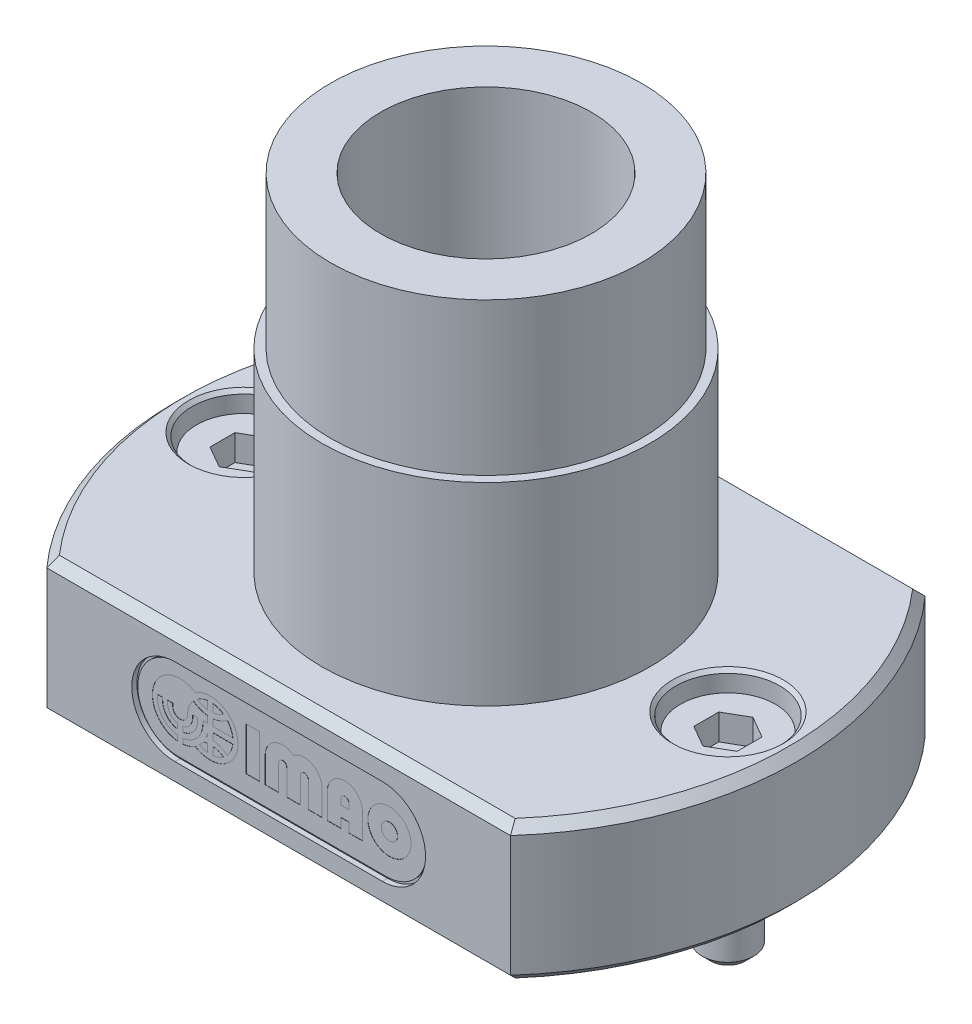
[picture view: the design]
ISO-10303-21;
HEADER;
FILE_DESCRIPTION(('STEP AP214'),'2;1');
FILE_NAME('part.step','',(''),(''),'','','');
FILE_SCHEMA(('AUTOMOTIVE_DESIGN { 1 0 10303 214 1 1 1 1 }'));
ENDSEC;
DATA;
#1=APPLICATION_CONTEXT('core data for automotive mechanical design processes');
#2=APPLICATION_PROTOCOL_DEFINITION('international standard','automotive_design',2000,#1);
#3=PRODUCT_CONTEXT('',#1,'mechanical');
#4=PRODUCT('Part','Part','',(#3));
#5=PRODUCT_RELATED_PRODUCT_CATEGORY('part','',(#4));
#6=PRODUCT_DEFINITION_FORMATION('','',#4);
#7=PRODUCT_DEFINITION_CONTEXT('part definition',#1,'design');
#8=PRODUCT_DEFINITION('design','',#6,#7);
#9=PRODUCT_DEFINITION_SHAPE('','',#8);
#10=(LENGTH_UNIT() NAMED_UNIT(*) SI_UNIT(.MILLI.,.METRE.));
#11=(NAMED_UNIT(*) PLANE_ANGLE_UNIT() SI_UNIT($,.RADIAN.));
#12=(NAMED_UNIT(*) SI_UNIT($,.STERADIAN.) SOLID_ANGLE_UNIT());
#13=UNCERTAINTY_MEASURE_WITH_UNIT(LENGTH_MEASURE(1.E-05),#10,'distance_accuracy_value','');
#14=(GEOMETRIC_REPRESENTATION_CONTEXT(3) GLOBAL_UNCERTAINTY_ASSIGNED_CONTEXT((#13)) GLOBAL_UNIT_ASSIGNED_CONTEXT((#10,
#11,#12)) REPRESENTATION_CONTEXT('',''));
#15=CARTESIAN_POINT('',(0.,0.,0.));
#16=DIRECTION('',(0.,0.,1.));
#17=DIRECTION('',(1.,0.,0.));
#18=AXIS2_PLACEMENT_3D('',#15,#16,#17);
#19=CARTESIAN_POINT('',(-6.,4.,11.8));
#20=DIRECTION('',(0.,0.,1.));
#21=DIRECTION('',(1.,0.,0.));
#22=AXIS2_PLACEMENT_3D('',#19,#20,#21);
#23=PLANE('',#22);
#24=CARTESIAN_POINT('',(6.20934262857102,4.,11.8));
#25=DIRECTION('',(0.,0.,1.));
#26=DIRECTION('',(1.,0.,0.));
#27=AXIS2_PLACEMENT_3D('',#24,#25,#26);
#28=CIRCLE('',#27,1.25038079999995);
#29=CARTESIAN_POINT('',(7.45972342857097,4.,11.8));
#30=VERTEX_POINT('',#29);
#31=EDGE_CURVE('E1095',#30,#30,#28,.T.);
#32=ORIENTED_EDGE('',*,*,#31,.F.);
#33=EDGE_LOOP('',(#32));
#34=FACE_BOUND('',#33,.T.);
#35=DIRECTION('',(0.,1.,0.));
#36=VECTOR('',#35,1.);
#37=CARTESIAN_POINT('',(4.64636662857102,4.,11.8));
#38=LINE('',#37,#36);
#39=CARTESIAN_POINT('',(4.64636662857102,2.74961920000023,11.8));
#40=VERTEX_POINT('',#39);
#41=CARTESIAN_POINT('',(4.64636662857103,4.23444661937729,11.8));
#42=VERTEX_POINT('',#41);
#43=EDGE_CURVE('E1154',#40,#42,#38,.T.);
#44=ORIENTED_EDGE('',*,*,#43,.F.);
#45=DIRECTION('',(1.,0.,0.));
#46=VECTOR('',#45,1.);
#47=CARTESIAN_POINT('',(-5.9,2.74961920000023,11.8));
#48=LINE('',#47,#46);
#49=CARTESIAN_POINT('',(3.86487862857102,2.74961920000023,11.8));
#50=VERTEX_POINT('',#49);
#51=EDGE_CURVE('E1132',#50,#40,#48,.T.);
#52=ORIENTED_EDGE('',*,*,#51,.F.);
#53=DIRECTION('',(0.,1.,0.));
#54=VECTOR('',#53,1.);
#55=CARTESIAN_POINT('',(3.86487862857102,4.,11.8));
#56=LINE('',#55,#54);
#57=CARTESIAN_POINT('',(3.86487862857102,3.29666080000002,11.8));
#58=VERTEX_POINT('',#57);
#59=EDGE_CURVE('E1135',#50,#58,#56,.T.);
#60=ORIENTED_EDGE('',*,*,#59,.T.);
#61=DIRECTION('',(1.,-2.21976981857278E-13,0.));
#62=VECTOR('',#61,1.);
#63=CARTESIAN_POINT('',(-5.90000000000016,3.29666080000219,11.8));
#64=LINE('',#63,#62);
#65=CARTESIAN_POINT('',(3.39598582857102,3.29666080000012,11.8));
#66=VERTEX_POINT('',#65);
#67=EDGE_CURVE('E1139',#66,#58,#64,.T.);
#68=ORIENTED_EDGE('',*,*,#67,.F.);
#69=DIRECTION('',(0.,1.,0.));
#70=VECTOR('',#69,1.);
#71=CARTESIAN_POINT('',(3.39598582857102,4.,11.8));
#72=LINE('',#71,#70);
#73=CARTESIAN_POINT('',(3.39598582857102,2.74961919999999,11.8));
#74=VERTEX_POINT('',#73);
#75=EDGE_CURVE('E1142',#74,#66,#72,.T.);
#76=ORIENTED_EDGE('',*,*,#75,.F.);
#77=DIRECTION('',(1.,0.,0.));
#78=VECTOR('',#77,1.);
#79=CARTESIAN_POINT('',(-5.9,2.7496192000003,11.8));
#80=LINE('',#79,#78);
#81=CARTESIAN_POINT('',(2.61449782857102,2.74961920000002,11.8));
#82=VERTEX_POINT('',#81);
#83=EDGE_CURVE('E1145',#82,#74,#80,.T.);
#84=ORIENTED_EDGE('',*,*,#83,.F.);
#85=DIRECTION('',(0.,-1.,0.));
#86=VECTOR('',#85,1.);
#87=CARTESIAN_POINT('',(2.61449782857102,4.,11.8));
#88=LINE('',#87,#86);
#89=CARTESIAN_POINT('',(2.61449782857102,4.23444661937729,11.8));
#90=VERTEX_POINT('',#89);
#91=EDGE_CURVE('E1148',#90,#82,#88,.T.);
#92=ORIENTED_EDGE('',*,*,#91,.F.);
#93=CARTESIAN_POINT('',(3.63043222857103,4.23444661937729,11.8));
#94=DIRECTION('',(0.,0.,1.));
#95=DIRECTION('',(1.,0.,0.));
#96=AXIS2_PLACEMENT_3D('',#93,#94,#95);
#97=CIRCLE('',#96,1.0159344);
#98=EDGE_CURVE('E1151',#42,#90,#97,.T.);
#99=ORIENTED_EDGE('',*,*,#98,.F.);
#100=EDGE_LOOP('',(#44,#52,#60,#68,#76,#84,#92,#99));
#101=FACE_BOUND('',#100,.T.);
#102=CARTESIAN_POINT('',(1.28596822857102,4.23444640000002,11.8));
#103=DIRECTION('',(0.,0.,1.));
#104=DIRECTION('',(1.,0.,0.));
#105=AXIS2_PLACEMENT_3D('',#102,#103,#104);
#106=CIRCLE('',#105,1.0159344);
#107=CARTESIAN_POINT('',(2.30190262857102,4.23444640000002,11.8));
#108=VERTEX_POINT('',#107);
#109=CARTESIAN_POINT('',(0.660777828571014,5.03523330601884,11.8));
#110=VERTEX_POINT('',#109);
#111=EDGE_CURVE('E1261',#108,#110,#106,.T.);
#112=ORIENTED_EDGE('',*,*,#111,.F.);
#113=DIRECTION('',(0.,1.,0.));
#114=VECTOR('',#113,1.);
#115=CARTESIAN_POINT('',(2.30190262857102,4.,11.8));
#116=LINE('',#115,#114);
#117=CARTESIAN_POINT('',(2.30190262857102,2.74961920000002,11.8));
#118=VERTEX_POINT('',#117);
#119=EDGE_CURVE('E1224',#118,#108,#116,.T.);
#120=ORIENTED_EDGE('',*,*,#119,.F.);
#121=DIRECTION('',(1.,0.,0.));
#122=VECTOR('',#121,1.);
#123=CARTESIAN_POINT('',(-5.9,2.74961920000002,11.8));
#124=LINE('',#123,#122);
#125=CARTESIAN_POINT('',(1.52041462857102,2.74961920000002,11.8));
#126=VERTEX_POINT('',#125);
#127=EDGE_CURVE('E1227',#126,#118,#124,.T.);
#128=ORIENTED_EDGE('',*,*,#127,.F.);
#129=DIRECTION('',(0.,-1.,0.));
#130=VECTOR('',#129,1.);
#131=CARTESIAN_POINT('',(1.52041462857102,4.,11.8));
#132=LINE('',#131,#130);
#133=CARTESIAN_POINT('',(1.52041462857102,4.23444640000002,11.8));
#134=VERTEX_POINT('',#133);
#135=EDGE_CURVE('E1231',#134,#126,#132,.T.);
#136=ORIENTED_EDGE('',*,*,#135,.F.);
#137=CARTESIAN_POINT('',(1.28596822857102,4.23444640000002,11.8));
#138=DIRECTION('',(0.,0.,1.));
#139=DIRECTION('',(1.,0.,0.));
#140=AXIS2_PLACEMENT_3D('',#137,#138,#139);
#141=CIRCLE('',#140,0.2344464);
#142=CARTESIAN_POINT('',(1.05152182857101,4.23444640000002,11.8));
#143=VERTEX_POINT('',#142);
#144=EDGE_CURVE('E1234',#134,#143,#141,.T.);
#145=ORIENTED_EDGE('',*,*,#144,.T.);
#146=DIRECTION('',(0.,1.,0.));
#147=VECTOR('',#146,1.);
#148=CARTESIAN_POINT('',(1.05152182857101,4.,11.8));
#149=LINE('',#148,#147);
#150=CARTESIAN_POINT('',(1.05152182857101,2.74961920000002,11.8));
#151=VERTEX_POINT('',#150);
#152=EDGE_CURVE('E1237',#151,#143,#149,.T.);
#153=ORIENTED_EDGE('',*,*,#152,.F.);
#154=DIRECTION('',(1.,0.,0.));
#155=VECTOR('',#154,1.);
#156=CARTESIAN_POINT('',(-5.9,2.74961920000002,11.8));
#157=LINE('',#156,#155);
#158=CARTESIAN_POINT('',(0.270033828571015,2.74961920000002,11.8));
#159=VERTEX_POINT('',#158);
#160=EDGE_CURVE('E1240',#159,#151,#157,.T.);
#161=ORIENTED_EDGE('',*,*,#160,.F.);
#162=DIRECTION('',(0.,-1.,0.));
#163=VECTOR('',#162,1.);
#164=CARTESIAN_POINT('',(0.270033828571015,4.,11.8));
#165=LINE('',#164,#163);
#166=CARTESIAN_POINT('',(0.270033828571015,4.23444640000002,11.8));
#167=VERTEX_POINT('',#166);
#168=EDGE_CURVE('E1243',#167,#159,#165,.T.);
#169=ORIENTED_EDGE('',*,*,#168,.F.);
#170=CARTESIAN_POINT('',(0.0355874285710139,4.23444640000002,11.8));
#171=DIRECTION('',(0.,0.,1.));
#172=DIRECTION('',(1.,0.,0.));
#173=AXIS2_PLACEMENT_3D('',#170,#171,#172);
#174=CIRCLE('',#173,0.2344464);
#175=CARTESIAN_POINT('',(-0.198858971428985,4.23444640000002,11.8));
#176=VERTEX_POINT('',#175);
#177=EDGE_CURVE('E1246',#167,#176,#174,.T.);
#178=ORIENTED_EDGE('',*,*,#177,.T.);
#179=DIRECTION('',(0.,1.,0.));
#180=VECTOR('',#179,1.);
#181=CARTESIAN_POINT('',(-0.198858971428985,4.,11.8));
#182=LINE('',#181,#180);
#183=CARTESIAN_POINT('',(-0.198858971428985,2.74961920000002,11.8));
#184=VERTEX_POINT('',#183);
#185=EDGE_CURVE('E1249',#184,#176,#182,.T.);
#186=ORIENTED_EDGE('',*,*,#185,.F.);
#187=DIRECTION('',(1.,0.,0.));
#188=VECTOR('',#187,1.);
#189=CARTESIAN_POINT('',(-5.9,2.74961920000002,11.8));
#190=LINE('',#189,#188);
#191=CARTESIAN_POINT('',(-0.980346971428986,2.74961920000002,11.8));
#192=VERTEX_POINT('',#191);
#193=EDGE_CURVE('E1252',#192,#184,#190,.T.);
#194=ORIENTED_EDGE('',*,*,#193,.F.);
#195=DIRECTION('',(0.,-1.,0.));
#196=VECTOR('',#195,1.);
#197=CARTESIAN_POINT('',(-0.980346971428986,4.,11.8));
#198=LINE('',#197,#196);
#199=CARTESIAN_POINT('',(-0.980346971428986,4.23444640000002,11.8));
#200=VERTEX_POINT('',#199);
#201=EDGE_CURVE('E1255',#200,#192,#198,.T.);
#202=ORIENTED_EDGE('',*,*,#201,.F.);
#203=CARTESIAN_POINT('',(0.0355874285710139,4.23444640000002,11.8));
#204=DIRECTION('',(0.,0.,1.));
#205=DIRECTION('',(1.,0.,0.));
#206=AXIS2_PLACEMENT_3D('',#203,#204,#205);
#207=CIRCLE('',#206,1.0159344);
#208=EDGE_CURVE('E1258',#110,#200,#207,.T.);
#209=ORIENTED_EDGE('',*,*,#208,.F.);
#210=EDGE_LOOP('',(#112,#120,#128,#136,#145,#153,#161,#169,#178,#186,#194,#202,#209));
#211=FACE_BOUND('',#210,.T.);
#212=DIRECTION('',(1.,0.,0.));
#213=VECTOR('',#212,1.);
#214=CARTESIAN_POINT('',(-5.9,2.74961920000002,11.8));
#215=LINE('',#214,#213);
#216=CARTESIAN_POINT('',(-2.07443017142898,2.74961920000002,11.8));
#217=VERTEX_POINT('',#216);
#218=CARTESIAN_POINT('',(-1.29294217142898,2.74961920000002,11.8));
#219=VERTEX_POINT('',#218);
#220=EDGE_CURVE('E1318',#217,#219,#215,.T.);
#221=ORIENTED_EDGE('',*,*,#220,.F.);
#222=DIRECTION('',(0.,-1.,0.));
#223=VECTOR('',#222,1.);
#224=CARTESIAN_POINT('',(-2.07443017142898,4.,11.8));
#225=LINE('',#224,#223);
#226=CARTESIAN_POINT('',(-2.07443017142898,5.25038080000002,11.8));
#227=VERTEX_POINT('',#226);
#228=EDGE_CURVE('E1308',#227,#217,#225,.T.);
#229=ORIENTED_EDGE('',*,*,#228,.F.);
#230=DIRECTION('',(-1.,0.,0.));
#231=VECTOR('',#230,1.);
#232=CARTESIAN_POINT('',(-5.9,5.25038080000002,11.8));
#233=LINE('',#232,#231);
#234=CARTESIAN_POINT('',(-1.29294217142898,5.25038080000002,11.8));
#235=VERTEX_POINT('',#234);
#236=EDGE_CURVE('E1311',#235,#227,#233,.T.);
#237=ORIENTED_EDGE('',*,*,#236,.F.);
#238=DIRECTION('',(0.,1.,0.));
#239=VECTOR('',#238,1.);
#240=CARTESIAN_POINT('',(-1.29294217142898,4.,11.8));
#241=LINE('',#240,#239);
#242=EDGE_CURVE('E1315',#219,#235,#241,.T.);
#243=ORIENTED_EDGE('',*,*,#242,.F.);
#244=EDGE_LOOP('',(#221,#229,#237,#243));
#245=FACE_BOUND('',#244,.T.);
#246=CARTESIAN_POINT('',(-6.,4.,11.8));
#247=DIRECTION('',(0.,0.,1.));
#248=DIRECTION('',(1.,0.,0.));
#249=AXIS2_PLACEMENT_3D('',#246,#247,#248);
#250=CIRCLE('',#249,2.35);
#251=CARTESIAN_POINT('',(-6.,6.35,11.8));
#252=VERTEX_POINT('',#251);
#253=CARTESIAN_POINT('',(-6.,1.65,11.8));
#254=VERTEX_POINT('',#253);
#255=EDGE_CURVE('E1591',#252,#254,#250,.T.);
#256=ORIENTED_EDGE('',*,*,#255,.T.);
#257=DIRECTION('',(1.,0.,0.));
#258=VECTOR('',#257,1.);
#259=CARTESIAN_POINT('',(-6.,1.65,11.8));
#260=LINE('',#259,#258);
#261=CARTESIAN_POINT('',(6.,1.65,11.8));
#262=VERTEX_POINT('',#261);
#263=EDGE_CURVE('E1709',#254,#262,#260,.T.);
#264=ORIENTED_EDGE('',*,*,#263,.T.);
#265=CARTESIAN_POINT('',(6.,4.,11.8));
#266=DIRECTION('',(0.,0.,1.));
#267=DIRECTION('',(1.,0.,0.));
#268=AXIS2_PLACEMENT_3D('',#265,#266,#267);
#269=CIRCLE('',#268,2.35);
#270=CARTESIAN_POINT('',(6.,6.35,11.8));
#271=VERTEX_POINT('',#270);
#272=EDGE_CURVE('E1712',#262,#271,#269,.T.);
#273=ORIENTED_EDGE('',*,*,#272,.T.);
#274=DIRECTION('',(-1.,0.,0.));
#275=VECTOR('',#274,1.);
#276=CARTESIAN_POINT('',(-6.,6.35,11.8));
#277=LINE('',#276,#275);
#278=EDGE_CURVE('E1698',#271,#252,#277,.T.);
#279=ORIENTED_EDGE('',*,*,#278,.T.);
#280=EDGE_LOOP('',(#256,#264,#273,#279));
#281=FACE_BOUND('',#280,.T.);
#282=CARTESIAN_POINT('',(-4.15839817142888,6.14350994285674,11.8));
#283=DIRECTION('',(0.,0.,1.));
#284=DIRECTION('',(1.,0.,0.));
#285=AXIS2_PLACEMENT_3D('',#282,#283,#284);
#286=CIRCLE('',#285,1.60763245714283);
#287=CARTESIAN_POINT('',(-5.14080342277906,4.8709683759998,11.8));
#288=VERTEX_POINT('',#287);
#289=CARTESIAN_POINT('',(-4.31916141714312,4.54393584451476,11.8));
#290=VERTEX_POINT('',#289);
#291=EDGE_CURVE('E1456',#288,#290,#286,.T.);
#292=ORIENTED_EDGE('',*,*,#291,.F.);
#293=CARTESIAN_POINT('',(-4.15839817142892,4.,11.8));
#294=DIRECTION('',(0.,0.,1.));
#295=DIRECTION('',(1.,0.,0.));
#296=AXIS2_PLACEMENT_3D('',#293,#294,#295);
#297=CIRCLE('',#296,1.31289983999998);
#298=CARTESIAN_POINT('',(-5.4712980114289,4.,11.8));
#299=VERTEX_POINT('',#298);
#300=EDGE_CURVE('E1320',#288,#299,#297,.T.);
#301=ORIENTED_EDGE('',*,*,#300,.T.);
#302=CARTESIAN_POINT('',(-5.9,4.,11.8));
#303=DIRECTION('',(0.,0.,1.));
#304=DIRECTION('',(1.,0.,0.));
#305=AXIS2_PLACEMENT_3D('',#302,#303,#304);
#306=CIRCLE('',#305,0.428701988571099);
#307=CARTESIAN_POINT('',(-6.3287019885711,4.,11.8));
#308=VERTEX_POINT('',#307);
#309=EDGE_CURVE('E1516',#308,#299,#306,.T.);
#310=ORIENTED_EDGE('',*,*,#309,.F.);
#311=DIRECTION('',(0.,-1.,0.));
#312=VECTOR('',#311,1.);
#313=CARTESIAN_POINT('',(-6.3287019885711,4.,11.8));
#314=LINE('',#313,#312);
#315=CARTESIAN_POINT('',(-6.3287019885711,4.16076324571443,11.8));
#316=VERTEX_POINT('',#315);
#317=EDGE_CURVE('E1513',#316,#308,#314,.T.);
#318=ORIENTED_EDGE('',*,*,#317,.F.);
#319=DIRECTION('',(1.,0.,0.));
#320=VECTOR('',#319,1.);
#321=CARTESIAN_POINT('',(-5.9,4.16076324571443,11.8));
#322=LINE('',#321,#320);
#323=CARTESIAN_POINT('',(-6.62343460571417,4.16076324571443,11.8));
#324=VERTEX_POINT('',#323);
#325=EDGE_CURVE('E1510',#324,#316,#322,.T.);
#326=ORIENTED_EDGE('',*,*,#325,.F.);
#327=DIRECTION('',(0.,1.,0.));
#328=VECTOR('',#327,1.);
#329=CARTESIAN_POINT('',(-6.62343460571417,4.,11.8));
#330=LINE('',#329,#328);
#331=CARTESIAN_POINT('',(-6.62343460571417,4.,11.8));
#332=VERTEX_POINT('',#331);
#333=EDGE_CURVE('E1507',#332,#324,#330,.T.);
#334=ORIENTED_EDGE('',*,*,#333,.F.);
#335=CARTESIAN_POINT('',(-5.9,4.,11.8));
#336=DIRECTION('',(0.,0.,1.));
#337=DIRECTION('',(1.,0.,0.));
#338=AXIS2_PLACEMENT_3D('',#335,#336,#337);
#339=CIRCLE('',#338,0.723434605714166);
#340=CARTESIAN_POINT('',(-6.06076324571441,3.29465412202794,11.8));
#341=VERTEX_POINT('',#340);
#342=EDGE_CURVE('E1504',#332,#341,#339,.T.);
#343=ORIENTED_EDGE('',*,*,#342,.T.);
#344=DIRECTION('',(0.,1.,0.));
#345=VECTOR('',#344,1.);
#346=CARTESIAN_POINT('',(-6.06076324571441,4.,11.8));
#347=LINE('',#346,#345);
#348=CARTESIAN_POINT('',(-6.06076324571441,2.99460471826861,11.8));
#349=VERTEX_POINT('',#348);
#350=EDGE_CURVE('E1501',#349,#341,#347,.T.);
#351=ORIENTED_EDGE('',*,*,#350,.F.);
#352=CARTESIAN_POINT('',(-5.9,4.,11.8));
#353=DIRECTION('',(0.,0.,1.));
#354=DIRECTION('',(1.,0.,0.));
#355=AXIS2_PLACEMENT_3D('',#352,#353,#354);
#356=CIRCLE('',#355,1.01816722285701);
#357=CARTESIAN_POINT('',(-6.91816722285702,4.,11.8));
#358=VERTEX_POINT('',#357);
#359=EDGE_CURVE('E1498',#358,#349,#356,.T.);
#360=ORIENTED_EDGE('',*,*,#359,.F.);
#361=DIRECTION('',(0.,-1.,0.));
#362=VECTOR('',#361,1.);
#363=CARTESIAN_POINT('',(-6.91816722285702,4.,11.8));
#364=LINE('',#363,#362);
#365=CARTESIAN_POINT('',(-6.91816722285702,4.16076324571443,11.8));
#366=VERTEX_POINT('',#365);
#367=EDGE_CURVE('E1495',#366,#358,#364,.T.);
#368=ORIENTED_EDGE('',*,*,#367,.F.);
#369=DIRECTION('',(1.,0.,0.));
#370=VECTOR('',#369,1.);
#371=CARTESIAN_POINT('',(-5.9,4.16076324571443,11.8));
#372=LINE('',#371,#370);
#373=CARTESIAN_POINT('',(-7.21289983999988,4.16076324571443,11.8));
#374=VERTEX_POINT('',#373);
#375=EDGE_CURVE('E1492',#374,#366,#372,.T.);
#376=ORIENTED_EDGE('',*,*,#375,.F.);
#377=DIRECTION('',(0.,1.,0.));
#378=VECTOR('',#377,1.);
#379=CARTESIAN_POINT('',(-7.21289983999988,4.,11.8));
#380=LINE('',#379,#378);
#381=CARTESIAN_POINT('',(-7.21289983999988,3.99999999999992,11.8));
#382=VERTEX_POINT('',#381);
#383=EDGE_CURVE('E1489',#382,#374,#380,.T.);
#384=ORIENTED_EDGE('',*,*,#383,.F.);
#385=CARTESIAN_POINT('',(-5.9,4.,11.8));
#386=DIRECTION('',(0.,0.,1.));
#387=DIRECTION('',(1.,0.,0.));
#388=AXIS2_PLACEMENT_3D('',#385,#386,#387);
#389=CIRCLE('',#388,1.31289983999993);
#390=CARTESIAN_POINT('',(-6.06076324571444,2.69697998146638,11.8));
#391=VERTEX_POINT('',#390);
#392=EDGE_CURVE('E1486',#382,#391,#389,.T.);
#393=ORIENTED_EDGE('',*,*,#392,.T.);
#394=DIRECTION('',(0.,1.,0.));
#395=VECTOR('',#394,1.);
#396=CARTESIAN_POINT('',(-6.06076324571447,4.,11.8));
#397=LINE('',#396,#395);
#398=CARTESIAN_POINT('',(-6.06076324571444,2.40042590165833,11.8));
#399=VERTEX_POINT('',#398);
#400=EDGE_CURVE('E1483',#399,#391,#397,.T.);
#401=ORIENTED_EDGE('',*,*,#400,.F.);
#402=CARTESIAN_POINT('',(-5.9,4.,11.8));
#403=DIRECTION('',(0.,0.,1.));
#404=DIRECTION('',(1.,0.,0.));
#405=AXIS2_PLACEMENT_3D('',#402,#403,#404);
#406=CIRCLE('',#405,1.60763245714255);
#407=CARTESIAN_POINT('',(-5.02919908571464,5.35136519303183,11.8));
#408=VERTEX_POINT('',#407);
#409=EDGE_CURVE('E1480',#408,#399,#406,.T.);
#410=ORIENTED_EDGE('',*,*,#409,.F.);
#411=CARTESIAN_POINT('',(-4.15839817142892,4.,11.8));
#412=DIRECTION('',(0.,0.,1.));
#413=DIRECTION('',(1.,0.,0.));
#414=AXIS2_PLACEMENT_3D('',#411,#412,#413);
#415=CIRCLE('',#414,1.60763245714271);
#416=CARTESIAN_POINT('',(-5.02919908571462,2.64863480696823,11.8));
#417=VERTEX_POINT('',#416);
#418=EDGE_CURVE('E1477',#417,#408,#415,.T.);
#419=ORIENTED_EDGE('',*,*,#418,.F.);
#420=CARTESIAN_POINT('',(-5.9,4.,11.8));
#421=DIRECTION('',(0.,0.,1.));
#422=DIRECTION('',(1.,0.,0.));
#423=AXIS2_PLACEMENT_3D('',#420,#421,#422);
#424=CIRCLE('',#423,1.60763245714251);
#425=CARTESIAN_POINT('',(-5.73923675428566,2.40042590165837,11.8));
#426=VERTEX_POINT('',#425);
#427=EDGE_CURVE('E1474',#426,#417,#424,.T.);
#428=ORIENTED_EDGE('',*,*,#427,.F.);
#429=DIRECTION('',(0.,1.,0.));
#430=VECTOR('',#429,1.);
#431=CARTESIAN_POINT('',(-5.73923675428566,4.,11.8));
#432=LINE('',#431,#430);
#433=CARTESIAN_POINT('',(-5.73923675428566,2.69697998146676,11.8));
#434=VERTEX_POINT('',#433);
#435=EDGE_CURVE('E1471',#426,#434,#432,.T.);
#436=ORIENTED_EDGE('',*,*,#435,.T.);
#437=CARTESIAN_POINT('',(-5.9,4.,11.8));
#438=DIRECTION('',(0.,0.,1.));
#439=DIRECTION('',(1.,0.,0.));
#440=AXIS2_PLACEMENT_3D('',#437,#438,#439);
#441=CIRCLE('',#440,1.3128998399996);
#442=CARTESIAN_POINT('',(-4.58710016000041,4.,11.8));
#443=VERTEX_POINT('',#442);
#444=EDGE_CURVE('E1468',#434,#443,#441,.T.);
#445=ORIENTED_EDGE('',*,*,#444,.T.);
#446=DIRECTION('',(0.,-1.,0.));
#447=VECTOR('',#446,1.);
#448=CARTESIAN_POINT('',(-4.58710016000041,4.,11.8));
#449=LINE('',#448,#447);
#450=CARTESIAN_POINT('',(-4.58710016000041,4.16076324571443,11.8));
#451=VERTEX_POINT('',#450);
#452=EDGE_CURVE('E1465',#451,#443,#449,.T.);
#453=ORIENTED_EDGE('',*,*,#452,.F.);
#454=DIRECTION('',(1.,0.,0.));
#455=VECTOR('',#454,1.);
#456=CARTESIAN_POINT('',(-5.9,4.16076324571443,11.8));
#457=LINE('',#456,#455);
#458=CARTESIAN_POINT('',(-4.31916141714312,4.16076324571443,11.8));
#459=VERTEX_POINT('',#458);
#460=EDGE_CURVE('E1462',#451,#459,#457,.T.);
#461=ORIENTED_EDGE('',*,*,#460,.T.);
#462=DIRECTION('',(0.,1.,0.));
#463=VECTOR('',#462,1.);
#464=CARTESIAN_POINT('',(-4.31916141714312,4.,11.8));
#465=LINE('',#464,#463);
#466=EDGE_CURVE('E1459',#459,#290,#465,.T.);
#467=ORIENTED_EDGE('',*,*,#466,.T.);
#468=EDGE_LOOP('',(#292,#301,#310,#318,#326,#334,#343,#351,#360,#368,#376,#384,#393,#401,#410,
#419,#428,#436,#445,#453,#461,#467));
#469=FACE_BOUND('',#468,.T.);
#470=CARTESIAN_POINT('',(-5.9,4.,11.8));
#471=DIRECTION('',(0.,0.,1.));
#472=DIRECTION('',(1.,0.,0.));
#473=AXIS2_PLACEMENT_3D('',#470,#471,#472);
#474=CIRCLE('',#473,1.01816722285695);
#475=CARTESIAN_POINT('',(-5.73923675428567,2.99460471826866,11.8));
#476=VERTEX_POINT('',#475);
#477=CARTESIAN_POINT('',(-4.88183277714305,4.,11.8));
#478=VERTEX_POINT('',#477);
#479=EDGE_CURVE('E1063',#476,#478,#474,.T.);
#480=ORIENTED_EDGE('',*,*,#479,.F.);
#481=DIRECTION('',(0.,1.,0.));
#482=VECTOR('',#481,1.);
#483=CARTESIAN_POINT('',(-5.73923675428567,2.99460471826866,11.8));
#484=LINE('',#483,#482);
#485=CARTESIAN_POINT('',(-5.73923675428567,3.29465412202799,11.8));
#486=VERTEX_POINT('',#485);
#487=EDGE_CURVE('E32',#476,#486,#484,.T.);
#488=ORIENTED_EDGE('',*,*,#487,.T.);
#489=CARTESIAN_POINT('',(-5.9,4.,11.8));
#490=DIRECTION('',(0.,0.,1.));
#491=DIRECTION('',(1.,0.,0.));
#492=AXIS2_PLACEMENT_3D('',#489,#490,#491);
#493=CIRCLE('',#492,0.723434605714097);
#494=CARTESIAN_POINT('',(-5.1765653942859,4.,11.8));
#495=VERTEX_POINT('',#494);
#496=EDGE_CURVE('E1076',#486,#495,#493,.T.);
#497=ORIENTED_EDGE('',*,*,#496,.T.);
#498=DIRECTION('',(0.,-1.,0.));
#499=VECTOR('',#498,1.);
#500=CARTESIAN_POINT('',(-5.1765653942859,4.16076324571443,11.8));
#501=LINE('',#500,#499);
#502=CARTESIAN_POINT('',(-5.1765653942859,4.16076324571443,11.8));
#503=VERTEX_POINT('',#502);
#504=EDGE_CURVE('E1073',#503,#495,#501,.T.);
#505=ORIENTED_EDGE('',*,*,#504,.F.);
#506=DIRECTION('',(1.,0.,0.));
#507=VECTOR('',#506,1.);
#508=CARTESIAN_POINT('',(-5.1765653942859,4.16076324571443,11.8));
#509=LINE('',#508,#507);
#510=CARTESIAN_POINT('',(-4.88183277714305,4.16076324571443,11.8));
#511=VERTEX_POINT('',#510);
#512=EDGE_CURVE('E1070',#503,#511,#509,.T.);
#513=ORIENTED_EDGE('',*,*,#512,.T.);
#514=DIRECTION('',(0.,1.,0.));
#515=VECTOR('',#514,1.);
#516=CARTESIAN_POINT('',(-4.88183277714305,4.,11.8));
#517=LINE('',#516,#515);
#518=EDGE_CURVE('E1066',#478,#511,#517,.T.);
#519=ORIENTED_EDGE('',*,*,#518,.F.);
#520=EDGE_LOOP('',(#480,#488,#497,#505,#513,#519));
#521=FACE_BOUND('',#520,.T.);
#522=ADVANCED_FACE('F15',(#34,#101,#211,#245,#281,#469,#521),#23,.T.);
#523=CARTESIAN_POINT('',(-6.,4.,11.7));
#524=DIRECTION('',(0.,0.,1.));
#525=DIRECTION('',(1.,0.,0.));
#526=AXIS2_PLACEMENT_3D('',#523,#524,#525);
#527=CYLINDRICAL_SURFACE('',#526,2.35);
#528=ORIENTED_EDGE('',*,*,#255,.F.);
#529=DIRECTION('',(0.,0.,1.));
#530=VECTOR('',#529,1.);
#531=CARTESIAN_POINT('',(-6.,6.35,11.7));
#532=LINE('',#531,#530);
#533=CARTESIAN_POINT('',(-6.,6.35,11.7));
#534=VERTEX_POINT('',#533);
#535=EDGE_CURVE('E10',#534,#252,#532,.T.);
#536=ORIENTED_EDGE('',*,*,#535,.F.);
#537=CARTESIAN_POINT('',(-6.,4.,11.7));
#538=DIRECTION('',(0.,0.,1.));
#539=DIRECTION('',(1.,0.,0.));
#540=AXIS2_PLACEMENT_3D('',#537,#538,#539);
#541=CIRCLE('',#540,2.35);
#542=CARTESIAN_POINT('',(-6.,1.65,11.7));
#543=VERTEX_POINT('',#542);
#544=EDGE_CURVE('E1694',#534,#543,#541,.T.);
#545=ORIENTED_EDGE('',*,*,#544,.T.);
#546=DIRECTION('',(0.,0.,1.));
#547=VECTOR('',#546,1.);
#548=CARTESIAN_POINT('',(-6.,1.65,11.7));
#549=LINE('',#548,#547);
#550=EDGE_CURVE('E19',#543,#254,#549,.T.);
#551=ORIENTED_EDGE('',*,*,#550,.T.);
#552=EDGE_LOOP('',(#528,#536,#545,#551));
#553=FACE_BOUND('',#552,.T.);
#554=ADVANCED_FACE('F17',(#553),#527,.T.);
#555=CARTESIAN_POINT('',(-6.,6.35,11.7));
#556=DIRECTION('',(0.,1.,0.));
#557=DIRECTION('',(-1.,0.,0.));
#558=AXIS2_PLACEMENT_3D('',#555,#556,#557);
#559=PLANE('',#558);
#560=ORIENTED_EDGE('',*,*,#278,.F.);
#561=DIRECTION('',(0.,0.,1.));
#562=VECTOR('',#561,1.);
#563=CARTESIAN_POINT('',(6.,6.35,11.7));
#564=LINE('',#563,#562);
#565=CARTESIAN_POINT('',(6.,6.35,11.7));
#566=VERTEX_POINT('',#565);
#567=EDGE_CURVE('E24',#566,#271,#564,.T.);
#568=ORIENTED_EDGE('',*,*,#567,.F.);
#569=DIRECTION('',(-1.,0.,0.));
#570=VECTOR('',#569,1.);
#571=CARTESIAN_POINT('',(-6.,6.35,11.7));
#572=LINE('',#571,#570);
#573=EDGE_CURVE('E1704',#566,#534,#572,.T.);
#574=ORIENTED_EDGE('',*,*,#573,.T.);
#575=ORIENTED_EDGE('',*,*,#535,.T.);
#576=EDGE_LOOP('',(#560,#568,#574,#575));
#577=FACE_BOUND('',#576,.T.);
#578=ADVANCED_FACE('F1732',(#577),#559,.T.);
#579=CARTESIAN_POINT('',(6.,4.,11.7));
#580=DIRECTION('',(0.,0.,1.));
#581=DIRECTION('',(1.,0.,0.));
#582=AXIS2_PLACEMENT_3D('',#579,#580,#581);
#583=CYLINDRICAL_SURFACE('',#582,2.35);
#584=ORIENTED_EDGE('',*,*,#272,.F.);
#585=DIRECTION('',(0.,0.,1.));
#586=VECTOR('',#585,1.);
#587=CARTESIAN_POINT('',(6.,1.65,11.7));
#588=LINE('',#587,#586);
#589=CARTESIAN_POINT('',(6.,1.65,11.7));
#590=VERTEX_POINT('',#589);
#591=EDGE_CURVE('E1717',#590,#262,#588,.T.);
#592=ORIENTED_EDGE('',*,*,#591,.F.);
#593=CARTESIAN_POINT('',(6.,4.,11.7));
#594=DIRECTION('',(0.,0.,1.));
#595=DIRECTION('',(1.,0.,0.));
#596=AXIS2_PLACEMENT_3D('',#593,#594,#595);
#597=CIRCLE('',#596,2.35);
#598=EDGE_CURVE('E1701',#590,#566,#597,.T.);
#599=ORIENTED_EDGE('',*,*,#598,.T.);
#600=ORIENTED_EDGE('',*,*,#567,.T.);
#601=EDGE_LOOP('',(#584,#592,#599,#600));
#602=FACE_BOUND('',#601,.T.);
#603=ADVANCED_FACE('F1735',(#602),#583,.T.);
#604=CARTESIAN_POINT('',(-6.,1.65,11.7));
#605=DIRECTION('',(0.,-1.,0.));
#606=DIRECTION('',(1.,0.,0.));
#607=AXIS2_PLACEMENT_3D('',#604,#605,#606);
#608=PLANE('',#607);
#609=ORIENTED_EDGE('',*,*,#263,.F.);
#610=ORIENTED_EDGE('',*,*,#550,.F.);
#611=DIRECTION('',(1.,0.,0.));
#612=VECTOR('',#611,1.);
#613=CARTESIAN_POINT('',(-6.,1.65,11.7));
#614=LINE('',#613,#612);
#615=EDGE_CURVE('E1697',#543,#590,#614,.T.);
#616=ORIENTED_EDGE('',*,*,#615,.T.);
#617=ORIENTED_EDGE('',*,*,#591,.T.);
#618=EDGE_LOOP('',(#609,#610,#616,#617));
#619=FACE_BOUND('',#618,.T.);
#620=ADVANCED_FACE('F1726',(#619),#608,.T.);
#621=CARTESIAN_POINT('',(-3.9976349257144,4.,11.79));
#622=DIRECTION('',(1.,0.,0.));
#623=DIRECTION('',(0.,0.,-1.));
#624=AXIS2_PLACEMENT_3D('',#621,#622,#623);
#625=PLANE('',#624);
#626=DIRECTION('',(0.,1.,0.));
#627=VECTOR('',#626,1.);
#628=CARTESIAN_POINT('',(-3.9976349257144,4.,11.8));
#629=LINE('',#628,#627);
#630=CARTESIAN_POINT('',(-3.9976349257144,4.16076324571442,11.8));
#631=VERTEX_POINT('',#630);
#632=CARTESIAN_POINT('',(-3.9976349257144,4.54393584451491,11.8));
#633=VERTEX_POINT('',#632);
#634=EDGE_CURVE('E1579',#631,#633,#629,.T.);
#635=ORIENTED_EDGE('',*,*,#634,.T.);
#636=DIRECTION('',(0.,0.,1.));
#637=VECTOR('',#636,1.);
#638=CARTESIAN_POINT('',(-3.9976349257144,4.54393584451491,11.79));
#639=LINE('',#638,#637);
#640=CARTESIAN_POINT('',(-3.9976349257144,4.54393584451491,11.79));
#641=VERTEX_POINT('',#640);
#642=EDGE_CURVE('E1597',#641,#633,#639,.T.);
#643=ORIENTED_EDGE('',*,*,#642,.F.);
#644=DIRECTION('',(0.,1.,0.));
#645=VECTOR('',#644,1.);
#646=CARTESIAN_POINT('',(-3.9976349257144,4.,11.79));
#647=LINE('',#646,#645);
#648=CARTESIAN_POINT('',(-3.9976349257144,4.16076324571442,11.79));
#649=VERTEX_POINT('',#648);
#650=EDGE_CURVE('E1442',#649,#641,#647,.T.);
#651=ORIENTED_EDGE('',*,*,#650,.F.);
#652=DIRECTION('',(0.,0.,1.));
#653=VECTOR('',#652,1.);
#654=CARTESIAN_POINT('',(-3.9976349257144,4.16076324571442,11.79));
#655=LINE('',#654,#653);
#656=EDGE_CURVE('E1589',#649,#631,#655,.T.);
#657=ORIENTED_EDGE('',*,*,#656,.T.);
#658=EDGE_LOOP('',(#635,#643,#651,#657));
#659=FACE_BOUND('',#658,.T.);
#660=ADVANCED_FACE('F1744',(#659),#625,.F.);
#661=CARTESIAN_POINT('',(-5.9,4.16076324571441,11.79));
#662=DIRECTION('',(0.,-1.,0.));
#663=DIRECTION('',(1.,0.,0.));
#664=AXIS2_PLACEMENT_3D('',#661,#662,#663);
#665=PLANE('',#664);
#666=DIRECTION('',(1.,0.,0.));
#667=VECTOR('',#666,1.);
#668=CARTESIAN_POINT('',(-5.9,4.16076324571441,11.8));
#669=LINE('',#668,#667);
#670=CARTESIAN_POINT('',(-2.8553781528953,4.16076324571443,11.8));
#671=VERTEX_POINT('',#670);
#672=EDGE_CURVE('E1334',#631,#671,#669,.T.);
#673=ORIENTED_EDGE('',*,*,#672,.F.);
#674=ORIENTED_EDGE('',*,*,#656,.F.);
#675=DIRECTION('',(1.,0.,0.));
#676=VECTOR('',#675,1.);
#677=CARTESIAN_POINT('',(-5.9,4.16076324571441,11.79));
#678=LINE('',#677,#676);
#679=CARTESIAN_POINT('',(-2.8553781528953,4.16076324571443,11.79));
#680=VERTEX_POINT('',#679);
#681=EDGE_CURVE('E1450',#649,#680,#678,.T.);
#682=ORIENTED_EDGE('',*,*,#681,.T.);
#683=DIRECTION('',(0.,0.,1.));
#684=VECTOR('',#683,1.);
#685=CARTESIAN_POINT('',(-2.8553781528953,4.16076324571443,11.79));
#686=LINE('',#685,#684);
#687=EDGE_CURVE('E1592',#680,#671,#686,.T.);
#688=ORIENTED_EDGE('',*,*,#687,.T.);
#689=EDGE_LOOP('',(#673,#674,#682,#688));
#690=FACE_BOUND('',#689,.T.);
#691=ADVANCED_FACE('F2138',(#690),#665,.T.);
#692=CARTESIAN_POINT('',(-4.15839817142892,4.,11.79));
#693=DIRECTION('',(0.,0.,1.));
#694=DIRECTION('',(1.,0.,0.));
#695=AXIS2_PLACEMENT_3D('',#692,#693,#694);
#696=CYLINDRICAL_SURFACE('',#695,1.31289983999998);
#697=CARTESIAN_POINT('',(-4.15839817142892,4.,11.8));
#698=DIRECTION('',(0.,0.,1.));
#699=DIRECTION('',(1.,0.,0.));
#700=AXIS2_PLACEMENT_3D('',#697,#698,#699);
#701=CIRCLE('',#700,1.31289983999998);
#702=CARTESIAN_POINT('',(-3.17599292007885,4.87096837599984,11.8));
#703=VERTEX_POINT('',#702);
#704=EDGE_CURVE('E1584',#671,#703,#701,.T.);
#705=ORIENTED_EDGE('',*,*,#704,.F.);
#706=ORIENTED_EDGE('',*,*,#687,.F.);
#707=CARTESIAN_POINT('',(-4.15839817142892,4.,11.79));
#708=DIRECTION('',(0.,0.,1.));
#709=DIRECTION('',(1.,0.,0.));
#710=AXIS2_PLACEMENT_3D('',#707,#708,#709);
#711=CIRCLE('',#710,1.31289983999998);
#712=CARTESIAN_POINT('',(-3.17599292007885,4.87096837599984,11.79));
#713=VERTEX_POINT('',#712);
#714=EDGE_CURVE('E1448',#680,#713,#711,.T.);
#715=ORIENTED_EDGE('',*,*,#714,.T.);
#716=DIRECTION('',(0.,0.,1.));
#717=VECTOR('',#716,1.);
#718=CARTESIAN_POINT('',(-3.17599292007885,4.87096837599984,11.79));
#719=LINE('',#718,#717);
#720=EDGE_CURVE('E1595',#713,#703,#719,.T.);
#721=ORIENTED_EDGE('',*,*,#720,.T.);
#722=EDGE_LOOP('',(#705,#706,#715,#721));
#723=FACE_BOUND('',#722,.T.);
#724=ADVANCED_FACE('F2141',(#723),#696,.T.);
#725=CARTESIAN_POINT('',(-4.15839817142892,4.,11.79));
#726=DIRECTION('',(0.,0.,1.));
#727=DIRECTION('',(1.,0.,0.));
#728=AXIS2_PLACEMENT_3D('',#725,#726,#727);
#729=CYLINDRICAL_SURFACE('',#728,1.31289983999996);
#730=CARTESIAN_POINT('',(-4.15839817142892,4.,11.8));
#731=DIRECTION('',(0.,0.,1.));
#732=DIRECTION('',(1.,0.,0.));
#733=AXIS2_PLACEMENT_3D('',#730,#731,#732);
#734=CIRCLE('',#733,1.31289983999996);
#735=CARTESIAN_POINT('',(-3.17599292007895,3.12903162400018,11.8));
#736=VERTEX_POINT('',#735);
#737=CARTESIAN_POINT('',(-2.8553781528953,3.8392367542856,11.8));
#738=VERTEX_POINT('',#737);
#739=EDGE_CURVE('E1567',#736,#738,#734,.T.);
#740=ORIENTED_EDGE('',*,*,#739,.F.);
#741=DIRECTION('',(0.,0.,1.));
#742=VECTOR('',#741,1.);
#743=CARTESIAN_POINT('',(-3.17599292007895,3.12903162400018,11.79));
#744=LINE('',#743,#742);
#745=CARTESIAN_POINT('',(-3.17599292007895,3.12903162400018,11.79));
#746=VERTEX_POINT('',#745);
#747=EDGE_CURVE('E1606',#746,#736,#744,.T.);
#748=ORIENTED_EDGE('',*,*,#747,.F.);
#749=CARTESIAN_POINT('',(-4.15839817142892,4.,11.79));
#750=DIRECTION('',(0.,0.,1.));
#751=DIRECTION('',(1.,0.,0.));
#752=AXIS2_PLACEMENT_3D('',#749,#750,#751);
#753=CIRCLE('',#752,1.31289983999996);
#754=CARTESIAN_POINT('',(-2.8553781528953,3.8392367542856,11.79));
#755=VERTEX_POINT('',#754);
#756=EDGE_CURVE('E1431',#746,#755,#753,.T.);
#757=ORIENTED_EDGE('',*,*,#756,.T.);
#758=DIRECTION('',(0.,0.,1.));
#759=VECTOR('',#758,1.);
#760=CARTESIAN_POINT('',(-2.8553781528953,3.8392367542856,11.79));
#761=LINE('',#760,#759);
#762=EDGE_CURVE('E1600',#755,#738,#761,.T.);
#763=ORIENTED_EDGE('',*,*,#762,.T.);
#764=EDGE_LOOP('',(#740,#748,#757,#763));
#765=FACE_BOUND('',#764,.T.);
#766=ADVANCED_FACE('F2144',(#765),#729,.T.);
#767=CARTESIAN_POINT('',(-5.9,3.83923675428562,11.79));
#768=DIRECTION('',(0.,-1.,0.));
#769=DIRECTION('',(1.,0.,0.));
#770=AXIS2_PLACEMENT_3D('',#767,#768,#769);
#771=PLANE('',#770);
#772=DIRECTION('',(1.,0.,0.));
#773=VECTOR('',#772,1.);
#774=CARTESIAN_POINT('',(-5.9,3.83923675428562,11.8));
#775=LINE('',#774,#773);
#776=CARTESIAN_POINT('',(-3.99763492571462,3.83923675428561,11.8));
#777=VERTEX_POINT('',#776);
#778=EDGE_CURVE('E1576',#777,#738,#775,.T.);
#779=ORIENTED_EDGE('',*,*,#778,.T.);
#780=ORIENTED_EDGE('',*,*,#762,.F.);
#781=DIRECTION('',(1.,0.,0.));
#782=VECTOR('',#781,1.);
#783=CARTESIAN_POINT('',(-5.9,3.83923675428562,11.79));
#784=LINE('',#783,#782);
#785=CARTESIAN_POINT('',(-3.99763492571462,3.83923675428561,11.79));
#786=VERTEX_POINT('',#785);
#787=EDGE_CURVE('E1439',#786,#755,#784,.T.);
#788=ORIENTED_EDGE('',*,*,#787,.F.);
#789=DIRECTION('',(0.,0.,1.));
#790=VECTOR('',#789,1.);
#791=CARTESIAN_POINT('',(-3.99763492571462,3.83923675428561,11.79));
#792=LINE('',#791,#790);
#793=EDGE_CURVE('E1602',#786,#777,#792,.T.);
#794=ORIENTED_EDGE('',*,*,#793,.T.);
#795=EDGE_LOOP('',(#779,#780,#788,#794));
#796=FACE_BOUND('',#795,.T.);
#797=ADVANCED_FACE('F2150',(#796),#771,.F.);
#798=CARTESIAN_POINT('',(-3.99763492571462,4.,11.79));
#799=DIRECTION('',(1.,0.,0.));
#800=DIRECTION('',(0.,0.,-1.));
#801=AXIS2_PLACEMENT_3D('',#798,#799,#800);
#802=PLANE('',#801);
#803=DIRECTION('',(0.,1.,0.));
#804=VECTOR('',#803,1.);
#805=CARTESIAN_POINT('',(-3.99763492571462,4.,11.8));
#806=LINE('',#805,#804);
#807=CARTESIAN_POINT('',(-3.99763492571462,3.45606415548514,11.8));
#808=VERTEX_POINT('',#807);
#809=EDGE_CURVE('E1573',#808,#777,#806,.T.);
#810=ORIENTED_EDGE('',*,*,#809,.T.);
#811=ORIENTED_EDGE('',*,*,#793,.F.);
#812=DIRECTION('',(0.,1.,0.));
#813=VECTOR('',#812,1.);
#814=CARTESIAN_POINT('',(-3.99763492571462,4.,11.79));
#815=LINE('',#814,#813);
#816=CARTESIAN_POINT('',(-3.99763492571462,3.45606415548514,11.79));
#817=VERTEX_POINT('',#816);
#818=EDGE_CURVE('E1436',#817,#786,#815,.T.);
#819=ORIENTED_EDGE('',*,*,#818,.F.);
#820=DIRECTION('',(0.,0.,1.));
#821=VECTOR('',#820,1.);
#822=CARTESIAN_POINT('',(-3.99763492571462,3.45606415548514,11.79));
#823=LINE('',#822,#821);
#824=EDGE_CURVE('E1604',#817,#808,#823,.T.);
#825=ORIENTED_EDGE('',*,*,#824,.T.);
#826=EDGE_LOOP('',(#810,#811,#819,#825));
#827=FACE_BOUND('',#826,.T.);
#828=ADVANCED_FACE('F2153',(#827),#802,.F.);
#829=CARTESIAN_POINT('',(-4.15839817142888,6.14350994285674,11.79));
#830=DIRECTION('',(0.,0.,1.));
#831=DIRECTION('',(1.,0.,0.));
#832=AXIS2_PLACEMENT_3D('',#829,#830,#831);
#833=CYLINDRICAL_SURFACE('',#832,1.31289983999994);
#834=CARTESIAN_POINT('',(-4.15839817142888,6.14350994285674,11.8));
#835=DIRECTION('',(0.,0.,1.));
#836=DIRECTION('',(1.,0.,0.));
#837=AXIS2_PLACEMENT_3D('',#834,#835,#836);
#838=CIRCLE('',#837,1.31289983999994);
#839=CARTESIAN_POINT('',(-4.91671688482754,5.07175497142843,11.8));
#840=VERTEX_POINT('',#839);
#841=CARTESIAN_POINT('',(-4.3191614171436,4.84048992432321,11.8));
#842=VERTEX_POINT('',#841);
#843=EDGE_CURVE('E1558',#840,#842,#838,.T.);
#844=ORIENTED_EDGE('',*,*,#843,.F.);
#845=DIRECTION('',(0.,0.,1.));
#846=VECTOR('',#845,1.);
#847=CARTESIAN_POINT('',(-4.91671688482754,5.07175497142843,11.79));
#848=LINE('',#847,#846);
#849=CARTESIAN_POINT('',(-4.91671688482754,5.07175497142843,11.79));
#850=VERTEX_POINT('',#849);
#851=EDGE_CURVE('E1614',#850,#840,#848,.T.);
#852=ORIENTED_EDGE('',*,*,#851,.F.);
#853=CARTESIAN_POINT('',(-4.15839817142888,6.14350994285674,11.79));
#854=DIRECTION('',(0.,0.,1.));
#855=DIRECTION('',(1.,0.,0.));
#856=AXIS2_PLACEMENT_3D('',#853,#854,#855);
#857=CIRCLE('',#856,1.31289983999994);
#858=CARTESIAN_POINT('',(-4.3191614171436,4.84048992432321,11.79));
#859=VERTEX_POINT('',#858);
#860=EDGE_CURVE('E1424',#850,#859,#857,.T.);
#861=ORIENTED_EDGE('',*,*,#860,.T.);
#862=DIRECTION('',(0.,0.,1.));
#863=VECTOR('',#862,1.);
#864=CARTESIAN_POINT('',(-4.3191614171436,4.84048992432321,11.79));
#865=LINE('',#864,#863);
#866=EDGE_CURVE('E1609',#859,#842,#865,.T.);
#867=ORIENTED_EDGE('',*,*,#866,.T.);
#868=EDGE_LOOP('',(#844,#852,#861,#867));
#869=FACE_BOUND('',#868,.T.);
#870=ADVANCED_FACE('F2157',(#869),#833,.T.);
#871=CARTESIAN_POINT('',(-4.3191614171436,4.,11.79));
#872=DIRECTION('',(1.,0.,0.));
#873=DIRECTION('',(0.,0.,-1.));
#874=AXIS2_PLACEMENT_3D('',#871,#872,#873);
#875=PLANE('',#874);
#876=DIRECTION('',(0.,1.,0.));
#877=VECTOR('',#876,1.);
#878=CARTESIAN_POINT('',(-4.3191614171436,4.,11.8));
#879=LINE('',#878,#877);
#880=CARTESIAN_POINT('',(-4.3191614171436,5.30302001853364,11.8));
#881=VERTEX_POINT('',#880);
#882=EDGE_CURVE('E1564',#842,#881,#879,.T.);
#883=ORIENTED_EDGE('',*,*,#882,.F.);
#884=ORIENTED_EDGE('',*,*,#866,.F.);
#885=DIRECTION('',(0.,1.,0.));
#886=VECTOR('',#885,1.);
#887=CARTESIAN_POINT('',(-4.3191614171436,4.,11.79));
#888=LINE('',#887,#886);
#889=CARTESIAN_POINT('',(-4.3191614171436,5.30302001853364,11.79));
#890=VERTEX_POINT('',#889);
#891=EDGE_CURVE('E1429',#859,#890,#888,.T.);
#892=ORIENTED_EDGE('',*,*,#891,.T.);
#893=DIRECTION('',(0.,0.,1.));
#894=VECTOR('',#893,1.);
#895=CARTESIAN_POINT('',(-4.3191614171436,5.30302001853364,11.79));
#896=LINE('',#895,#894);
#897=EDGE_CURVE('E1612',#890,#881,#896,.T.);
#898=ORIENTED_EDGE('',*,*,#897,.T.);
#899=EDGE_LOOP('',(#883,#884,#892,#898));
#900=FACE_BOUND('',#899,.T.);
#901=ADVANCED_FACE('F2166',(#900),#875,.T.);
#902=CARTESIAN_POINT('',(-4.15839817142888,6.14350994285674,11.79));
#903=DIRECTION('',(0.,0.,1.));
#904=DIRECTION('',(1.,0.,0.));
#905=AXIS2_PLACEMENT_3D('',#902,#903,#904);
#906=CYLINDRICAL_SURFACE('',#905,1.31289983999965);
#907=CARTESIAN_POINT('',(-4.15839817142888,6.14350994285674,11.8));
#908=DIRECTION('',(0.,0.,1.));
#909=DIRECTION('',(1.,0.,0.));
#910=AXIS2_PLACEMENT_3D('',#907,#908,#909);
#911=CIRCLE('',#910,1.31289983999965);
#912=CARTESIAN_POINT('',(-3.99763492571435,4.84048992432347,11.8));
#913=VERTEX_POINT('',#912);
#914=CARTESIAN_POINT('',(-3.40007945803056,5.07175497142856,11.8));
#915=VERTEX_POINT('',#914);
#916=EDGE_CURVE('E1549',#913,#915,#911,.T.);
#917=ORIENTED_EDGE('',*,*,#916,.F.);
#918=DIRECTION('',(0.,0.,1.));
#919=VECTOR('',#918,1.);
#920=CARTESIAN_POINT('',(-3.99763492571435,4.84048992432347,11.79));
#921=LINE('',#920,#919);
#922=CARTESIAN_POINT('',(-3.99763492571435,4.84048992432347,11.79));
#923=VERTEX_POINT('',#922);
#924=EDGE_CURVE('E1622',#923,#913,#921,.T.);
#925=ORIENTED_EDGE('',*,*,#924,.F.);
#926=CARTESIAN_POINT('',(-4.15839817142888,6.14350994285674,11.79));
#927=DIRECTION('',(0.,0.,1.));
#928=DIRECTION('',(1.,0.,0.));
#929=AXIS2_PLACEMENT_3D('',#926,#927,#928);
#930=CIRCLE('',#929,1.31289983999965);
#931=CARTESIAN_POINT('',(-3.40007945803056,5.07175497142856,11.79));
#932=VERTEX_POINT('',#931);
#933=EDGE_CURVE('E1416',#923,#932,#930,.T.);
#934=ORIENTED_EDGE('',*,*,#933,.T.);
#935=DIRECTION('',(0.,0.,1.));
#936=VECTOR('',#935,1.);
#937=CARTESIAN_POINT('',(-3.40007945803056,5.07175497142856,11.79));
#938=LINE('',#937,#936);
#939=EDGE_CURVE('E1617',#932,#915,#938,.T.);
#940=ORIENTED_EDGE('',*,*,#939,.T.);
#941=EDGE_LOOP('',(#917,#925,#934,#940));
#942=FACE_BOUND('',#941,.T.);
#943=ADVANCED_FACE('F2169',(#942),#906,.T.);
#944=CARTESIAN_POINT('',(-4.15839817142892,4.,11.79));
#945=DIRECTION('',(0.,0.,1.));
#946=DIRECTION('',(1.,0.,0.));
#947=AXIS2_PLACEMENT_3D('',#944,#945,#946);
#948=CYLINDRICAL_SURFACE('',#947,1.31289983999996);
#949=CARTESIAN_POINT('',(-4.15839817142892,4.,11.8));
#950=DIRECTION('',(0.,0.,1.));
#951=DIRECTION('',(1.,0.,0.));
#952=AXIS2_PLACEMENT_3D('',#949,#950,#951);
#953=CIRCLE('',#952,1.31289983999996);
#954=CARTESIAN_POINT('',(-3.99763492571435,5.30302001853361,11.8));
#955=VERTEX_POINT('',#954);
#956=EDGE_CURVE('E1555',#915,#955,#953,.T.);
#957=ORIENTED_EDGE('',*,*,#956,.F.);
#958=ORIENTED_EDGE('',*,*,#939,.F.);
#959=CARTESIAN_POINT('',(-4.15839817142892,4.,11.79));
#960=DIRECTION('',(0.,0.,1.));
#961=DIRECTION('',(1.,0.,0.));
#962=AXIS2_PLACEMENT_3D('',#959,#960,#961);
#963=CIRCLE('',#962,1.31289983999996);
#964=CARTESIAN_POINT('',(-3.99763492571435,5.30302001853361,11.79));
#965=VERTEX_POINT('',#964);
#966=EDGE_CURVE('E1422',#932,#965,#963,.T.);
#967=ORIENTED_EDGE('',*,*,#966,.T.);
#968=DIRECTION('',(0.,0.,1.));
#969=VECTOR('',#968,1.);
#970=CARTESIAN_POINT('',(-3.99763492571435,5.30302001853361,11.79));
#971=LINE('',#970,#969);
#972=EDGE_CURVE('E1620',#965,#955,#971,.T.);
#973=ORIENTED_EDGE('',*,*,#972,.T.);
#974=EDGE_LOOP('',(#957,#958,#967,#973));
#975=FACE_BOUND('',#974,.T.);
#976=ADVANCED_FACE('F2178',(#975),#948,.T.);
#977=CARTESIAN_POINT('',(-5.81044551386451,3.27249093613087,11.79));
#978=DIRECTION('',(0.122175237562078,-0.99250854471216,0.));
#979=DIRECTION('',(0.99250854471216,0.122175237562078,0.));
#980=AXIS2_PLACEMENT_3D('',#977,#978,#979);
#981=PLANE('',#980);
#982=DIRECTION('',(0.99250854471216,0.122175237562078,0.));
#983=VECTOR('',#982,1.);
#984=CARTESIAN_POINT('',(-5.81044551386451,3.27249093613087,11.8));
#985=LINE('',#984,#983);
#986=CARTESIAN_POINT('',(-4.39036288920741,3.44729943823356,11.8));
#987=VERTEX_POINT('',#986);
#988=CARTESIAN_POINT('',(-4.31916141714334,3.45606415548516,11.8));
#989=VERTEX_POINT('',#988);
#990=EDGE_CURVE('E1540',#987,#989,#985,.T.);
#991=ORIENTED_EDGE('',*,*,#990,.F.);
#992=DIRECTION('',(0.,0.,1.));
#993=VECTOR('',#992,1.);
#994=CARTESIAN_POINT('',(-4.39036288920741,3.44729943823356,11.79));
#995=LINE('',#994,#993);
#996=CARTESIAN_POINT('',(-4.39036288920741,3.44729943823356,11.79));
#997=VERTEX_POINT('',#996);
#998=EDGE_CURVE('E1630',#997,#987,#995,.T.);
#999=ORIENTED_EDGE('',*,*,#998,.F.);
#1000=DIRECTION('',(0.99250854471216,0.122175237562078,0.));
#1001=VECTOR('',#1000,1.);
#1002=CARTESIAN_POINT('',(-5.81044551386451,3.27249093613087,11.79));
#1003=LINE('',#1002,#1001);
#1004=CARTESIAN_POINT('',(-4.31916141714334,3.45606415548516,11.79));
#1005=VERTEX_POINT('',#1004);
#1006=EDGE_CURVE('E1408',#997,#1005,#1003,.T.);
#1007=ORIENTED_EDGE('',*,*,#1006,.T.);
#1008=DIRECTION('',(0.,0.,1.));
#1009=VECTOR('',#1008,1.);
#1010=CARTESIAN_POINT('',(-4.31916141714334,3.45606415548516,11.79));
#1011=LINE('',#1010,#1009);
#1012=EDGE_CURVE('E1625',#1005,#989,#1011,.T.);
#1013=ORIENTED_EDGE('',*,*,#1012,.T.);
#1014=EDGE_LOOP('',(#991,#999,#1007,#1013));
#1015=FACE_BOUND('',#1014,.T.);
#1016=ADVANCED_FACE('F2181',(#1015),#981,.T.);
#1017=CARTESIAN_POINT('',(-4.31916141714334,4.,11.79));
#1018=DIRECTION('',(1.,0.,0.));
#1019=DIRECTION('',(0.,0.,-1.));
#1020=AXIS2_PLACEMENT_3D('',#1017,#1018,#1019);
#1021=PLANE('',#1020);
#1022=DIRECTION('',(0.,1.,0.));
#1023=VECTOR('',#1022,1.);
#1024=CARTESIAN_POINT('',(-4.31916141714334,4.,11.8));
#1025=LINE('',#1024,#1023);
#1026=CARTESIAN_POINT('',(-4.31916141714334,3.7077133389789,11.8));
#1027=VERTEX_POINT('',#1026);
#1028=EDGE_CURVE('E1546',#989,#1027,#1025,.T.);
#1029=ORIENTED_EDGE('',*,*,#1028,.F.);
#1030=ORIENTED_EDGE('',*,*,#1012,.F.);
#1031=DIRECTION('',(0.,1.,0.));
#1032=VECTOR('',#1031,1.);
#1033=CARTESIAN_POINT('',(-4.31916141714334,4.,11.79));
#1034=LINE('',#1033,#1032);
#1035=CARTESIAN_POINT('',(-4.31916141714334,3.7077133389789,11.79));
#1036=VERTEX_POINT('',#1035);
#1037=EDGE_CURVE('E1414',#1005,#1036,#1034,.T.);
#1038=ORIENTED_EDGE('',*,*,#1037,.T.);
#1039=DIRECTION('',(0.,0.,1.));
#1040=VECTOR('',#1039,1.);
#1041=CARTESIAN_POINT('',(-4.31916141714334,3.7077133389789,11.79));
#1042=LINE('',#1041,#1040);
#1043=EDGE_CURVE('E1628',#1036,#1027,#1042,.T.);
#1044=ORIENTED_EDGE('',*,*,#1043,.T.);
#1045=EDGE_LOOP('',(#1029,#1030,#1038,#1044));
#1046=FACE_BOUND('',#1045,.T.);
#1047=ADVANCED_FACE('F2190',(#1046),#1021,.T.);
#1048=CARTESIAN_POINT('',(-4.15839817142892,4.,11.79));
#1049=DIRECTION('',(0.,0.,1.));
#1050=DIRECTION('',(1.,0.,0.));
#1051=AXIS2_PLACEMENT_3D('',#1048,#1049,#1050);
#1052=CYLINDRICAL_SURFACE('',#1051,1.31289984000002);
#1053=CARTESIAN_POINT('',(-4.15839817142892,4.,11.8));
#1054=DIRECTION('',(0.,0.,1.));
#1055=DIRECTION('',(1.,0.,0.));
#1056=AXIS2_PLACEMENT_3D('',#1053,#1054,#1055);
#1057=CIRCLE('',#1056,1.31289984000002);
#1058=CARTESIAN_POINT('',(-4.78207712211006,2.84469460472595,11.8));
#1059=VERTEX_POINT('',#1058);
#1060=CARTESIAN_POINT('',(-4.31916141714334,2.69697998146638,11.8));
#1061=VERTEX_POINT('',#1060);
#1062=EDGE_CURVE('E1528',#1059,#1061,#1057,.T.);
#1063=ORIENTED_EDGE('',*,*,#1062,.F.);
#1064=DIRECTION('',(0.,0.,1.));
#1065=VECTOR('',#1064,1.);
#1066=CARTESIAN_POINT('',(-4.78207712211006,2.84469460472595,11.79));
#1067=LINE('',#1066,#1065);
#1068=CARTESIAN_POINT('',(-4.78207712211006,2.84469460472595,11.79));
#1069=VERTEX_POINT('',#1068);
#1070=EDGE_CURVE('E1640',#1069,#1059,#1067,.T.);
#1071=ORIENTED_EDGE('',*,*,#1070,.F.);
#1072=CARTESIAN_POINT('',(-4.15839817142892,4.,11.79));
#1073=DIRECTION('',(0.,0.,1.));
#1074=DIRECTION('',(1.,0.,0.));
#1075=AXIS2_PLACEMENT_3D('',#1072,#1073,#1074);
#1076=CIRCLE('',#1075,1.31289984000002);
#1077=CARTESIAN_POINT('',(-4.31916141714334,2.69697998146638,11.79));
#1078=VERTEX_POINT('',#1077);
#1079=EDGE_CURVE('E1398',#1069,#1078,#1076,.T.);
#1080=ORIENTED_EDGE('',*,*,#1079,.T.);
#1081=DIRECTION('',(0.,0.,1.));
#1082=VECTOR('',#1081,1.);
#1083=CARTESIAN_POINT('',(-4.31916141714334,2.69697998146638,11.79));
#1084=LINE('',#1083,#1082);
#1085=EDGE_CURVE('E1633',#1078,#1061,#1084,.T.);
#1086=ORIENTED_EDGE('',*,*,#1085,.T.);
#1087=EDGE_LOOP('',(#1063,#1071,#1080,#1086));
#1088=FACE_BOUND('',#1087,.T.);
#1089=ADVANCED_FACE('F1822',(#1088),#1052,.T.);
#1090=CARTESIAN_POINT('',(-4.31916141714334,4.,11.79));
#1091=DIRECTION('',(1.,0.,0.));
#1092=DIRECTION('',(0.,0.,-1.));
#1093=AXIS2_PLACEMENT_3D('',#1090,#1091,#1092);
#1094=PLANE('',#1093);
#1095=DIRECTION('',(0.,1.,0.));
#1096=VECTOR('',#1095,1.);
#1097=CARTESIAN_POINT('',(-4.31916141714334,4.,11.8));
#1098=LINE('',#1097,#1096);
#1099=CARTESIAN_POINT('',(-4.31916141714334,3.15951007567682,11.8));
#1100=VERTEX_POINT('',#1099);
#1101=EDGE_CURVE('E1537',#1061,#1100,#1098,.T.);
#1102=ORIENTED_EDGE('',*,*,#1101,.F.);
#1103=ORIENTED_EDGE('',*,*,#1085,.F.);
#1104=DIRECTION('',(0.,1.,0.));
#1105=VECTOR('',#1104,1.);
#1106=CARTESIAN_POINT('',(-4.31916141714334,4.,11.79));
#1107=LINE('',#1106,#1105);
#1108=CARTESIAN_POINT('',(-4.31916141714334,3.15951007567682,11.79));
#1109=VERTEX_POINT('',#1108);
#1110=EDGE_CURVE('E1406',#1078,#1109,#1107,.T.);
#1111=ORIENTED_EDGE('',*,*,#1110,.T.);
#1112=DIRECTION('',(0.,0.,1.));
#1113=VECTOR('',#1112,1.);
#1114=CARTESIAN_POINT('',(-4.31916141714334,3.15951007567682,11.79));
#1115=LINE('',#1114,#1113);
#1116=EDGE_CURVE('E1636',#1109,#1100,#1115,.T.);
#1117=ORIENTED_EDGE('',*,*,#1116,.T.);
#1118=EDGE_LOOP('',(#1102,#1103,#1111,#1117));
#1119=FACE_BOUND('',#1118,.T.);
#1120=ADVANCED_FACE('F2200',(#1119),#1094,.T.);
#1121=CARTESIAN_POINT('',(-4.15839817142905,1.85649005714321,11.79));
#1122=DIRECTION('',(0.,0.,1.));
#1123=DIRECTION('',(1.,0.,0.));
#1124=AXIS2_PLACEMENT_3D('',#1121,#1122,#1123);
#1125=CYLINDRICAL_SURFACE('',#1124,1.31289983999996);
#1126=CARTESIAN_POINT('',(-4.15839817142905,1.85649005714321,11.8));
#1127=DIRECTION('',(0.,0.,1.));
#1128=DIRECTION('',(1.,0.,0.));
#1129=AXIS2_PLACEMENT_3D('',#1126,#1127,#1128);
#1130=CIRCLE('',#1129,1.31289983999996);
#1131=CARTESIAN_POINT('',(-4.564545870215,3.10498917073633,11.8));
#1132=VERTEX_POINT('',#1131);
#1133=EDGE_CURVE('E1534',#1100,#1132,#1130,.T.);
#1134=ORIENTED_EDGE('',*,*,#1133,.F.);
#1135=ORIENTED_EDGE('',*,*,#1116,.F.);
#1136=CARTESIAN_POINT('',(-4.15839817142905,1.85649005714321,11.79));
#1137=DIRECTION('',(0.,0.,1.));
#1138=DIRECTION('',(1.,0.,0.));
#1139=AXIS2_PLACEMENT_3D('',#1136,#1137,#1138);
#1140=CIRCLE('',#1139,1.31289983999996);
#1141=CARTESIAN_POINT('',(-4.564545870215,3.10498917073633,11.79));
#1142=VERTEX_POINT('',#1141);
#1143=EDGE_CURVE('E1404',#1109,#1142,#1140,.T.);
#1144=ORIENTED_EDGE('',*,*,#1143,.T.);
#1145=DIRECTION('',(0.,0.,1.));
#1146=VECTOR('',#1145,1.);
#1147=CARTESIAN_POINT('',(-4.564545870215,3.10498917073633,11.79));
#1148=LINE('',#1147,#1146);
#1149=EDGE_CURVE('E1638',#1142,#1132,#1148,.T.);
#1150=ORIENTED_EDGE('',*,*,#1149,.T.);
#1151=EDGE_LOOP('',(#1134,#1135,#1144,#1150));
#1152=FACE_BOUND('',#1151,.T.);
#1153=ADVANCED_FACE('F1818',(#1152),#1125,.T.);
#1154=CARTESIAN_POINT('',(-4.15839817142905,1.85649005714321,11.79));
#1155=DIRECTION('',(0.,0.,1.));
#1156=DIRECTION('',(1.,0.,0.));
#1157=AXIS2_PLACEMENT_3D('',#1154,#1155,#1156);
#1158=CYLINDRICAL_SURFACE('',#1157,1.31289983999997);
#1159=CARTESIAN_POINT('',(-4.15839817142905,1.85649005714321,11.8));
#1160=DIRECTION('',(0.,0.,1.));
#1161=DIRECTION('',(1.,0.,0.));
#1162=AXIS2_PLACEMENT_3D('',#1159,#1160,#1161);
#1163=CIRCLE('',#1162,1.31289983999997);
#1164=CARTESIAN_POINT('',(-3.40007945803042,2.92824502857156,11.8));
#1165=VERTEX_POINT('',#1164);
#1166=CARTESIAN_POINT('',(-3.99763492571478,3.15951007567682,11.8));
#1167=VERTEX_POINT('',#1166);
#1168=EDGE_CURVE('E1519',#1165,#1167,#1163,.T.);
#1169=ORIENTED_EDGE('',*,*,#1168,.F.);
#1170=DIRECTION('',(0.,0.,1.));
#1171=VECTOR('',#1170,1.);
#1172=CARTESIAN_POINT('',(-3.40007945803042,2.92824502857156,11.79));
#1173=LINE('',#1172,#1171);
#1174=CARTESIAN_POINT('',(-3.40007945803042,2.92824502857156,11.79));
#1175=VERTEX_POINT('',#1174);
#1176=EDGE_CURVE('E1647',#1175,#1165,#1173,.T.);
#1177=ORIENTED_EDGE('',*,*,#1176,.F.);
#1178=CARTESIAN_POINT('',(-4.15839817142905,1.85649005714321,11.79));
#1179=DIRECTION('',(0.,0.,1.));
#1180=DIRECTION('',(1.,0.,0.));
#1181=AXIS2_PLACEMENT_3D('',#1178,#1179,#1180);
#1182=CIRCLE('',#1181,1.31289983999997);
#1183=CARTESIAN_POINT('',(-3.99763492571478,3.15951007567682,11.79));
#1184=VERTEX_POINT('',#1183);
#1185=EDGE_CURVE('E1391',#1175,#1184,#1182,.T.);
#1186=ORIENTED_EDGE('',*,*,#1185,.T.);
#1187=DIRECTION('',(0.,0.,1.));
#1188=VECTOR('',#1187,1.);
#1189=CARTESIAN_POINT('',(-3.99763492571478,3.15951007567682,11.79));
#1190=LINE('',#1189,#1188);
#1191=EDGE_CURVE('E1643',#1184,#1167,#1190,.T.);
#1192=ORIENTED_EDGE('',*,*,#1191,.T.);
#1193=EDGE_LOOP('',(#1169,#1177,#1186,#1192));
#1194=FACE_BOUND('',#1193,.T.);
#1195=ADVANCED_FACE('F1801',(#1194),#1158,.T.);
#1196=CARTESIAN_POINT('',(-3.99763492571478,4.,11.79));
#1197=DIRECTION('',(1.,0.,0.));
#1198=DIRECTION('',(0.,0.,-1.));
#1199=AXIS2_PLACEMENT_3D('',#1196,#1197,#1198);
#1200=PLANE('',#1199);
#1201=DIRECTION('',(0.,1.,0.));
#1202=VECTOR('',#1201,1.);
#1203=CARTESIAN_POINT('',(-3.99763492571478,4.,11.8));
#1204=LINE('',#1203,#1202);
#1205=CARTESIAN_POINT('',(-3.99763492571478,2.69697998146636,11.8));
#1206=VERTEX_POINT('',#1205);
#1207=EDGE_CURVE('E1525',#1206,#1167,#1204,.T.);
#1208=ORIENTED_EDGE('',*,*,#1207,.T.);
#1209=ORIENTED_EDGE('',*,*,#1191,.F.);
#1210=DIRECTION('',(0.,1.,0.));
#1211=VECTOR('',#1210,1.);
#1212=CARTESIAN_POINT('',(-3.99763492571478,4.,11.79));
#1213=LINE('',#1212,#1211);
#1214=CARTESIAN_POINT('',(-3.99763492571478,2.69697998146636,11.79));
#1215=VERTEX_POINT('',#1214);
#1216=EDGE_CURVE('E1395',#1215,#1184,#1213,.T.);
#1217=ORIENTED_EDGE('',*,*,#1216,.F.);
#1218=DIRECTION('',(0.,0.,1.));
#1219=VECTOR('',#1218,1.);
#1220=CARTESIAN_POINT('',(-3.99763492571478,2.69697998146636,11.79));
#1221=LINE('',#1220,#1219);
#1222=EDGE_CURVE('E1645',#1215,#1206,#1221,.T.);
#1223=ORIENTED_EDGE('',*,*,#1222,.T.);
#1224=EDGE_LOOP('',(#1208,#1209,#1217,#1223));
#1225=FACE_BOUND('',#1224,.T.);
#1226=ADVANCED_FACE('F1807',(#1225),#1200,.F.);
#1227=CARTESIAN_POINT('',(-4.15839817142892,4.,11.79));
#1228=DIRECTION('',(0.,0.,1.));
#1229=DIRECTION('',(1.,0.,0.));
#1230=AXIS2_PLACEMENT_3D('',#1227,#1228,#1229);
#1231=CYLINDRICAL_SURFACE('',#1230,1.31289983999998);
#1232=ORIENTED_EDGE('',*,*,#300,.F.);
#1233=DIRECTION('',(0.,0.,1.));
#1234=VECTOR('',#1233,1.);
#1235=CARTESIAN_POINT('',(-5.14080342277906,4.8709683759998,11.79));
#1236=LINE('',#1235,#1234);
#1237=CARTESIAN_POINT('',(-5.14080342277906,4.8709683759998,11.79));
#1238=VERTEX_POINT('',#1237);
#1239=EDGE_CURVE('E1453',#1238,#288,#1236,.T.);
#1240=ORIENTED_EDGE('',*,*,#1239,.F.);
#1241=CARTESIAN_POINT('',(-4.15839817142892,4.,11.79));
#1242=DIRECTION('',(0.,0.,1.));
#1243=DIRECTION('',(1.,0.,0.));
#1244=AXIS2_PLACEMENT_3D('',#1241,#1242,#1243);
#1245=CIRCLE('',#1244,1.31289983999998);
#1246=CARTESIAN_POINT('',(-5.4712980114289,4.,11.79));
#1247=VERTEX_POINT('',#1246);
#1248=EDGE_CURVE('E1331',#1238,#1247,#1245,.T.);
#1249=ORIENTED_EDGE('',*,*,#1248,.T.);
#1250=DIRECTION('',(0.,0.,1.));
#1251=VECTOR('',#1250,1.);
#1252=CARTESIAN_POINT('',(-5.4712980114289,4.,11.79));
#1253=LINE('',#1252,#1251);
#1254=EDGE_CURVE('E1650',#1247,#299,#1253,.T.);
#1255=ORIENTED_EDGE('',*,*,#1254,.T.);
#1256=EDGE_LOOP('',(#1232,#1240,#1249,#1255));
#1257=FACE_BOUND('',#1256,.T.);
#1258=ADVANCED_FACE('F1809',(#1257),#1231,.T.);
#1259=CARTESIAN_POINT('',(-5.9,4.,11.79));
#1260=DIRECTION('',(0.,0.,1.));
#1261=DIRECTION('',(1.,0.,0.));
#1262=AXIS2_PLACEMENT_3D('',#1259,#1260,#1261);
#1263=CYLINDRICAL_SURFACE('',#1262,0.428701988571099);
#1264=ORIENTED_EDGE('',*,*,#309,.T.);
#1265=ORIENTED_EDGE('',*,*,#1254,.F.);
#1266=CARTESIAN_POINT('',(-5.9,4.,11.79));
#1267=DIRECTION('',(0.,0.,1.));
#1268=DIRECTION('',(1.,0.,0.));
#1269=AXIS2_PLACEMENT_3D('',#1266,#1267,#1268);
#1270=CIRCLE('',#1269,0.428701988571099);
#1271=CARTESIAN_POINT('',(-6.3287019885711,4.,11.79));
#1272=VERTEX_POINT('',#1271);
#1273=EDGE_CURVE('E1388',#1272,#1247,#1270,.T.);
#1274=ORIENTED_EDGE('',*,*,#1273,.F.);
#1275=DIRECTION('',(0.,0.,1.));
#1276=VECTOR('',#1275,1.);
#1277=CARTESIAN_POINT('',(-6.3287019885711,4.,11.79));
#1278=LINE('',#1277,#1276);
#1279=EDGE_CURVE('E1652',#1272,#308,#1278,.T.);
#1280=ORIENTED_EDGE('',*,*,#1279,.T.);
#1281=EDGE_LOOP('',(#1264,#1265,#1274,#1280));
#1282=FACE_BOUND('',#1281,.T.);
#1283=ADVANCED_FACE('F1816',(#1282),#1263,.F.);
#1284=CARTESIAN_POINT('',(-6.3287019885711,4.,11.79));
#1285=DIRECTION('',(-1.,0.,0.));
#1286=DIRECTION('',(0.,0.,1.));
#1287=AXIS2_PLACEMENT_3D('',#1284,#1285,#1286);
#1288=PLANE('',#1287);
#1289=ORIENTED_EDGE('',*,*,#317,.T.);
#1290=ORIENTED_EDGE('',*,*,#1279,.F.);
#1291=DIRECTION('',(0.,-1.,0.));
#1292=VECTOR('',#1291,1.);
#1293=CARTESIAN_POINT('',(-6.3287019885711,4.,11.79));
#1294=LINE('',#1293,#1292);
#1295=CARTESIAN_POINT('',(-6.3287019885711,4.16076324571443,11.79));
#1296=VERTEX_POINT('',#1295);
#1297=EDGE_CURVE('E1385',#1296,#1272,#1294,.T.);
#1298=ORIENTED_EDGE('',*,*,#1297,.F.);
#1299=DIRECTION('',(0.,0.,1.));
#1300=VECTOR('',#1299,1.);
#1301=CARTESIAN_POINT('',(-6.3287019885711,4.16076324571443,11.79));
#1302=LINE('',#1301,#1300);
#1303=EDGE_CURVE('E1654',#1296,#316,#1302,.T.);
#1304=ORIENTED_EDGE('',*,*,#1303,.T.);
#1305=EDGE_LOOP('',(#1289,#1290,#1298,#1304));
#1306=FACE_BOUND('',#1305,.T.);
#1307=ADVANCED_FACE('F1830',(#1306),#1288,.F.);
#1308=CARTESIAN_POINT('',(-5.9,4.16076324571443,11.79));
#1309=DIRECTION('',(0.,-1.,0.));
#1310=DIRECTION('',(0.,0.,-1.));
#1311=AXIS2_PLACEMENT_3D('',#1308,#1309,#1310);
#1312=PLANE('',#1311);
#1313=ORIENTED_EDGE('',*,*,#325,.T.);
#1314=ORIENTED_EDGE('',*,*,#1303,.F.);
#1315=DIRECTION('',(1.,0.,0.));
#1316=VECTOR('',#1315,1.);
#1317=CARTESIAN_POINT('',(-5.9,4.16076324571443,11.79));
#1318=LINE('',#1317,#1316);
#1319=CARTESIAN_POINT('',(-6.62343460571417,4.16076324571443,11.79));
#1320=VERTEX_POINT('',#1319);
#1321=EDGE_CURVE('E1382',#1320,#1296,#1318,.T.);
#1322=ORIENTED_EDGE('',*,*,#1321,.F.);
#1323=DIRECTION('',(0.,0.,1.));
#1324=VECTOR('',#1323,1.);
#1325=CARTESIAN_POINT('',(-6.62343460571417,4.16076324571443,11.79));
#1326=LINE('',#1325,#1324);
#1327=EDGE_CURVE('E1656',#1320,#324,#1326,.T.);
#1328=ORIENTED_EDGE('',*,*,#1327,.T.);
#1329=EDGE_LOOP('',(#1313,#1314,#1322,#1328));
#1330=FACE_BOUND('',#1329,.T.);
#1331=ADVANCED_FACE('F1834',(#1330),#1312,.F.);
#1332=CARTESIAN_POINT('',(-6.62343460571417,4.,11.79));
#1333=DIRECTION('',(1.,0.,0.));
#1334=DIRECTION('',(0.,0.,-1.));
#1335=AXIS2_PLACEMENT_3D('',#1332,#1333,#1334);
#1336=PLANE('',#1335);
#1337=ORIENTED_EDGE('',*,*,#333,.T.);
#1338=ORIENTED_EDGE('',*,*,#1327,.F.);
#1339=DIRECTION('',(0.,1.,0.));
#1340=VECTOR('',#1339,1.);
#1341=CARTESIAN_POINT('',(-6.62343460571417,4.,11.79));
#1342=LINE('',#1341,#1340);
#1343=CARTESIAN_POINT('',(-6.62343460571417,4.,11.79));
#1344=VERTEX_POINT('',#1343);
#1345=EDGE_CURVE('E1379',#1344,#1320,#1342,.T.);
#1346=ORIENTED_EDGE('',*,*,#1345,.F.);
#1347=DIRECTION('',(0.,0.,1.));
#1348=VECTOR('',#1347,1.);
#1349=CARTESIAN_POINT('',(-6.62343460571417,4.,11.79));
#1350=LINE('',#1349,#1348);
#1351=EDGE_CURVE('E1658',#1344,#332,#1350,.T.);
#1352=ORIENTED_EDGE('',*,*,#1351,.T.);
#1353=EDGE_LOOP('',(#1337,#1338,#1346,#1352));
#1354=FACE_BOUND('',#1353,.T.);
#1355=ADVANCED_FACE('F1838',(#1354),#1336,.F.);
#1356=CARTESIAN_POINT('',(-5.9,4.,11.79));
#1357=DIRECTION('',(0.,0.,1.));
#1358=DIRECTION('',(1.,0.,0.));
#1359=AXIS2_PLACEMENT_3D('',#1356,#1357,#1358);
#1360=CYLINDRICAL_SURFACE('',#1359,0.723434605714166);
#1361=ORIENTED_EDGE('',*,*,#342,.F.);
#1362=ORIENTED_EDGE('',*,*,#1351,.F.);
#1363=CARTESIAN_POINT('',(-5.9,4.,11.79));
#1364=DIRECTION('',(0.,0.,1.));
#1365=DIRECTION('',(1.,0.,0.));
#1366=AXIS2_PLACEMENT_3D('',#1363,#1364,#1365);
#1367=CIRCLE('',#1366,0.723434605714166);
#1368=CARTESIAN_POINT('',(-6.06076324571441,3.29465412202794,11.79));
#1369=VERTEX_POINT('',#1368);
#1370=EDGE_CURVE('E1377',#1344,#1369,#1367,.T.);
#1371=ORIENTED_EDGE('',*,*,#1370,.T.);
#1372=DIRECTION('',(0.,0.,1.));
#1373=VECTOR('',#1372,1.);
#1374=CARTESIAN_POINT('',(-6.06076324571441,3.29465412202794,11.79));
#1375=LINE('',#1374,#1373);
#1376=EDGE_CURVE('E1660',#1369,#341,#1375,.T.);
#1377=ORIENTED_EDGE('',*,*,#1376,.T.);
#1378=EDGE_LOOP('',(#1361,#1362,#1371,#1377));
#1379=FACE_BOUND('',#1378,.T.);
#1380=ADVANCED_FACE('F1842',(#1379),#1360,.T.);
#1381=CARTESIAN_POINT('',(-6.06076324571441,4.,11.79));
#1382=DIRECTION('',(1.,0.,0.));
#1383=DIRECTION('',(0.,0.,-1.));
#1384=AXIS2_PLACEMENT_3D('',#1381,#1382,#1383);
#1385=PLANE('',#1384);
#1386=ORIENTED_EDGE('',*,*,#350,.T.);
#1387=ORIENTED_EDGE('',*,*,#1376,.F.);
#1388=DIRECTION('',(0.,1.,0.));
#1389=VECTOR('',#1388,1.);
#1390=CARTESIAN_POINT('',(-6.06076324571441,4.,11.79));
#1391=LINE('',#1390,#1389);
#1392=CARTESIAN_POINT('',(-6.06076324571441,2.99460471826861,11.79));
#1393=VERTEX_POINT('',#1392);
#1394=EDGE_CURVE('E1374',#1393,#1369,#1391,.T.);
#1395=ORIENTED_EDGE('',*,*,#1394,.F.);
#1396=DIRECTION('',(0.,0.,1.));
#1397=VECTOR('',#1396,1.);
#1398=CARTESIAN_POINT('',(-6.06076324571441,2.99460471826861,11.79));
#1399=LINE('',#1398,#1397);
#1400=EDGE_CURVE('E1662',#1393,#349,#1399,.T.);
#1401=ORIENTED_EDGE('',*,*,#1400,.T.);
#1402=EDGE_LOOP('',(#1386,#1387,#1395,#1401));
#1403=FACE_BOUND('',#1402,.T.);
#1404=ADVANCED_FACE('F1846',(#1403),#1385,.F.);
#1405=CARTESIAN_POINT('',(-5.9,4.,11.79));
#1406=DIRECTION('',(0.,0.,1.));
#1407=DIRECTION('',(1.,0.,0.));
#1408=AXIS2_PLACEMENT_3D('',#1405,#1406,#1407);
#1409=CYLINDRICAL_SURFACE('',#1408,1.01816722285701);
#1410=ORIENTED_EDGE('',*,*,#359,.T.);
#1411=ORIENTED_EDGE('',*,*,#1400,.F.);
#1412=CARTESIAN_POINT('',(-5.9,4.,11.79));
#1413=DIRECTION('',(0.,0.,1.));
#1414=DIRECTION('',(1.,0.,0.));
#1415=AXIS2_PLACEMENT_3D('',#1412,#1413,#1414);
#1416=CIRCLE('',#1415,1.01816722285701);
#1417=CARTESIAN_POINT('',(-6.91816722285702,4.,11.79));
#1418=VERTEX_POINT('',#1417);
#1419=EDGE_CURVE('E1371',#1418,#1393,#1416,.T.);
#1420=ORIENTED_EDGE('',*,*,#1419,.F.);
#1421=DIRECTION('',(0.,0.,1.));
#1422=VECTOR('',#1421,1.);
#1423=CARTESIAN_POINT('',(-6.91816722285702,4.,11.79));
#1424=LINE('',#1423,#1422);
#1425=EDGE_CURVE('E1664',#1418,#358,#1424,.T.);
#1426=ORIENTED_EDGE('',*,*,#1425,.T.);
#1427=EDGE_LOOP('',(#1410,#1411,#1420,#1426));
#1428=FACE_BOUND('',#1427,.T.);
#1429=ADVANCED_FACE('F1850',(#1428),#1409,.F.);
#1430=CARTESIAN_POINT('',(-6.91816722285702,4.,11.79));
#1431=DIRECTION('',(-1.,0.,0.));
#1432=DIRECTION('',(0.,0.,1.));
#1433=AXIS2_PLACEMENT_3D('',#1430,#1431,#1432);
#1434=PLANE('',#1433);
#1435=ORIENTED_EDGE('',*,*,#367,.T.);
#1436=ORIENTED_EDGE('',*,*,#1425,.F.);
#1437=DIRECTION('',(0.,-1.,0.));
#1438=VECTOR('',#1437,1.);
#1439=CARTESIAN_POINT('',(-6.91816722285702,4.,11.79));
#1440=LINE('',#1439,#1438);
#1441=CARTESIAN_POINT('',(-6.91816722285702,4.16076324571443,11.79));
#1442=VERTEX_POINT('',#1441);
#1443=EDGE_CURVE('E1368',#1442,#1418,#1440,.T.);
#1444=ORIENTED_EDGE('',*,*,#1443,.F.);
#1445=DIRECTION('',(0.,0.,1.));
#1446=VECTOR('',#1445,1.);
#1447=CARTESIAN_POINT('',(-6.91816722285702,4.16076324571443,11.79));
#1448=LINE('',#1447,#1446);
#1449=EDGE_CURVE('E1666',#1442,#366,#1448,.T.);
#1450=ORIENTED_EDGE('',*,*,#1449,.T.);
#1451=EDGE_LOOP('',(#1435,#1436,#1444,#1450));
#1452=FACE_BOUND('',#1451,.T.);
#1453=ADVANCED_FACE('F1854',(#1452),#1434,.F.);
#1454=CARTESIAN_POINT('',(-5.9,4.16076324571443,11.79));
#1455=DIRECTION('',(0.,-1.,0.));
#1456=DIRECTION('',(0.,0.,-1.));
#1457=AXIS2_PLACEMENT_3D('',#1454,#1455,#1456);
#1458=PLANE('',#1457);
#1459=ORIENTED_EDGE('',*,*,#375,.T.);
#1460=ORIENTED_EDGE('',*,*,#1449,.F.);
#1461=DIRECTION('',(1.,0.,0.));
#1462=VECTOR('',#1461,1.);
#1463=CARTESIAN_POINT('',(-5.9,4.16076324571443,11.79));
#1464=LINE('',#1463,#1462);
#1465=CARTESIAN_POINT('',(-7.21289983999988,4.16076324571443,11.79));
#1466=VERTEX_POINT('',#1465);
#1467=EDGE_CURVE('E1365',#1466,#1442,#1464,.T.);
#1468=ORIENTED_EDGE('',*,*,#1467,.F.);
#1469=DIRECTION('',(0.,0.,1.));
#1470=VECTOR('',#1469,1.);
#1471=CARTESIAN_POINT('',(-7.21289983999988,4.16076324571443,11.79));
#1472=LINE('',#1471,#1470);
#1473=EDGE_CURVE('E1668',#1466,#374,#1472,.T.);
#1474=ORIENTED_EDGE('',*,*,#1473,.T.);
#1475=EDGE_LOOP('',(#1459,#1460,#1468,#1474));
#1476=FACE_BOUND('',#1475,.T.);
#1477=ADVANCED_FACE('F1858',(#1476),#1458,.F.);
#1478=CARTESIAN_POINT('',(-7.21289983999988,4.,11.79));
#1479=DIRECTION('',(1.,0.,0.));
#1480=DIRECTION('',(0.,0.,-1.));
#1481=AXIS2_PLACEMENT_3D('',#1478,#1479,#1480);
#1482=PLANE('',#1481);
#1483=ORIENTED_EDGE('',*,*,#383,.T.);
#1484=ORIENTED_EDGE('',*,*,#1473,.F.);
#1485=DIRECTION('',(0.,1.,0.));
#1486=VECTOR('',#1485,1.);
#1487=CARTESIAN_POINT('',(-7.21289983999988,4.,11.79));
#1488=LINE('',#1487,#1486);
#1489=CARTESIAN_POINT('',(-7.21289983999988,3.99999999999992,11.79));
#1490=VERTEX_POINT('',#1489);
#1491=EDGE_CURVE('E1362',#1490,#1466,#1488,.T.);
#1492=ORIENTED_EDGE('',*,*,#1491,.F.);
#1493=DIRECTION('',(0.,0.,1.));
#1494=VECTOR('',#1493,1.);
#1495=CARTESIAN_POINT('',(-7.21289983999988,3.99999999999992,11.79));
#1496=LINE('',#1495,#1494);
#1497=EDGE_CURVE('E1670',#1490,#382,#1496,.T.);
#1498=ORIENTED_EDGE('',*,*,#1497,.T.);
#1499=EDGE_LOOP('',(#1483,#1484,#1492,#1498));
#1500=FACE_BOUND('',#1499,.T.);
#1501=ADVANCED_FACE('F1862',(#1500),#1482,.F.);
#1502=CARTESIAN_POINT('',(-5.9,4.,11.79));
#1503=DIRECTION('',(0.,0.,1.));
#1504=DIRECTION('',(1.,0.,0.));
#1505=AXIS2_PLACEMENT_3D('',#1502,#1503,#1504);
#1506=CYLINDRICAL_SURFACE('',#1505,1.31289983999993);
#1507=ORIENTED_EDGE('',*,*,#392,.F.);
#1508=ORIENTED_EDGE('',*,*,#1497,.F.);
#1509=CARTESIAN_POINT('',(-5.9,4.,11.79));
#1510=DIRECTION('',(0.,0.,1.));
#1511=DIRECTION('',(1.,0.,0.));
#1512=AXIS2_PLACEMENT_3D('',#1509,#1510,#1511);
#1513=CIRCLE('',#1512,1.31289983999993);
#1514=CARTESIAN_POINT('',(-6.06076324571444,2.69697998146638,11.79));
#1515=VERTEX_POINT('',#1514);
#1516=EDGE_CURVE('E1360',#1490,#1515,#1513,.T.);
#1517=ORIENTED_EDGE('',*,*,#1516,.T.);
#1518=DIRECTION('',(0.,0.,1.));
#1519=VECTOR('',#1518,1.);
#1520=CARTESIAN_POINT('',(-6.06076324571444,2.69697998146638,11.79));
#1521=LINE('',#1520,#1519);
#1522=EDGE_CURVE('E1672',#1515,#391,#1521,.T.);
#1523=ORIENTED_EDGE('',*,*,#1522,.T.);
#1524=EDGE_LOOP('',(#1507,#1508,#1517,#1523));
#1525=FACE_BOUND('',#1524,.T.);
#1526=ADVANCED_FACE('F1866',(#1525),#1506,.T.);
#1527=CARTESIAN_POINT('',(-6.06076324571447,4.,11.79));
#1528=DIRECTION('',(1.,0.,0.));
#1529=DIRECTION('',(0.,1.,0.));
#1530=AXIS2_PLACEMENT_3D('',#1527,#1528,#1529);
#1531=PLANE('',#1530);
#1532=ORIENTED_EDGE('',*,*,#400,.T.);
#1533=ORIENTED_EDGE('',*,*,#1522,.F.);
#1534=DIRECTION('',(0.,1.,0.));
#1535=VECTOR('',#1534,1.);
#1536=CARTESIAN_POINT('',(-6.06076324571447,4.,11.79));
#1537=LINE('',#1536,#1535);
#1538=CARTESIAN_POINT('',(-6.06076324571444,2.40042590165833,11.79));
#1539=VERTEX_POINT('',#1538);
#1540=EDGE_CURVE('E1357',#1539,#1515,#1537,.T.);
#1541=ORIENTED_EDGE('',*,*,#1540,.F.);
#1542=DIRECTION('',(0.,0.,1.));
#1543=VECTOR('',#1542,1.);
#1544=CARTESIAN_POINT('',(-6.06076324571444,2.40042590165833,11.79));
#1545=LINE('',#1544,#1543);
#1546=EDGE_CURVE('E1674',#1539,#399,#1545,.T.);
#1547=ORIENTED_EDGE('',*,*,#1546,.T.);
#1548=EDGE_LOOP('',(#1532,#1533,#1541,#1547));
#1549=FACE_BOUND('',#1548,.T.);
#1550=ADVANCED_FACE('F1870',(#1549),#1531,.F.);
#1551=CARTESIAN_POINT('',(-5.9,4.,11.79));
#1552=DIRECTION('',(0.,0.,1.));
#1553=DIRECTION('',(1.,0.,0.));
#1554=AXIS2_PLACEMENT_3D('',#1551,#1552,#1553);
#1555=CYLINDRICAL_SURFACE('',#1554,1.60763245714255);
#1556=ORIENTED_EDGE('',*,*,#409,.T.);
#1557=ORIENTED_EDGE('',*,*,#1546,.F.);
#1558=CARTESIAN_POINT('',(-5.9,4.,11.79));
#1559=DIRECTION('',(0.,0.,1.));
#1560=DIRECTION('',(1.,0.,0.));
#1561=AXIS2_PLACEMENT_3D('',#1558,#1559,#1560);
#1562=CIRCLE('',#1561,1.60763245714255);
#1563=CARTESIAN_POINT('',(-5.02919908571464,5.35136519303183,11.79));
#1564=VERTEX_POINT('',#1563);
#1565=EDGE_CURVE('E1354',#1564,#1539,#1562,.T.);
#1566=ORIENTED_EDGE('',*,*,#1565,.F.);
#1567=DIRECTION('',(0.,0.,1.));
#1568=VECTOR('',#1567,1.);
#1569=CARTESIAN_POINT('',(-5.02919908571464,5.35136519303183,11.79));
#1570=LINE('',#1569,#1568);
#1571=EDGE_CURVE('E1676',#1564,#408,#1570,.T.);
#1572=ORIENTED_EDGE('',*,*,#1571,.T.);
#1573=EDGE_LOOP('',(#1556,#1557,#1566,#1572));
#1574=FACE_BOUND('',#1573,.T.);
#1575=ADVANCED_FACE('F1874',(#1574),#1555,.F.);
#1576=CARTESIAN_POINT('',(-4.15839817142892,4.,11.79));
#1577=DIRECTION('',(0.,0.,1.));
#1578=DIRECTION('',(1.,0.,0.));
#1579=AXIS2_PLACEMENT_3D('',#1576,#1577,#1578);
#1580=CYLINDRICAL_SURFACE('',#1579,1.60763245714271);
#1581=ORIENTED_EDGE('',*,*,#418,.T.);
#1582=ORIENTED_EDGE('',*,*,#1571,.F.);
#1583=CARTESIAN_POINT('',(-4.15839817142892,4.,11.79));
#1584=DIRECTION('',(0.,0.,1.));
#1585=DIRECTION('',(1.,0.,0.));
#1586=AXIS2_PLACEMENT_3D('',#1583,#1584,#1585);
#1587=CIRCLE('',#1586,1.60763245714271);
#1588=CARTESIAN_POINT('',(-5.02919908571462,2.64863480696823,11.79));
#1589=VERTEX_POINT('',#1588);
#1590=EDGE_CURVE('E1351',#1589,#1564,#1587,.T.);
#1591=ORIENTED_EDGE('',*,*,#1590,.F.);
#1592=DIRECTION('',(0.,0.,1.));
#1593=VECTOR('',#1592,1.);
#1594=CARTESIAN_POINT('',(-5.02919908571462,2.64863480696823,11.79));
#1595=LINE('',#1594,#1593);
#1596=EDGE_CURVE('E1678',#1589,#417,#1595,.T.);
#1597=ORIENTED_EDGE('',*,*,#1596,.T.);
#1598=EDGE_LOOP('',(#1581,#1582,#1591,#1597));
#1599=FACE_BOUND('',#1598,.T.);
#1600=ADVANCED_FACE('F1878',(#1599),#1580,.F.);
#1601=CARTESIAN_POINT('',(-5.9,4.,11.79));
#1602=DIRECTION('',(0.,0.,1.));
#1603=DIRECTION('',(1.,0.,0.));
#1604=AXIS2_PLACEMENT_3D('',#1601,#1602,#1603);
#1605=CYLINDRICAL_SURFACE('',#1604,1.60763245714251);
#1606=ORIENTED_EDGE('',*,*,#427,.T.);
#1607=ORIENTED_EDGE('',*,*,#1596,.F.);
#1608=CARTESIAN_POINT('',(-5.9,4.,11.79));
#1609=DIRECTION('',(0.,0.,1.));
#1610=DIRECTION('',(1.,0.,0.));
#1611=AXIS2_PLACEMENT_3D('',#1608,#1609,#1610);
#1612=CIRCLE('',#1611,1.60763245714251);
#1613=CARTESIAN_POINT('',(-5.73923675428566,2.40042590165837,11.79));
#1614=VERTEX_POINT('',#1613);
#1615=EDGE_CURVE('E1348',#1614,#1589,#1612,.T.);
#1616=ORIENTED_EDGE('',*,*,#1615,.F.);
#1617=DIRECTION('',(0.,0.,1.));
#1618=VECTOR('',#1617,1.);
#1619=CARTESIAN_POINT('',(-5.73923675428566,2.40042590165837,11.79));
#1620=LINE('',#1619,#1618);
#1621=EDGE_CURVE('E1680',#1614,#426,#1620,.T.);
#1622=ORIENTED_EDGE('',*,*,#1621,.T.);
#1623=EDGE_LOOP('',(#1606,#1607,#1616,#1622));
#1624=FACE_BOUND('',#1623,.T.);
#1625=ADVANCED_FACE('F1882',(#1624),#1605,.F.);
#1626=CARTESIAN_POINT('',(-5.73923675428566,4.,11.79));
#1627=DIRECTION('',(1.,0.,0.));
#1628=DIRECTION('',(0.,0.,-1.));
#1629=AXIS2_PLACEMENT_3D('',#1626,#1627,#1628);
#1630=PLANE('',#1629);
#1631=ORIENTED_EDGE('',*,*,#435,.F.);
#1632=ORIENTED_EDGE('',*,*,#1621,.F.);
#1633=DIRECTION('',(0.,1.,0.));
#1634=VECTOR('',#1633,1.);
#1635=CARTESIAN_POINT('',(-5.73923675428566,4.,11.79));
#1636=LINE('',#1635,#1634);
#1637=CARTESIAN_POINT('',(-5.73923675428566,2.69697998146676,11.79));
#1638=VERTEX_POINT('',#1637);
#1639=EDGE_CURVE('E1346',#1614,#1638,#1636,.T.);
#1640=ORIENTED_EDGE('',*,*,#1639,.T.);
#1641=DIRECTION('',(0.,0.,1.));
#1642=VECTOR('',#1641,1.);
#1643=CARTESIAN_POINT('',(-5.73923675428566,2.69697998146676,11.79));
#1644=LINE('',#1643,#1642);
#1645=EDGE_CURVE('E1682',#1638,#434,#1644,.T.);
#1646=ORIENTED_EDGE('',*,*,#1645,.T.);
#1647=EDGE_LOOP('',(#1631,#1632,#1640,#1646));
#1648=FACE_BOUND('',#1647,.T.);
#1649=ADVANCED_FACE('F1886',(#1648),#1630,.T.);
#1650=CARTESIAN_POINT('',(-5.9,4.,11.79));
#1651=DIRECTION('',(0.,0.,1.));
#1652=DIRECTION('',(1.,0.,0.));
#1653=AXIS2_PLACEMENT_3D('',#1650,#1651,#1652);
#1654=CYLINDRICAL_SURFACE('',#1653,1.3128998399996);
#1655=ORIENTED_EDGE('',*,*,#444,.F.);
#1656=ORIENTED_EDGE('',*,*,#1645,.F.);
#1657=CARTESIAN_POINT('',(-5.9,4.,11.79));
#1658=DIRECTION('',(0.,0.,1.));
#1659=DIRECTION('',(1.,0.,0.));
#1660=AXIS2_PLACEMENT_3D('',#1657,#1658,#1659);
#1661=CIRCLE('',#1660,1.3128998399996);
#1662=CARTESIAN_POINT('',(-4.58710016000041,4.,11.79));
#1663=VERTEX_POINT('',#1662);
#1664=EDGE_CURVE('E1344',#1638,#1663,#1661,.T.);
#1665=ORIENTED_EDGE('',*,*,#1664,.T.);
#1666=DIRECTION('',(0.,0.,1.));
#1667=VECTOR('',#1666,1.);
#1668=CARTESIAN_POINT('',(-4.58710016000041,4.,11.79));
#1669=LINE('',#1668,#1667);
#1670=EDGE_CURVE('E1684',#1663,#443,#1669,.T.);
#1671=ORIENTED_EDGE('',*,*,#1670,.T.);
#1672=EDGE_LOOP('',(#1655,#1656,#1665,#1671));
#1673=FACE_BOUND('',#1672,.T.);
#1674=ADVANCED_FACE('F1890',(#1673),#1654,.T.);
#1675=CARTESIAN_POINT('',(-4.58710016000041,4.,11.79));
#1676=DIRECTION('',(-1.,0.,0.));
#1677=DIRECTION('',(0.,0.,1.));
#1678=AXIS2_PLACEMENT_3D('',#1675,#1676,#1677);
#1679=PLANE('',#1678);
#1680=ORIENTED_EDGE('',*,*,#452,.T.);
#1681=ORIENTED_EDGE('',*,*,#1670,.F.);
#1682=DIRECTION('',(0.,-1.,0.));
#1683=VECTOR('',#1682,1.);
#1684=CARTESIAN_POINT('',(-4.58710016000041,4.,11.79));
#1685=LINE('',#1684,#1683);
#1686=CARTESIAN_POINT('',(-4.58710016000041,4.16076324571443,11.79));
#1687=VERTEX_POINT('',#1686);
#1688=EDGE_CURVE('E1341',#1687,#1663,#1685,.T.);
#1689=ORIENTED_EDGE('',*,*,#1688,.F.);
#1690=DIRECTION('',(0.,0.,1.));
#1691=VECTOR('',#1690,1.);
#1692=CARTESIAN_POINT('',(-4.58710016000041,4.16076324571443,11.79));
#1693=LINE('',#1692,#1691);
#1694=EDGE_CURVE('E1686',#1687,#451,#1693,.T.);
#1695=ORIENTED_EDGE('',*,*,#1694,.T.);
#1696=EDGE_LOOP('',(#1680,#1681,#1689,#1695));
#1697=FACE_BOUND('',#1696,.T.);
#1698=ADVANCED_FACE('F1894',(#1697),#1679,.F.);
#1699=CARTESIAN_POINT('',(-5.9,4.16076324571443,11.79));
#1700=DIRECTION('',(0.,-1.,0.));
#1701=DIRECTION('',(0.,0.,-1.));
#1702=AXIS2_PLACEMENT_3D('',#1699,#1700,#1701);
#1703=PLANE('',#1702);
#1704=ORIENTED_EDGE('',*,*,#460,.F.);
#1705=ORIENTED_EDGE('',*,*,#1694,.F.);
#1706=DIRECTION('',(1.,0.,0.));
#1707=VECTOR('',#1706,1.);
#1708=CARTESIAN_POINT('',(-5.9,4.16076324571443,11.79));
#1709=LINE('',#1708,#1707);
#1710=CARTESIAN_POINT('',(-4.31916141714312,4.16076324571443,11.79));
#1711=VERTEX_POINT('',#1710);
#1712=EDGE_CURVE('E1339',#1687,#1711,#1709,.T.);
#1713=ORIENTED_EDGE('',*,*,#1712,.T.);
#1714=DIRECTION('',(0.,0.,1.));
#1715=VECTOR('',#1714,1.);
#1716=CARTESIAN_POINT('',(-4.31916141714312,4.16076324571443,11.79));
#1717=LINE('',#1716,#1715);
#1718=EDGE_CURVE('E1688',#1711,#459,#1717,.T.);
#1719=ORIENTED_EDGE('',*,*,#1718,.T.);
#1720=EDGE_LOOP('',(#1704,#1705,#1713,#1719));
#1721=FACE_BOUND('',#1720,.T.);
#1722=ADVANCED_FACE('F1898',(#1721),#1703,.T.);
#1723=CARTESIAN_POINT('',(-4.31916141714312,4.,11.79));
#1724=DIRECTION('',(1.,0.,0.));
#1725=DIRECTION('',(0.,0.,-1.));
#1726=AXIS2_PLACEMENT_3D('',#1723,#1724,#1725);
#1727=PLANE('',#1726);
#1728=ORIENTED_EDGE('',*,*,#466,.F.);
#1729=ORIENTED_EDGE('',*,*,#1718,.F.);
#1730=DIRECTION('',(0.,1.,0.));
#1731=VECTOR('',#1730,1.);
#1732=CARTESIAN_POINT('',(-4.31916141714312,4.,11.79));
#1733=LINE('',#1732,#1731);
#1734=CARTESIAN_POINT('',(-4.31916141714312,4.54393584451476,11.79));
#1735=VERTEX_POINT('',#1734);
#1736=EDGE_CURVE('E1337',#1711,#1735,#1733,.T.);
#1737=ORIENTED_EDGE('',*,*,#1736,.T.);
#1738=DIRECTION('',(0.,0.,1.));
#1739=VECTOR('',#1738,1.);
#1740=CARTESIAN_POINT('',(-4.31916141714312,4.54393584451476,11.79));
#1741=LINE('',#1740,#1739);
#1742=EDGE_CURVE('E1690',#1735,#290,#1741,.T.);
#1743=ORIENTED_EDGE('',*,*,#1742,.T.);
#1744=EDGE_LOOP('',(#1728,#1729,#1737,#1743));
#1745=FACE_BOUND('',#1744,.T.);
#1746=ADVANCED_FACE('F1902',(#1745),#1727,.T.);
#1747=CARTESIAN_POINT('',(-4.15839817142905,1.85649005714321,11.79));
#1748=DIRECTION('',(0.,0.,1.));
#1749=DIRECTION('',(1.,0.,0.));
#1750=AXIS2_PLACEMENT_3D('',#1747,#1748,#1749);
#1751=CYLINDRICAL_SURFACE('',#1750,1.60763245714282);
#1752=CARTESIAN_POINT('',(-4.15839817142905,1.85649005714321,11.8));
#1753=DIRECTION('',(0.,0.,1.));
#1754=DIRECTION('',(1.,0.,0.));
#1755=AXIS2_PLACEMENT_3D('',#1752,#1753,#1754);
#1756=CIRCLE('',#1755,1.60763245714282);
#1757=EDGE_CURVE('E1570',#736,#808,#1756,.T.);
#1758=ORIENTED_EDGE('',*,*,#1757,.T.);
#1759=ORIENTED_EDGE('',*,*,#824,.F.);
#1760=CARTESIAN_POINT('',(-4.15839817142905,1.85649005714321,11.79));
#1761=DIRECTION('',(0.,0.,1.));
#1762=DIRECTION('',(1.,0.,0.));
#1763=AXIS2_PLACEMENT_3D('',#1760,#1761,#1762);
#1764=CIRCLE('',#1763,1.60763245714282);
#1765=EDGE_CURVE('E1433',#746,#817,#1764,.T.);
#1766=ORIENTED_EDGE('',*,*,#1765,.F.);
#1767=ORIENTED_EDGE('',*,*,#747,.T.);
#1768=EDGE_LOOP('',(#1758,#1759,#1766,#1767));
#1769=FACE_BOUND('',#1768,.T.);
#1770=ADVANCED_FACE('F1906',(#1769),#1751,.F.);
#1771=CARTESIAN_POINT('',(-4.15839817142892,4.,11.79));
#1772=DIRECTION('',(0.,0.,1.));
#1773=DIRECTION('',(1.,0.,0.));
#1774=AXIS2_PLACEMENT_3D('',#1771,#1772,#1773);
#1775=CYLINDRICAL_SURFACE('',#1774,1.31289984);
#1776=CARTESIAN_POINT('',(-4.15839817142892,4.,11.8));
#1777=DIRECTION('',(0.,0.,1.));
#1778=DIRECTION('',(1.,0.,0.));
#1779=AXIS2_PLACEMENT_3D('',#1776,#1777,#1778);
#1780=CIRCLE('',#1779,1.31289984);
#1781=EDGE_CURVE('E1561',#881,#840,#1780,.T.);
#1782=ORIENTED_EDGE('',*,*,#1781,.F.);
#1783=ORIENTED_EDGE('',*,*,#897,.F.);
#1784=CARTESIAN_POINT('',(-4.15839817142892,4.,11.79));
#1785=DIRECTION('',(0.,0.,1.));
#1786=DIRECTION('',(1.,0.,0.));
#1787=AXIS2_PLACEMENT_3D('',#1784,#1785,#1786);
#1788=CIRCLE('',#1787,1.31289984);
#1789=EDGE_CURVE('E1427',#890,#850,#1788,.T.);
#1790=ORIENTED_EDGE('',*,*,#1789,.T.);
#1791=ORIENTED_EDGE('',*,*,#851,.T.);
#1792=EDGE_LOOP('',(#1782,#1783,#1790,#1791));
#1793=FACE_BOUND('',#1792,.T.);
#1794=ADVANCED_FACE('F2161',(#1793),#1775,.T.);
#1795=CARTESIAN_POINT('',(-3.99763492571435,4.,11.79));
#1796=DIRECTION('',(1.,0.,0.));
#1797=DIRECTION('',(0.,0.,-1.));
#1798=AXIS2_PLACEMENT_3D('',#1795,#1796,#1797);
#1799=PLANE('',#1798);
#1800=DIRECTION('',(0.,1.,0.));
#1801=VECTOR('',#1800,1.);
#1802=CARTESIAN_POINT('',(-3.99763492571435,4.,11.8));
#1803=LINE('',#1802,#1801);
#1804=EDGE_CURVE('E1552',#913,#955,#1803,.T.);
#1805=ORIENTED_EDGE('',*,*,#1804,.T.);
#1806=ORIENTED_EDGE('',*,*,#972,.F.);
#1807=DIRECTION('',(0.,1.,0.));
#1808=VECTOR('',#1807,1.);
#1809=CARTESIAN_POINT('',(-3.99763492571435,4.,11.79));
#1810=LINE('',#1809,#1808);
#1811=EDGE_CURVE('E1419',#923,#965,#1810,.T.);
#1812=ORIENTED_EDGE('',*,*,#1811,.F.);
#1813=ORIENTED_EDGE('',*,*,#924,.T.);
#1814=EDGE_LOOP('',(#1805,#1806,#1812,#1813));
#1815=FACE_BOUND('',#1814,.T.);
#1816=ADVANCED_FACE('F2173',(#1815),#1799,.F.);
#1817=CARTESIAN_POINT('',(-5.9,4.,11.79));
#1818=DIRECTION('',(0.,0.,1.));
#1819=DIRECTION('',(1.,0.,0.));
#1820=AXIS2_PLACEMENT_3D('',#1817,#1818,#1819);
#1821=CYLINDRICAL_SURFACE('',#1820,1.60763245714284);
#1822=CARTESIAN_POINT('',(-5.9,4.,11.8));
#1823=DIRECTION('',(0.,0.,1.));
#1824=DIRECTION('',(1.,0.,0.));
#1825=AXIS2_PLACEMENT_3D('',#1822,#1823,#1824);
#1826=CIRCLE('',#1825,1.60763245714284);
#1827=EDGE_CURVE('E1543',#987,#1027,#1826,.T.);
#1828=ORIENTED_EDGE('',*,*,#1827,.T.);
#1829=ORIENTED_EDGE('',*,*,#1043,.F.);
#1830=CARTESIAN_POINT('',(-5.9,4.,11.79));
#1831=DIRECTION('',(0.,0.,1.));
#1832=DIRECTION('',(1.,0.,0.));
#1833=AXIS2_PLACEMENT_3D('',#1830,#1831,#1832);
#1834=CIRCLE('',#1833,1.60763245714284);
#1835=EDGE_CURVE('E1411',#997,#1036,#1834,.T.);
#1836=ORIENTED_EDGE('',*,*,#1835,.F.);
#1837=ORIENTED_EDGE('',*,*,#998,.T.);
#1838=EDGE_LOOP('',(#1828,#1829,#1836,#1837));
#1839=FACE_BOUND('',#1838,.T.);
#1840=ADVANCED_FACE('F2185',(#1839),#1821,.F.);
#1841=CARTESIAN_POINT('',(-5.9,4.,11.79));
#1842=DIRECTION('',(0.,0.,1.));
#1843=DIRECTION('',(1.,0.,0.));
#1844=AXIS2_PLACEMENT_3D('',#1841,#1842,#1843);
#1845=CYLINDRICAL_SURFACE('',#1844,1.60763245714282);
#1846=CARTESIAN_POINT('',(-5.9,4.,11.8));
#1847=DIRECTION('',(0.,0.,1.));
#1848=DIRECTION('',(1.,0.,0.));
#1849=AXIS2_PLACEMENT_3D('',#1846,#1847,#1848);
#1850=CIRCLE('',#1849,1.60763245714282);
#1851=EDGE_CURVE('E1531',#1059,#1132,#1850,.T.);
#1852=ORIENTED_EDGE('',*,*,#1851,.T.);
#1853=ORIENTED_EDGE('',*,*,#1149,.F.);
#1854=CARTESIAN_POINT('',(-5.9,4.,11.79));
#1855=DIRECTION('',(0.,0.,1.));
#1856=DIRECTION('',(1.,0.,0.));
#1857=AXIS2_PLACEMENT_3D('',#1854,#1855,#1856);
#1858=CIRCLE('',#1857,1.60763245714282);
#1859=EDGE_CURVE('E1401',#1069,#1142,#1858,.T.);
#1860=ORIENTED_EDGE('',*,*,#1859,.F.);
#1861=ORIENTED_EDGE('',*,*,#1070,.T.);
#1862=EDGE_LOOP('',(#1852,#1853,#1860,#1861));
#1863=FACE_BOUND('',#1862,.T.);
#1864=ADVANCED_FACE('F1826',(#1863),#1845,.F.);
#1865=CARTESIAN_POINT('',(-4.15839817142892,4.,11.79));
#1866=DIRECTION('',(0.,0.,1.));
#1867=DIRECTION('',(1.,0.,0.));
#1868=AXIS2_PLACEMENT_3D('',#1865,#1866,#1867);
#1869=CYLINDRICAL_SURFACE('',#1868,1.31289983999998);
#1870=CARTESIAN_POINT('',(-4.15839817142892,4.,11.8));
#1871=DIRECTION('',(0.,0.,1.));
#1872=DIRECTION('',(1.,0.,0.));
#1873=AXIS2_PLACEMENT_3D('',#1870,#1871,#1872);
#1874=CIRCLE('',#1873,1.31289983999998);
#1875=EDGE_CURVE('E1522',#1206,#1165,#1874,.T.);
#1876=ORIENTED_EDGE('',*,*,#1875,.F.);
#1877=ORIENTED_EDGE('',*,*,#1222,.F.);
#1878=CARTESIAN_POINT('',(-4.15839817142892,4.,11.79));
#1879=DIRECTION('',(0.,0.,1.));
#1880=DIRECTION('',(1.,0.,0.));
#1881=AXIS2_PLACEMENT_3D('',#1878,#1879,#1880);
#1882=CIRCLE('',#1881,1.31289983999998);
#1883=EDGE_CURVE('E1393',#1215,#1175,#1882,.T.);
#1884=ORIENTED_EDGE('',*,*,#1883,.T.);
#1885=ORIENTED_EDGE('',*,*,#1176,.T.);
#1886=EDGE_LOOP('',(#1876,#1877,#1884,#1885));
#1887=FACE_BOUND('',#1886,.T.);
#1888=ADVANCED_FACE('F1796',(#1887),#1869,.T.);
#1889=CARTESIAN_POINT('',(-4.15839817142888,6.14350994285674,11.79));
#1890=DIRECTION('',(0.,0.,1.));
#1891=DIRECTION('',(1.,0.,0.));
#1892=AXIS2_PLACEMENT_3D('',#1889,#1890,#1891);
#1893=CYLINDRICAL_SURFACE('',#1892,1.60763245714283);
#1894=ORIENTED_EDGE('',*,*,#291,.T.);
#1895=ORIENTED_EDGE('',*,*,#1742,.F.);
#1896=CARTESIAN_POINT('',(-4.15839817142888,6.14350994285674,11.79));
#1897=DIRECTION('',(0.,0.,1.));
#1898=DIRECTION('',(1.,0.,0.));
#1899=AXIS2_PLACEMENT_3D('',#1896,#1897,#1898);
#1900=CIRCLE('',#1899,1.60763245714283);
#1901=EDGE_CURVE('E1333',#1238,#1735,#1900,.T.);
#1902=ORIENTED_EDGE('',*,*,#1901,.F.);
#1903=ORIENTED_EDGE('',*,*,#1239,.T.);
#1904=EDGE_LOOP('',(#1894,#1895,#1902,#1903));
#1905=FACE_BOUND('',#1904,.T.);
#1906=ADVANCED_FACE('F1825',(#1905),#1893,.F.);
#1907=CARTESIAN_POINT('',(-4.15839817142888,6.14350994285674,11.79));
#1908=DIRECTION('',(0.,0.,1.));
#1909=DIRECTION('',(1.,0.,0.));
#1910=AXIS2_PLACEMENT_3D('',#1907,#1908,#1909);
#1911=CYLINDRICAL_SURFACE('',#1910,1.60763245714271);
#1912=CARTESIAN_POINT('',(-4.15839817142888,6.14350994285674,11.8));
#1913=DIRECTION('',(0.,0.,1.));
#1914=DIRECTION('',(1.,0.,0.));
#1915=AXIS2_PLACEMENT_3D('',#1912,#1913,#1914);
#1916=CIRCLE('',#1915,1.60763245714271);
#1917=EDGE_CURVE('E1581',#633,#703,#1916,.T.);
#1918=ORIENTED_EDGE('',*,*,#1917,.T.);
#1919=ORIENTED_EDGE('',*,*,#720,.F.);
#1920=CARTESIAN_POINT('',(-4.15839817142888,6.14350994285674,11.79));
#1921=DIRECTION('',(0.,0.,1.));
#1922=DIRECTION('',(1.,0.,0.));
#1923=AXIS2_PLACEMENT_3D('',#1920,#1921,#1922);
#1924=CIRCLE('',#1923,1.60763245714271);
#1925=EDGE_CURVE('E1445',#641,#713,#1924,.T.);
#1926=ORIENTED_EDGE('',*,*,#1925,.F.);
#1927=ORIENTED_EDGE('',*,*,#642,.T.);
#1928=EDGE_LOOP('',(#1918,#1919,#1926,#1927));
#1929=FACE_BOUND('',#1928,.T.);
#1930=ADVANCED_FACE('F1790',(#1929),#1911,.F.);
#1931=CARTESIAN_POINT('',(-5.9,4.,11.79));
#1932=DIRECTION('',(0.,0.,1.));
#1933=DIRECTION('',(1.,0.,0.));
#1934=AXIS2_PLACEMENT_3D('',#1931,#1932,#1933);
#1935=PLANE('',#1934);
#1936=ORIENTED_EDGE('',*,*,#1248,.F.);
#1937=ORIENTED_EDGE('',*,*,#1901,.T.);
#1938=ORIENTED_EDGE('',*,*,#1736,.F.);
#1939=ORIENTED_EDGE('',*,*,#1712,.F.);
#1940=ORIENTED_EDGE('',*,*,#1688,.T.);
#1941=ORIENTED_EDGE('',*,*,#1664,.F.);
#1942=ORIENTED_EDGE('',*,*,#1639,.F.);
#1943=ORIENTED_EDGE('',*,*,#1615,.T.);
#1944=ORIENTED_EDGE('',*,*,#1590,.T.);
#1945=ORIENTED_EDGE('',*,*,#1565,.T.);
#1946=ORIENTED_EDGE('',*,*,#1540,.T.);
#1947=ORIENTED_EDGE('',*,*,#1516,.F.);
#1948=ORIENTED_EDGE('',*,*,#1491,.T.);
#1949=ORIENTED_EDGE('',*,*,#1467,.T.);
#1950=ORIENTED_EDGE('',*,*,#1443,.T.);
#1951=ORIENTED_EDGE('',*,*,#1419,.T.);
#1952=ORIENTED_EDGE('',*,*,#1394,.T.);
#1953=ORIENTED_EDGE('',*,*,#1370,.F.);
#1954=ORIENTED_EDGE('',*,*,#1345,.T.);
#1955=ORIENTED_EDGE('',*,*,#1321,.T.);
#1956=ORIENTED_EDGE('',*,*,#1297,.T.);
#1957=ORIENTED_EDGE('',*,*,#1273,.T.);
#1958=EDGE_LOOP('',(#1936,#1937,#1938,#1939,#1940,#1941,#1942,#1943,#1944,#1945,#1946,#1947,
#1948,#1949,#1950,#1951,#1952,#1953,#1954,#1955,#1956,#1957));
#1959=FACE_BOUND('',#1958,.T.);
#1960=ORIENTED_EDGE('',*,*,#1185,.F.);
#1961=ORIENTED_EDGE('',*,*,#1883,.F.);
#1962=ORIENTED_EDGE('',*,*,#1216,.T.);
#1963=EDGE_LOOP('',(#1960,#1961,#1962));
#1964=FACE_BOUND('',#1963,.T.);
#1965=ORIENTED_EDGE('',*,*,#1079,.F.);
#1966=ORIENTED_EDGE('',*,*,#1859,.T.);
#1967=ORIENTED_EDGE('',*,*,#1143,.F.);
#1968=ORIENTED_EDGE('',*,*,#1110,.F.);
#1969=EDGE_LOOP('',(#1965,#1966,#1967,#1968));
#1970=FACE_BOUND('',#1969,.T.);
#1971=ORIENTED_EDGE('',*,*,#1006,.F.);
#1972=ORIENTED_EDGE('',*,*,#1835,.T.);
#1973=ORIENTED_EDGE('',*,*,#1037,.F.);
#1974=EDGE_LOOP('',(#1971,#1972,#1973));
#1975=FACE_BOUND('',#1974,.T.);
#1976=ORIENTED_EDGE('',*,*,#933,.F.);
#1977=ORIENTED_EDGE('',*,*,#1811,.T.);
#1978=ORIENTED_EDGE('',*,*,#966,.F.);
#1979=EDGE_LOOP('',(#1976,#1977,#1978));
#1980=FACE_BOUND('',#1979,.T.);
#1981=ORIENTED_EDGE('',*,*,#860,.F.);
#1982=ORIENTED_EDGE('',*,*,#1789,.F.);
#1983=ORIENTED_EDGE('',*,*,#891,.F.);
#1984=EDGE_LOOP('',(#1981,#1982,#1983));
#1985=FACE_BOUND('',#1984,.T.);
#1986=ORIENTED_EDGE('',*,*,#756,.F.);
#1987=ORIENTED_EDGE('',*,*,#1765,.T.);
#1988=ORIENTED_EDGE('',*,*,#818,.T.);
#1989=ORIENTED_EDGE('',*,*,#787,.T.);
#1990=EDGE_LOOP('',(#1986,#1987,#1988,#1989));
#1991=FACE_BOUND('',#1990,.T.);
#1992=ORIENTED_EDGE('',*,*,#650,.T.);
#1993=ORIENTED_EDGE('',*,*,#1925,.T.);
#1994=ORIENTED_EDGE('',*,*,#714,.F.);
#1995=ORIENTED_EDGE('',*,*,#681,.F.);
#1996=EDGE_LOOP('',(#1992,#1993,#1994,#1995));
#1997=FACE_BOUND('',#1996,.T.);
#1998=ADVANCED_FACE('F1781',(#1959,#1964,#1970,#1975,#1980,#1985,#1991,#1997),#1935,.T.);
#1999=ORIENTED_EDGE('',*,*,#1875,.T.);
#2000=ORIENTED_EDGE('',*,*,#1168,.T.);
#2001=ORIENTED_EDGE('',*,*,#1207,.F.);
#2002=EDGE_LOOP('',(#1999,#2000,#2001));
#2003=FACE_BOUND('',#2002,.T.);
#2004=ADVANCED_FACE('F1767',(#2003),#23,.T.);
#2005=ORIENTED_EDGE('',*,*,#1851,.F.);
#2006=ORIENTED_EDGE('',*,*,#1062,.T.);
#2007=ORIENTED_EDGE('',*,*,#1101,.T.);
#2008=ORIENTED_EDGE('',*,*,#1133,.T.);
#2009=EDGE_LOOP('',(#2005,#2006,#2007,#2008));
#2010=FACE_BOUND('',#2009,.T.);
#2011=ADVANCED_FACE('F1780',(#2010),#23,.T.);
#2012=ORIENTED_EDGE('',*,*,#1827,.F.);
#2013=ORIENTED_EDGE('',*,*,#990,.T.);
#2014=ORIENTED_EDGE('',*,*,#1028,.T.);
#2015=EDGE_LOOP('',(#2012,#2013,#2014));
#2016=FACE_BOUND('',#2015,.T.);
#2017=ADVANCED_FACE('F1788',(#2016),#23,.T.);
#2018=ORIENTED_EDGE('',*,*,#1804,.F.);
#2019=ORIENTED_EDGE('',*,*,#916,.T.);
#2020=ORIENTED_EDGE('',*,*,#956,.T.);
#2021=EDGE_LOOP('',(#2018,#2019,#2020));
#2022=FACE_BOUND('',#2021,.T.);
#2023=ADVANCED_FACE('F2811',(#2022),#23,.T.);
#2024=ORIENTED_EDGE('',*,*,#1781,.T.);
#2025=ORIENTED_EDGE('',*,*,#843,.T.);
#2026=ORIENTED_EDGE('',*,*,#882,.T.);
#2027=EDGE_LOOP('',(#2024,#2025,#2026));
#2028=FACE_BOUND('',#2027,.T.);
#2029=ADVANCED_FACE('F1776',(#2028),#23,.T.);
#2030=ORIENTED_EDGE('',*,*,#1757,.F.);
#2031=ORIENTED_EDGE('',*,*,#739,.T.);
#2032=ORIENTED_EDGE('',*,*,#778,.F.);
#2033=ORIENTED_EDGE('',*,*,#809,.F.);
#2034=EDGE_LOOP('',(#2030,#2031,#2032,#2033));
#2035=FACE_BOUND('',#2034,.T.);
#2036=ADVANCED_FACE('F1765',(#2035),#23,.T.);
#2037=ORIENTED_EDGE('',*,*,#634,.F.);
#2038=ORIENTED_EDGE('',*,*,#672,.T.);
#2039=ORIENTED_EDGE('',*,*,#704,.T.);
#2040=ORIENTED_EDGE('',*,*,#1917,.F.);
#2041=EDGE_LOOP('',(#2037,#2038,#2039,#2040));
#2042=FACE_BOUND('',#2041,.T.);
#2043=ADVANCED_FACE('F1750',(#2042),#23,.T.);
#2044=CARTESIAN_POINT('',(-5.9,2.74961920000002,11.79));
#2045=DIRECTION('',(0.,-1.,0.));
#2046=DIRECTION('',(0.,0.,-1.));
#2047=AXIS2_PLACEMENT_3D('',#2044,#2045,#2046);
#2048=PLANE('',#2047);
#2049=ORIENTED_EDGE('',*,*,#220,.T.);
#2050=DIRECTION('',(0.,0.,1.));
#2051=VECTOR('',#2050,1.);
#2052=CARTESIAN_POINT('',(-1.29294217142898,2.74961920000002,11.79));
#2053=LINE('',#2052,#2051);
#2054=CARTESIAN_POINT('',(-1.29294217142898,2.74961920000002,11.79));
#2055=VERTEX_POINT('',#2054);
#2056=EDGE_CURVE('E1299',#2055,#219,#2053,.T.);
#2057=ORIENTED_EDGE('',*,*,#2056,.F.);
#2058=DIRECTION('',(1.,0.,0.));
#2059=VECTOR('',#2058,1.);
#2060=CARTESIAN_POINT('',(-5.9,2.74961920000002,11.79));
#2061=LINE('',#2060,#2059);
#2062=CARTESIAN_POINT('',(-2.07443017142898,2.74961920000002,11.79));
#2063=VERTEX_POINT('',#2062);
#2064=EDGE_CURVE('E1312',#2063,#2055,#2061,.T.);
#2065=ORIENTED_EDGE('',*,*,#2064,.F.);
#2066=DIRECTION('',(0.,0.,1.));
#2067=VECTOR('',#2066,1.);
#2068=CARTESIAN_POINT('',(-2.07443017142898,2.74961920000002,11.79));
#2069=LINE('',#2068,#2067);
#2070=EDGE_CURVE('E1263',#2063,#217,#2069,.T.);
#2071=ORIENTED_EDGE('',*,*,#2070,.T.);
#2072=EDGE_LOOP('',(#2049,#2057,#2065,#2071));
#2073=FACE_BOUND('',#2072,.T.);
#2074=ADVANCED_FACE('F1764',(#2073),#2048,.F.);
#2075=CARTESIAN_POINT('',(-2.07443017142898,4.,11.79));
#2076=DIRECTION('',(-1.,0.,0.));
#2077=DIRECTION('',(0.,0.,1.));
#2078=AXIS2_PLACEMENT_3D('',#2075,#2076,#2077);
#2079=PLANE('',#2078);
#2080=ORIENTED_EDGE('',*,*,#228,.T.);
#2081=ORIENTED_EDGE('',*,*,#2070,.F.);
#2082=DIRECTION('',(0.,-1.,0.));
#2083=VECTOR('',#2082,1.);
#2084=CARTESIAN_POINT('',(-2.07443017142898,4.,11.79));
#2085=LINE('',#2084,#2083);
#2086=CARTESIAN_POINT('',(-2.07443017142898,5.25038080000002,11.79));
#2087=VERTEX_POINT('',#2086);
#2088=EDGE_CURVE('E1302',#2087,#2063,#2085,.T.);
#2089=ORIENTED_EDGE('',*,*,#2088,.F.);
#2090=DIRECTION('',(0.,0.,1.));
#2091=VECTOR('',#2090,1.);
#2092=CARTESIAN_POINT('',(-2.07443017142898,5.25038080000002,11.79));
#2093=LINE('',#2092,#2091);
#2094=EDGE_CURVE('E1305',#2087,#227,#2093,.T.);
#2095=ORIENTED_EDGE('',*,*,#2094,.T.);
#2096=EDGE_LOOP('',(#2080,#2081,#2089,#2095));
#2097=FACE_BOUND('',#2096,.T.);
#2098=ADVANCED_FACE('F1773',(#2097),#2079,.F.);
#2099=CARTESIAN_POINT('',(-5.9,5.25038080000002,11.79));
#2100=DIRECTION('',(0.,1.,0.));
#2101=DIRECTION('',(0.,0.,1.));
#2102=AXIS2_PLACEMENT_3D('',#2099,#2100,#2101);
#2103=PLANE('',#2102);
#2104=ORIENTED_EDGE('',*,*,#236,.T.);
#2105=ORIENTED_EDGE('',*,*,#2094,.F.);
#2106=DIRECTION('',(-1.,0.,0.));
#2107=VECTOR('',#2106,1.);
#2108=CARTESIAN_POINT('',(-5.9,5.25038080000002,11.79));
#2109=LINE('',#2108,#2107);
#2110=CARTESIAN_POINT('',(-1.29294217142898,5.25038080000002,11.79));
#2111=VERTEX_POINT('',#2110);
#2112=EDGE_CURVE('E1323',#2111,#2087,#2109,.T.);
#2113=ORIENTED_EDGE('',*,*,#2112,.F.);
#2114=DIRECTION('',(0.,0.,1.));
#2115=VECTOR('',#2114,1.);
#2116=CARTESIAN_POINT('',(-1.29294217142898,5.25038080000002,11.79));
#2117=LINE('',#2116,#2115);
#2118=EDGE_CURVE('E1303',#2111,#235,#2117,.T.);
#2119=ORIENTED_EDGE('',*,*,#2118,.T.);
#2120=EDGE_LOOP('',(#2104,#2105,#2113,#2119));
#2121=FACE_BOUND('',#2120,.T.);
#2122=ADVANCED_FACE('F2127',(#2121),#2103,.F.);
#2123=CARTESIAN_POINT('',(-1.29294217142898,4.,11.79));
#2124=DIRECTION('',(1.,0.,0.));
#2125=DIRECTION('',(0.,0.,-1.));
#2126=AXIS2_PLACEMENT_3D('',#2123,#2124,#2125);
#2127=PLANE('',#2126);
#2128=ORIENTED_EDGE('',*,*,#242,.T.);
#2129=ORIENTED_EDGE('',*,*,#2118,.F.);
#2130=DIRECTION('',(0.,1.,0.));
#2131=VECTOR('',#2130,1.);
#2132=CARTESIAN_POINT('',(-1.29294217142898,4.,11.79));
#2133=LINE('',#2132,#2131);
#2134=EDGE_CURVE('E1326',#2055,#2111,#2133,.T.);
#2135=ORIENTED_EDGE('',*,*,#2134,.F.);
#2136=ORIENTED_EDGE('',*,*,#2056,.T.);
#2137=EDGE_LOOP('',(#2128,#2129,#2135,#2136));
#2138=FACE_BOUND('',#2137,.T.);
#2139=ADVANCED_FACE('F2124',(#2138),#2127,.F.);
#2140=CARTESIAN_POINT('',(-5.9,4.,11.79));
#2141=DIRECTION('',(0.,0.,1.));
#2142=DIRECTION('',(1.,0.,0.));
#2143=AXIS2_PLACEMENT_3D('',#2140,#2141,#2142);
#2144=PLANE('',#2143);
#2145=ORIENTED_EDGE('',*,*,#2064,.T.);
#2146=ORIENTED_EDGE('',*,*,#2134,.T.);
#2147=ORIENTED_EDGE('',*,*,#2112,.T.);
#2148=ORIENTED_EDGE('',*,*,#2088,.T.);
#2149=EDGE_LOOP('',(#2145,#2146,#2147,#2148));
#2150=FACE_BOUND('',#2149,.T.);
#2151=ADVANCED_FACE('F2072',(#2150),#2144,.T.);
#2152=CARTESIAN_POINT('',(1.28596822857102,4.23444640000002,11.79));
#2153=DIRECTION('',(0.,0.,1.));
#2154=DIRECTION('',(1.,0.,0.));
#2155=AXIS2_PLACEMENT_3D('',#2152,#2153,#2154);
#2156=CYLINDRICAL_SURFACE('',#2155,1.0159344);
#2157=ORIENTED_EDGE('',*,*,#111,.T.);
#2158=DIRECTION('',(0.,0.,1.));
#2159=VECTOR('',#2158,1.);
#2160=CARTESIAN_POINT('',(0.660777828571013,5.03523330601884,11.79));
#2161=LINE('',#2160,#2159);
#2162=CARTESIAN_POINT('',(0.660777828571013,5.03523330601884,11.79));
#2163=VERTEX_POINT('',#2162);
#2164=EDGE_CURVE('E1197',#2163,#110,#2161,.T.);
#2165=ORIENTED_EDGE('',*,*,#2164,.F.);
#2166=CARTESIAN_POINT('',(1.28596822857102,4.23444640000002,11.79));
#2167=DIRECTION('',(0.,0.,1.));
#2168=DIRECTION('',(1.,0.,0.));
#2169=AXIS2_PLACEMENT_3D('',#2166,#2167,#2168);
#2170=CIRCLE('',#2169,1.0159344);
#2171=CARTESIAN_POINT('',(2.30190262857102,4.23444640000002,11.79));
#2172=VERTEX_POINT('',#2171);
#2173=EDGE_CURVE('E1228',#2172,#2163,#2170,.T.);
#2174=ORIENTED_EDGE('',*,*,#2173,.F.);
#2175=DIRECTION('',(0.,0.,1.));
#2176=VECTOR('',#2175,1.);
#2177=CARTESIAN_POINT('',(2.30190262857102,4.23444640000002,11.79));
#2178=LINE('',#2177,#2176);
#2179=EDGE_CURVE('E1166',#2172,#108,#2178,.T.);
#2180=ORIENTED_EDGE('',*,*,#2179,.T.);
#2181=EDGE_LOOP('',(#2157,#2165,#2174,#2180));
#2182=FACE_BOUND('',#2181,.T.);
#2183=ADVANCED_FACE('F2068',(#2182),#2156,.F.);
#2184=CARTESIAN_POINT('',(2.30190262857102,4.,11.79));
#2185=DIRECTION('',(1.,0.,0.));
#2186=DIRECTION('',(0.,0.,-1.));
#2187=AXIS2_PLACEMENT_3D('',#2184,#2185,#2186);
#2188=PLANE('',#2187);
#2189=ORIENTED_EDGE('',*,*,#119,.T.);
#2190=ORIENTED_EDGE('',*,*,#2179,.F.);
#2191=DIRECTION('',(0.,1.,0.));
#2192=VECTOR('',#2191,1.);
#2193=CARTESIAN_POINT('',(2.30190262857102,4.,11.79));
#2194=LINE('',#2193,#2192);
#2195=CARTESIAN_POINT('',(2.30190262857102,2.74961920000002,11.79));
#2196=VERTEX_POINT('',#2195);
#2197=EDGE_CURVE('E1200',#2196,#2172,#2194,.T.);
#2198=ORIENTED_EDGE('',*,*,#2197,.F.);
#2199=DIRECTION('',(0.,0.,1.));
#2200=VECTOR('',#2199,1.);
#2201=CARTESIAN_POINT('',(2.30190262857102,2.74961920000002,11.79));
#2202=LINE('',#2201,#2200);
#2203=EDGE_CURVE('E1221',#2196,#118,#2202,.T.);
#2204=ORIENTED_EDGE('',*,*,#2203,.T.);
#2205=EDGE_LOOP('',(#2189,#2190,#2198,#2204));
#2206=FACE_BOUND('',#2205,.T.);
#2207=ADVANCED_FACE('F2071',(#2206),#2188,.F.);
#2208=CARTESIAN_POINT('',(-5.9,2.74961920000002,11.79));
#2209=DIRECTION('',(0.,-1.,0.));
#2210=DIRECTION('',(0.,0.,-1.));
#2211=AXIS2_PLACEMENT_3D('',#2208,#2209,#2210);
#2212=PLANE('',#2211);
#2213=ORIENTED_EDGE('',*,*,#127,.T.);
#2214=ORIENTED_EDGE('',*,*,#2203,.F.);
#2215=DIRECTION('',(1.,0.,0.));
#2216=VECTOR('',#2215,1.);
#2217=CARTESIAN_POINT('',(-5.9,2.74961920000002,11.79));
#2218=LINE('',#2217,#2216);
#2219=CARTESIAN_POINT('',(1.52041462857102,2.74961920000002,11.79));
#2220=VERTEX_POINT('',#2219);
#2221=EDGE_CURVE('E1266',#2220,#2196,#2218,.T.);
#2222=ORIENTED_EDGE('',*,*,#2221,.F.);
#2223=DIRECTION('',(0.,0.,1.));
#2224=VECTOR('',#2223,1.);
#2225=CARTESIAN_POINT('',(1.52041462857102,2.74961920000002,11.79));
#2226=LINE('',#2225,#2224);
#2227=EDGE_CURVE('E1219',#2220,#126,#2226,.T.);
#2228=ORIENTED_EDGE('',*,*,#2227,.T.);
#2229=EDGE_LOOP('',(#2213,#2214,#2222,#2228));
#2230=FACE_BOUND('',#2229,.T.);
#2231=ADVANCED_FACE('F2113',(#2230),#2212,.F.);
#2232=CARTESIAN_POINT('',(1.52041462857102,4.,11.79));
#2233=DIRECTION('',(-1.,0.,0.));
#2234=DIRECTION('',(0.,0.,1.));
#2235=AXIS2_PLACEMENT_3D('',#2232,#2233,#2234);
#2236=PLANE('',#2235);
#2237=ORIENTED_EDGE('',*,*,#135,.T.);
#2238=ORIENTED_EDGE('',*,*,#2227,.F.);
#2239=DIRECTION('',(0.,-1.,0.));
#2240=VECTOR('',#2239,1.);
#2241=CARTESIAN_POINT('',(1.52041462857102,4.,11.79));
#2242=LINE('',#2241,#2240);
#2243=CARTESIAN_POINT('',(1.52041462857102,4.23444640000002,11.79));
#2244=VERTEX_POINT('',#2243);
#2245=EDGE_CURVE('E1269',#2244,#2220,#2242,.T.);
#2246=ORIENTED_EDGE('',*,*,#2245,.F.);
#2247=DIRECTION('',(0.,0.,1.));
#2248=VECTOR('',#2247,1.);
#2249=CARTESIAN_POINT('',(1.52041462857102,4.23444640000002,11.79));
#2250=LINE('',#2249,#2248);
#2251=EDGE_CURVE('E1217',#2244,#134,#2250,.T.);
#2252=ORIENTED_EDGE('',*,*,#2251,.T.);
#2253=EDGE_LOOP('',(#2237,#2238,#2246,#2252));
#2254=FACE_BOUND('',#2253,.T.);
#2255=ADVANCED_FACE('F2109',(#2254),#2236,.F.);
#2256=CARTESIAN_POINT('',(1.28596822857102,4.23444640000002,11.79));
#2257=DIRECTION('',(0.,0.,1.));
#2258=DIRECTION('',(1.,0.,0.));
#2259=AXIS2_PLACEMENT_3D('',#2256,#2257,#2258);
#2260=CYLINDRICAL_SURFACE('',#2259,0.2344464);
#2261=ORIENTED_EDGE('',*,*,#144,.F.);
#2262=ORIENTED_EDGE('',*,*,#2251,.F.);
#2263=CARTESIAN_POINT('',(1.28596822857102,4.23444640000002,11.79));
#2264=DIRECTION('',(0.,0.,1.));
#2265=DIRECTION('',(1.,0.,0.));
#2266=AXIS2_PLACEMENT_3D('',#2263,#2264,#2265);
#2267=CIRCLE('',#2266,0.2344464);
#2268=CARTESIAN_POINT('',(1.05152182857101,4.23444640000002,11.79));
#2269=VERTEX_POINT('',#2268);
#2270=EDGE_CURVE('E1272',#2244,#2269,#2267,.T.);
#2271=ORIENTED_EDGE('',*,*,#2270,.T.);
#2272=DIRECTION('',(0.,0.,1.));
#2273=VECTOR('',#2272,1.);
#2274=CARTESIAN_POINT('',(1.05152182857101,4.23444640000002,11.79));
#2275=LINE('',#2274,#2273);
#2276=EDGE_CURVE('E1215',#2269,#143,#2275,.T.);
#2277=ORIENTED_EDGE('',*,*,#2276,.T.);
#2278=EDGE_LOOP('',(#2261,#2262,#2271,#2277));
#2279=FACE_BOUND('',#2278,.T.);
#2280=ADVANCED_FACE('F2105',(#2279),#2260,.T.);
#2281=CARTESIAN_POINT('',(1.05152182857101,4.,11.79));
#2282=DIRECTION('',(1.,0.,0.));
#2283=DIRECTION('',(0.,0.,-1.));
#2284=AXIS2_PLACEMENT_3D('',#2281,#2282,#2283);
#2285=PLANE('',#2284);
#2286=ORIENTED_EDGE('',*,*,#152,.T.);
#2287=ORIENTED_EDGE('',*,*,#2276,.F.);
#2288=DIRECTION('',(0.,1.,0.));
#2289=VECTOR('',#2288,1.);
#2290=CARTESIAN_POINT('',(1.05152182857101,4.,11.79));
#2291=LINE('',#2290,#2289);
#2292=CARTESIAN_POINT('',(1.05152182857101,2.74961920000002,11.79));
#2293=VERTEX_POINT('',#2292);
#2294=EDGE_CURVE('E1274',#2293,#2269,#2291,.T.);
#2295=ORIENTED_EDGE('',*,*,#2294,.F.);
#2296=DIRECTION('',(0.,0.,1.));
#2297=VECTOR('',#2296,1.);
#2298=CARTESIAN_POINT('',(1.05152182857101,2.74961920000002,11.79));
#2299=LINE('',#2298,#2297);
#2300=EDGE_CURVE('E1213',#2293,#151,#2299,.T.);
#2301=ORIENTED_EDGE('',*,*,#2300,.T.);
#2302=EDGE_LOOP('',(#2286,#2287,#2295,#2301));
#2303=FACE_BOUND('',#2302,.T.);
#2304=ADVANCED_FACE('F2101',(#2303),#2285,.F.);
#2305=CARTESIAN_POINT('',(-5.9,2.74961920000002,11.79));
#2306=DIRECTION('',(0.,-1.,0.));
#2307=DIRECTION('',(0.,0.,-1.));
#2308=AXIS2_PLACEMENT_3D('',#2305,#2306,#2307);
#2309=PLANE('',#2308);
#2310=ORIENTED_EDGE('',*,*,#160,.T.);
#2311=ORIENTED_EDGE('',*,*,#2300,.F.);
#2312=DIRECTION('',(1.,0.,0.));
#2313=VECTOR('',#2312,1.);
#2314=CARTESIAN_POINT('',(-5.9,2.74961920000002,11.79));
#2315=LINE('',#2314,#2313);
#2316=CARTESIAN_POINT('',(0.270033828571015,2.74961920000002,11.79));
#2317=VERTEX_POINT('',#2316);
#2318=EDGE_CURVE('E1277',#2317,#2293,#2315,.T.);
#2319=ORIENTED_EDGE('',*,*,#2318,.F.);
#2320=DIRECTION('',(0.,0.,1.));
#2321=VECTOR('',#2320,1.);
#2322=CARTESIAN_POINT('',(0.270033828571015,2.74961920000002,11.79));
#2323=LINE('',#2322,#2321);
#2324=EDGE_CURVE('E1211',#2317,#159,#2323,.T.);
#2325=ORIENTED_EDGE('',*,*,#2324,.T.);
#2326=EDGE_LOOP('',(#2310,#2311,#2319,#2325));
#2327=FACE_BOUND('',#2326,.T.);
#2328=ADVANCED_FACE('F2097',(#2327),#2309,.F.);
#2329=CARTESIAN_POINT('',(0.270033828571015,4.,11.79));
#2330=DIRECTION('',(-1.,0.,0.));
#2331=DIRECTION('',(0.,0.,1.));
#2332=AXIS2_PLACEMENT_3D('',#2329,#2330,#2331);
#2333=PLANE('',#2332);
#2334=ORIENTED_EDGE('',*,*,#168,.T.);
#2335=ORIENTED_EDGE('',*,*,#2324,.F.);
#2336=DIRECTION('',(0.,-1.,0.));
#2337=VECTOR('',#2336,1.);
#2338=CARTESIAN_POINT('',(0.270033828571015,4.,11.79));
#2339=LINE('',#2338,#2337);
#2340=CARTESIAN_POINT('',(0.270033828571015,4.23444640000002,11.79));
#2341=VERTEX_POINT('',#2340);
#2342=EDGE_CURVE('E1280',#2341,#2317,#2339,.T.);
#2343=ORIENTED_EDGE('',*,*,#2342,.F.);
#2344=DIRECTION('',(0.,0.,1.));
#2345=VECTOR('',#2344,1.);
#2346=CARTESIAN_POINT('',(0.270033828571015,4.23444640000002,11.79));
#2347=LINE('',#2346,#2345);
#2348=EDGE_CURVE('E1209',#2341,#167,#2347,.T.);
#2349=ORIENTED_EDGE('',*,*,#2348,.T.);
#2350=EDGE_LOOP('',(#2334,#2335,#2343,#2349));
#2351=FACE_BOUND('',#2350,.T.);
#2352=ADVANCED_FACE('F2093',(#2351),#2333,.F.);
#2353=CARTESIAN_POINT('',(0.0355874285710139,4.23444640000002,11.79));
#2354=DIRECTION('',(0.,0.,1.));
#2355=DIRECTION('',(1.,0.,0.));
#2356=AXIS2_PLACEMENT_3D('',#2353,#2354,#2355);
#2357=CYLINDRICAL_SURFACE('',#2356,0.2344464);
#2358=ORIENTED_EDGE('',*,*,#177,.F.);
#2359=ORIENTED_EDGE('',*,*,#2348,.F.);
#2360=CARTESIAN_POINT('',(0.0355874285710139,4.23444640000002,11.79));
#2361=DIRECTION('',(0.,0.,1.));
#2362=DIRECTION('',(1.,0.,0.));
#2363=AXIS2_PLACEMENT_3D('',#2360,#2361,#2362);
#2364=CIRCLE('',#2363,0.2344464);
#2365=CARTESIAN_POINT('',(-0.198858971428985,4.23444640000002,11.79));
#2366=VERTEX_POINT('',#2365);
#2367=EDGE_CURVE('E1283',#2341,#2366,#2364,.T.);
#2368=ORIENTED_EDGE('',*,*,#2367,.T.);
#2369=DIRECTION('',(0.,0.,1.));
#2370=VECTOR('',#2369,1.);
#2371=CARTESIAN_POINT('',(-0.198858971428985,4.23444640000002,11.79));
#2372=LINE('',#2371,#2370);
#2373=EDGE_CURVE('E1207',#2366,#176,#2372,.T.);
#2374=ORIENTED_EDGE('',*,*,#2373,.T.);
#2375=EDGE_LOOP('',(#2358,#2359,#2368,#2374));
#2376=FACE_BOUND('',#2375,.T.);
#2377=ADVANCED_FACE('F2089',(#2376),#2357,.T.);
#2378=CARTESIAN_POINT('',(-0.198858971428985,4.,11.79));
#2379=DIRECTION('',(1.,0.,0.));
#2380=DIRECTION('',(0.,0.,-1.));
#2381=AXIS2_PLACEMENT_3D('',#2378,#2379,#2380);
#2382=PLANE('',#2381);
#2383=ORIENTED_EDGE('',*,*,#185,.T.);
#2384=ORIENTED_EDGE('',*,*,#2373,.F.);
#2385=DIRECTION('',(0.,1.,0.));
#2386=VECTOR('',#2385,1.);
#2387=CARTESIAN_POINT('',(-0.198858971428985,4.,11.79));
#2388=LINE('',#2387,#2386);
#2389=CARTESIAN_POINT('',(-0.198858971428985,2.74961920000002,11.79));
#2390=VERTEX_POINT('',#2389);
#2391=EDGE_CURVE('E1285',#2390,#2366,#2388,.T.);
#2392=ORIENTED_EDGE('',*,*,#2391,.F.);
#2393=DIRECTION('',(0.,0.,1.));
#2394=VECTOR('',#2393,1.);
#2395=CARTESIAN_POINT('',(-0.198858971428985,2.74961920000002,11.79));
#2396=LINE('',#2395,#2394);
#2397=EDGE_CURVE('E1205',#2390,#184,#2396,.T.);
#2398=ORIENTED_EDGE('',*,*,#2397,.T.);
#2399=EDGE_LOOP('',(#2383,#2384,#2392,#2398));
#2400=FACE_BOUND('',#2399,.T.);
#2401=ADVANCED_FACE('F2085',(#2400),#2382,.F.);
#2402=CARTESIAN_POINT('',(-5.9,2.74961920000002,11.79));
#2403=DIRECTION('',(0.,-1.,0.));
#2404=DIRECTION('',(0.,0.,-1.));
#2405=AXIS2_PLACEMENT_3D('',#2402,#2403,#2404);
#2406=PLANE('',#2405);
#2407=ORIENTED_EDGE('',*,*,#193,.T.);
#2408=ORIENTED_EDGE('',*,*,#2397,.F.);
#2409=DIRECTION('',(1.,0.,0.));
#2410=VECTOR('',#2409,1.);
#2411=CARTESIAN_POINT('',(-5.9,2.74961920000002,11.79));
#2412=LINE('',#2411,#2410);
#2413=CARTESIAN_POINT('',(-0.980346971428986,2.74961920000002,11.79));
#2414=VERTEX_POINT('',#2413);
#2415=EDGE_CURVE('E1288',#2414,#2390,#2412,.T.);
#2416=ORIENTED_EDGE('',*,*,#2415,.F.);
#2417=DIRECTION('',(0.,0.,1.));
#2418=VECTOR('',#2417,1.);
#2419=CARTESIAN_POINT('',(-0.980346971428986,2.74961920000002,11.79));
#2420=LINE('',#2419,#2418);
#2421=EDGE_CURVE('E1203',#2414,#192,#2420,.T.);
#2422=ORIENTED_EDGE('',*,*,#2421,.T.);
#2423=EDGE_LOOP('',(#2407,#2408,#2416,#2422));
#2424=FACE_BOUND('',#2423,.T.);
#2425=ADVANCED_FACE('F2081',(#2424),#2406,.F.);
#2426=CARTESIAN_POINT('',(-0.980346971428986,4.,11.79));
#2427=DIRECTION('',(-1.,0.,0.));
#2428=DIRECTION('',(0.,0.,1.));
#2429=AXIS2_PLACEMENT_3D('',#2426,#2427,#2428);
#2430=PLANE('',#2429);
#2431=ORIENTED_EDGE('',*,*,#201,.T.);
#2432=ORIENTED_EDGE('',*,*,#2421,.F.);
#2433=DIRECTION('',(0.,-1.,0.));
#2434=VECTOR('',#2433,1.);
#2435=CARTESIAN_POINT('',(-0.980346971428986,4.,11.79));
#2436=LINE('',#2435,#2434);
#2437=CARTESIAN_POINT('',(-0.980346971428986,4.23444640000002,11.79));
#2438=VERTEX_POINT('',#2437);
#2439=EDGE_CURVE('E1291',#2438,#2414,#2436,.T.);
#2440=ORIENTED_EDGE('',*,*,#2439,.F.);
#2441=DIRECTION('',(0.,0.,1.));
#2442=VECTOR('',#2441,1.);
#2443=CARTESIAN_POINT('',(-0.980346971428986,4.23444640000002,11.79));
#2444=LINE('',#2443,#2442);
#2445=EDGE_CURVE('E1201',#2438,#200,#2444,.T.);
#2446=ORIENTED_EDGE('',*,*,#2445,.T.);
#2447=EDGE_LOOP('',(#2431,#2432,#2440,#2446));
#2448=FACE_BOUND('',#2447,.T.);
#2449=ADVANCED_FACE('F2077',(#2448),#2430,.F.);
#2450=CARTESIAN_POINT('',(0.0355874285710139,4.23444640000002,11.79));
#2451=DIRECTION('',(0.,0.,1.));
#2452=DIRECTION('',(1.,0.,0.));
#2453=AXIS2_PLACEMENT_3D('',#2450,#2451,#2452);
#2454=CYLINDRICAL_SURFACE('',#2453,1.0159344);
#2455=ORIENTED_EDGE('',*,*,#208,.T.);
#2456=ORIENTED_EDGE('',*,*,#2445,.F.);
#2457=CARTESIAN_POINT('',(0.0355874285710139,4.23444640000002,11.79));
#2458=DIRECTION('',(0.,0.,1.));
#2459=DIRECTION('',(1.,0.,0.));
#2460=AXIS2_PLACEMENT_3D('',#2457,#2458,#2459);
#2461=CIRCLE('',#2460,1.0159344);
#2462=EDGE_CURVE('E1294',#2163,#2438,#2461,.T.);
#2463=ORIENTED_EDGE('',*,*,#2462,.F.);
#2464=ORIENTED_EDGE('',*,*,#2164,.T.);
#2465=EDGE_LOOP('',(#2455,#2456,#2463,#2464));
#2466=FACE_BOUND('',#2465,.T.);
#2467=ADVANCED_FACE('F2074',(#2466),#2454,.F.);
#2468=CARTESIAN_POINT('',(-5.9,4.,11.79));
#2469=DIRECTION('',(0.,0.,1.));
#2470=DIRECTION('',(1.,0.,0.));
#2471=AXIS2_PLACEMENT_3D('',#2468,#2469,#2470);
#2472=PLANE('',#2471);
#2473=ORIENTED_EDGE('',*,*,#2173,.T.);
#2474=ORIENTED_EDGE('',*,*,#2462,.T.);
#2475=ORIENTED_EDGE('',*,*,#2439,.T.);
#2476=ORIENTED_EDGE('',*,*,#2415,.T.);
#2477=ORIENTED_EDGE('',*,*,#2391,.T.);
#2478=ORIENTED_EDGE('',*,*,#2367,.F.);
#2479=ORIENTED_EDGE('',*,*,#2342,.T.);
#2480=ORIENTED_EDGE('',*,*,#2318,.T.);
#2481=ORIENTED_EDGE('',*,*,#2294,.T.);
#2482=ORIENTED_EDGE('',*,*,#2270,.F.);
#2483=ORIENTED_EDGE('',*,*,#2245,.T.);
#2484=ORIENTED_EDGE('',*,*,#2221,.T.);
#2485=ORIENTED_EDGE('',*,*,#2197,.T.);
#2486=EDGE_LOOP('',(#2473,#2474,#2475,#2476,#2477,#2478,#2479,#2480,#2481,#2482,#2483,#2484,#2485));
#2487=FACE_BOUND('',#2486,.T.);
#2488=ADVANCED_FACE('F2037',(#2487),#2472,.T.);
#2489=CARTESIAN_POINT('',(4.64636662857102,4.,11.79));
#2490=DIRECTION('',(1.,0.,0.));
#2491=DIRECTION('',(0.,0.,-1.));
#2492=AXIS2_PLACEMENT_3D('',#2489,#2490,#2491);
#2493=PLANE('',#2492);
#2494=ORIENTED_EDGE('',*,*,#43,.T.);
#2495=DIRECTION('',(0.,0.,1.));
#2496=VECTOR('',#2495,1.);
#2497=CARTESIAN_POINT('',(4.64636662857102,4.23444661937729,11.79));
#2498=LINE('',#2497,#2496);
#2499=CARTESIAN_POINT('',(4.64636662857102,4.23444661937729,11.79));
#2500=VERTEX_POINT('',#2499);
#2501=EDGE_CURVE('E1116',#2500,#42,#2498,.T.);
#2502=ORIENTED_EDGE('',*,*,#2501,.F.);
#2503=DIRECTION('',(0.,1.,0.));
#2504=VECTOR('',#2503,1.);
#2505=CARTESIAN_POINT('',(4.64636662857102,4.,11.79));
#2506=LINE('',#2505,#2504);
#2507=CARTESIAN_POINT('',(4.64636662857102,2.74961920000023,11.79));
#2508=VERTEX_POINT('',#2507);
#2509=EDGE_CURVE('E1186',#2508,#2500,#2506,.T.);
#2510=ORIENTED_EDGE('',*,*,#2509,.F.);
#2511=DIRECTION('',(0.,0.,1.));
#2512=VECTOR('',#2511,1.);
#2513=CARTESIAN_POINT('',(4.64636662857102,2.74961920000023,11.79));
#2514=LINE('',#2513,#2512);
#2515=EDGE_CURVE('E1102',#2508,#40,#2514,.T.);
#2516=ORIENTED_EDGE('',*,*,#2515,.T.);
#2517=EDGE_LOOP('',(#2494,#2502,#2510,#2516));
#2518=FACE_BOUND('',#2517,.T.);
#2519=ADVANCED_FACE('F2033',(#2518),#2493,.F.);
#2520=CARTESIAN_POINT('',(-5.9,2.74961920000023,11.79));
#2521=DIRECTION('',(0.,-1.,0.));
#2522=DIRECTION('',(0.,0.,-1.));
#2523=AXIS2_PLACEMENT_3D('',#2520,#2521,#2522);
#2524=PLANE('',#2523);
#2525=ORIENTED_EDGE('',*,*,#51,.T.);
#2526=ORIENTED_EDGE('',*,*,#2515,.F.);
#2527=DIRECTION('',(1.,0.,0.));
#2528=VECTOR('',#2527,1.);
#2529=CARTESIAN_POINT('',(-5.9,2.74961920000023,11.79));
#2530=LINE('',#2529,#2528);
#2531=CARTESIAN_POINT('',(3.86487862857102,2.74961920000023,11.79));
#2532=VERTEX_POINT('',#2531);
#2533=EDGE_CURVE('E1109',#2532,#2508,#2530,.T.);
#2534=ORIENTED_EDGE('',*,*,#2533,.F.);
#2535=DIRECTION('',(0.,0.,1.));
#2536=VECTOR('',#2535,1.);
#2537=CARTESIAN_POINT('',(3.86487862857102,2.74961920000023,11.79));
#2538=LINE('',#2537,#2536);
#2539=EDGE_CURVE('E1129',#2532,#50,#2538,.T.);
#2540=ORIENTED_EDGE('',*,*,#2539,.T.);
#2541=EDGE_LOOP('',(#2525,#2526,#2534,#2540));
#2542=FACE_BOUND('',#2541,.T.);
#2543=ADVANCED_FACE('F2036',(#2542),#2524,.F.);
#2544=CARTESIAN_POINT('',(3.86487862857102,4.,11.79));
#2545=DIRECTION('',(1.,0.,0.));
#2546=DIRECTION('',(0.,0.,-1.));
#2547=AXIS2_PLACEMENT_3D('',#2544,#2545,#2546);
#2548=PLANE('',#2547);
#2549=ORIENTED_EDGE('',*,*,#59,.F.);
#2550=ORIENTED_EDGE('',*,*,#2539,.F.);
#2551=DIRECTION('',(0.,1.,0.));
#2552=VECTOR('',#2551,1.);
#2553=CARTESIAN_POINT('',(3.86487862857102,4.,11.79));
#2554=LINE('',#2553,#2552);
#2555=CARTESIAN_POINT('',(3.86487862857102,3.29666080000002,11.79));
#2556=VERTEX_POINT('',#2555);
#2557=EDGE_CURVE('E1169',#2532,#2556,#2554,.T.);
#2558=ORIENTED_EDGE('',*,*,#2557,.T.);
#2559=DIRECTION('',(0.,0.,1.));
#2560=VECTOR('',#2559,1.);
#2561=CARTESIAN_POINT('',(3.86487862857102,3.29666080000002,11.79));
#2562=LINE('',#2561,#2560);
#2563=EDGE_CURVE('E1127',#2556,#58,#2562,.T.);
#2564=ORIENTED_EDGE('',*,*,#2563,.T.);
#2565=EDGE_LOOP('',(#2549,#2550,#2558,#2564));
#2566=FACE_BOUND('',#2565,.T.);
#2567=ADVANCED_FACE('F2057',(#2566),#2548,.T.);
#2568=CARTESIAN_POINT('',(-5.90000000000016,3.29666080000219,11.79));
#2569=DIRECTION('',(-2.21976981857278E-13,-1.,0.));
#2570=DIRECTION('',(1.,-2.21976981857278E-13,0.));
#2571=AXIS2_PLACEMENT_3D('',#2568,#2569,#2570);
#2572=PLANE('',#2571);
#2573=ORIENTED_EDGE('',*,*,#67,.T.);
#2574=ORIENTED_EDGE('',*,*,#2563,.F.);
#2575=DIRECTION('',(1.,-2.21976981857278E-13,0.));
#2576=VECTOR('',#2575,1.);
#2577=CARTESIAN_POINT('',(-5.90000000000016,3.29666080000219,11.79));
#2578=LINE('',#2577,#2576);
#2579=CARTESIAN_POINT('',(3.39598582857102,3.29666080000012,11.79));
#2580=VERTEX_POINT('',#2579);
#2581=EDGE_CURVE('E1171',#2580,#2556,#2578,.T.);
#2582=ORIENTED_EDGE('',*,*,#2581,.F.);
#2583=DIRECTION('',(0.,0.,1.));
#2584=VECTOR('',#2583,1.);
#2585=CARTESIAN_POINT('',(3.39598582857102,3.29666080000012,11.79));
#2586=LINE('',#2585,#2584);
#2587=EDGE_CURVE('E1125',#2580,#66,#2586,.T.);
#2588=ORIENTED_EDGE('',*,*,#2587,.T.);
#2589=EDGE_LOOP('',(#2573,#2574,#2582,#2588));
#2590=FACE_BOUND('',#2589,.T.);
#2591=ADVANCED_FACE('F2053',(#2590),#2572,.F.);
#2592=CARTESIAN_POINT('',(3.39598582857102,4.,11.79));
#2593=DIRECTION('',(1.,0.,0.));
#2594=DIRECTION('',(0.,0.,-1.));
#2595=AXIS2_PLACEMENT_3D('',#2592,#2593,#2594);
#2596=PLANE('',#2595);
#2597=ORIENTED_EDGE('',*,*,#75,.T.);
#2598=ORIENTED_EDGE('',*,*,#2587,.F.);
#2599=DIRECTION('',(0.,1.,0.));
#2600=VECTOR('',#2599,1.);
#2601=CARTESIAN_POINT('',(3.39598582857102,4.,11.79));
#2602=LINE('',#2601,#2600);
#2603=CARTESIAN_POINT('',(3.39598582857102,2.74961919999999,11.79));
#2604=VERTEX_POINT('',#2603);
#2605=EDGE_CURVE('E1174',#2604,#2580,#2602,.T.);
#2606=ORIENTED_EDGE('',*,*,#2605,.F.);
#2607=DIRECTION('',(0.,0.,1.));
#2608=VECTOR('',#2607,1.);
#2609=CARTESIAN_POINT('',(3.39598582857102,2.74961919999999,11.79));
#2610=LINE('',#2609,#2608);
#2611=EDGE_CURVE('E1123',#2604,#74,#2610,.T.);
#2612=ORIENTED_EDGE('',*,*,#2611,.T.);
#2613=EDGE_LOOP('',(#2597,#2598,#2606,#2612));
#2614=FACE_BOUND('',#2613,.T.);
#2615=ADVANCED_FACE('F2049',(#2614),#2596,.F.);
#2616=CARTESIAN_POINT('',(-5.9,2.7496192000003,11.79));
#2617=DIRECTION('',(0.,-1.,0.));
#2618=DIRECTION('',(1.,0.,0.));
#2619=AXIS2_PLACEMENT_3D('',#2616,#2617,#2618);
#2620=PLANE('',#2619);
#2621=ORIENTED_EDGE('',*,*,#83,.T.);
#2622=ORIENTED_EDGE('',*,*,#2611,.F.);
#2623=DIRECTION('',(1.,0.,0.));
#2624=VECTOR('',#2623,1.);
#2625=CARTESIAN_POINT('',(-5.9,2.7496192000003,11.79));
#2626=LINE('',#2625,#2624);
#2627=CARTESIAN_POINT('',(2.61449782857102,2.74961920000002,11.79));
#2628=VERTEX_POINT('',#2627);
#2629=EDGE_CURVE('E1177',#2628,#2604,#2626,.T.);
#2630=ORIENTED_EDGE('',*,*,#2629,.F.);
#2631=DIRECTION('',(0.,0.,1.));
#2632=VECTOR('',#2631,1.);
#2633=CARTESIAN_POINT('',(2.61449782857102,2.74961920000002,11.79));
#2634=LINE('',#2633,#2632);
#2635=EDGE_CURVE('E1121',#2628,#82,#2634,.T.);
#2636=ORIENTED_EDGE('',*,*,#2635,.T.);
#2637=EDGE_LOOP('',(#2621,#2622,#2630,#2636));
#2638=FACE_BOUND('',#2637,.T.);
#2639=ADVANCED_FACE('F2045',(#2638),#2620,.F.);
#2640=CARTESIAN_POINT('',(2.61449782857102,4.,11.79));
#2641=DIRECTION('',(-1.,0.,0.));
#2642=DIRECTION('',(0.,0.,1.));
#2643=AXIS2_PLACEMENT_3D('',#2640,#2641,#2642);
#2644=PLANE('',#2643);
#2645=ORIENTED_EDGE('',*,*,#91,.T.);
#2646=ORIENTED_EDGE('',*,*,#2635,.F.);
#2647=DIRECTION('',(0.,-1.,0.));
#2648=VECTOR('',#2647,1.);
#2649=CARTESIAN_POINT('',(2.61449782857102,4.,11.79));
#2650=LINE('',#2649,#2648);
#2651=CARTESIAN_POINT('',(2.61449782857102,4.23444661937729,11.79));
#2652=VERTEX_POINT('',#2651);
#2653=EDGE_CURVE('E1180',#2652,#2628,#2650,.T.);
#2654=ORIENTED_EDGE('',*,*,#2653,.F.);
#2655=DIRECTION('',(0.,0.,1.));
#2656=VECTOR('',#2655,1.);
#2657=CARTESIAN_POINT('',(2.61449782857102,4.23444661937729,11.79));
#2658=LINE('',#2657,#2656);
#2659=EDGE_CURVE('E1119',#2652,#90,#2658,.T.);
#2660=ORIENTED_EDGE('',*,*,#2659,.T.);
#2661=EDGE_LOOP('',(#2645,#2646,#2654,#2660));
#2662=FACE_BOUND('',#2661,.T.);
#2663=ADVANCED_FACE('F2020',(#2662),#2644,.F.);
#2664=CARTESIAN_POINT('',(3.63043222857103,4.23444661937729,11.79));
#2665=DIRECTION('',(0.,0.,1.));
#2666=DIRECTION('',(1.,0.,0.));
#2667=AXIS2_PLACEMENT_3D('',#2664,#2665,#2666);
#2668=CYLINDRICAL_SURFACE('',#2667,0.2344464);
#2669=CARTESIAN_POINT('',(3.63043222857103,4.23444661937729,11.8));
#2670=DIRECTION('',(0.,0.,1.));
#2671=DIRECTION('',(1.,0.,0.));
#2672=AXIS2_PLACEMENT_3D('',#2669,#2670,#2671);
#2673=CIRCLE('',#2672,0.2344464);
#2674=CARTESIAN_POINT('',(3.86487862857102,4.23444661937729,11.8));
#2675=VERTEX_POINT('',#2674);
#2676=CARTESIAN_POINT('',(3.39598582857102,4.23444661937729,11.8));
#2677=VERTEX_POINT('',#2676);
#2678=EDGE_CURVE('E40',#2675,#2677,#2673,.T.);
#2679=ORIENTED_EDGE('',*,*,#2678,.F.);
#2680=DIRECTION('',(0.,0.,1.));
#2681=VECTOR('',#2680,1.);
#2682=CARTESIAN_POINT('',(3.86487862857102,4.23444661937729,11.79));
#2683=LINE('',#2682,#2681);
#2684=CARTESIAN_POINT('',(3.86487862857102,4.23444661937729,11.79));
#2685=VERTEX_POINT('',#2684);
#2686=EDGE_CURVE('E1107',#2685,#2675,#2683,.T.);
#2687=ORIENTED_EDGE('',*,*,#2686,.F.);
#2688=CARTESIAN_POINT('',(3.63043222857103,4.23444661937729,11.79));
#2689=DIRECTION('',(0.,0.,1.));
#2690=DIRECTION('',(1.,0.,0.));
#2691=AXIS2_PLACEMENT_3D('',#2688,#2689,#2690);
#2692=CIRCLE('',#2691,0.2344464);
#2693=CARTESIAN_POINT('',(3.39598582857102,4.23444661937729,11.79));
#2694=VERTEX_POINT('',#2693);
#2695=EDGE_CURVE('E1136',#2685,#2694,#2692,.T.);
#2696=ORIENTED_EDGE('',*,*,#2695,.T.);
#2697=DIRECTION('',(0.,0.,1.));
#2698=VECTOR('',#2697,1.);
#2699=CARTESIAN_POINT('',(3.39598582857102,4.23444661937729,11.79));
#2700=LINE('',#2699,#2698);
#2701=EDGE_CURVE('E1114',#2694,#2677,#2700,.T.);
#2702=ORIENTED_EDGE('',*,*,#2701,.T.);
#2703=EDGE_LOOP('',(#2679,#2687,#2696,#2702));
#2704=FACE_BOUND('',#2703,.T.);
#2705=ADVANCED_FACE('F2016',(#2704),#2668,.T.);
#2706=CARTESIAN_POINT('',(3.39598582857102,4.,11.79));
#2707=DIRECTION('',(-1.,0.,0.));
#2708=DIRECTION('',(0.,0.,1.));
#2709=AXIS2_PLACEMENT_3D('',#2706,#2707,#2708);
#2710=PLANE('',#2709);
#2711=DIRECTION('',(0.,-1.,0.));
#2712=VECTOR('',#2711,1.);
#2713=CARTESIAN_POINT('',(3.39598582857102,4.,11.8));
#2714=LINE('',#2713,#2712);
#2715=CARTESIAN_POINT('',(3.39598582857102,3.92185120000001,11.8));
#2716=VERTEX_POINT('',#2715);
#2717=EDGE_CURVE('E1156',#2677,#2716,#2714,.T.);
#2718=ORIENTED_EDGE('',*,*,#2717,.F.);
#2719=ORIENTED_EDGE('',*,*,#2701,.F.);
#2720=DIRECTION('',(0.,-1.,0.));
#2721=VECTOR('',#2720,1.);
#2722=CARTESIAN_POINT('',(3.39598582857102,4.,11.79));
#2723=LINE('',#2722,#2721);
#2724=CARTESIAN_POINT('',(3.39598582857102,3.92185120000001,11.79));
#2725=VERTEX_POINT('',#2724);
#2726=EDGE_CURVE('E1189',#2694,#2725,#2723,.T.);
#2727=ORIENTED_EDGE('',*,*,#2726,.T.);
#2728=DIRECTION('',(0.,0.,1.));
#2729=VECTOR('',#2728,1.);
#2730=CARTESIAN_POINT('',(3.39598582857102,3.92185120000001,11.79));
#2731=LINE('',#2730,#2729);
#2732=EDGE_CURVE('E1112',#2725,#2716,#2731,.T.);
#2733=ORIENTED_EDGE('',*,*,#2732,.T.);
#2734=EDGE_LOOP('',(#2718,#2719,#2727,#2733));
#2735=FACE_BOUND('',#2734,.T.);
#2736=ADVANCED_FACE('F2019',(#2735),#2710,.T.);
#2737=CARTESIAN_POINT('',(-5.9,3.92185120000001,11.79));
#2738=DIRECTION('',(0.,-1.,0.));
#2739=DIRECTION('',(0.,0.,-1.));
#2740=AXIS2_PLACEMENT_3D('',#2737,#2738,#2739);
#2741=PLANE('',#2740);
#2742=DIRECTION('',(1.,0.,0.));
#2743=VECTOR('',#2742,1.);
#2744=CARTESIAN_POINT('',(-5.9,3.92185120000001,11.8));
#2745=LINE('',#2744,#2743);
#2746=CARTESIAN_POINT('',(3.86487862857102,3.92185120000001,11.8));
#2747=VERTEX_POINT('',#2746);
#2748=EDGE_CURVE('E1159',#2716,#2747,#2745,.T.);
#2749=ORIENTED_EDGE('',*,*,#2748,.F.);
#2750=ORIENTED_EDGE('',*,*,#2732,.F.);
#2751=DIRECTION('',(1.,0.,0.));
#2752=VECTOR('',#2751,1.);
#2753=CARTESIAN_POINT('',(-5.9,3.92185120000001,11.79));
#2754=LINE('',#2753,#2752);
#2755=CARTESIAN_POINT('',(3.86487862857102,3.92185120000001,11.79));
#2756=VERTEX_POINT('',#2755);
#2757=EDGE_CURVE('E1191',#2725,#2756,#2754,.T.);
#2758=ORIENTED_EDGE('',*,*,#2757,.T.);
#2759=DIRECTION('',(0.,0.,1.));
#2760=VECTOR('',#2759,1.);
#2761=CARTESIAN_POINT('',(3.86487862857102,3.92185120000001,11.79));
#2762=LINE('',#2761,#2760);
#2763=EDGE_CURVE('E1110',#2756,#2747,#2762,.T.);
#2764=ORIENTED_EDGE('',*,*,#2763,.T.);
#2765=EDGE_LOOP('',(#2749,#2750,#2758,#2764));
#2766=FACE_BOUND('',#2765,.T.);
#2767=ADVANCED_FACE('F2025',(#2766),#2741,.T.);
#2768=CARTESIAN_POINT('',(3.86487862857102,4.,11.79));
#2769=DIRECTION('',(1.,0.,0.));
#2770=DIRECTION('',(0.,0.,-1.));
#2771=AXIS2_PLACEMENT_3D('',#2768,#2769,#2770);
#2772=PLANE('',#2771);
#2773=DIRECTION('',(0.,1.,0.));
#2774=VECTOR('',#2773,1.);
#2775=CARTESIAN_POINT('',(3.86487862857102,4.,11.8));
#2776=LINE('',#2775,#2774);
#2777=EDGE_CURVE('E1162',#2747,#2675,#2776,.T.);
#2778=ORIENTED_EDGE('',*,*,#2777,.F.);
#2779=ORIENTED_EDGE('',*,*,#2763,.F.);
#2780=DIRECTION('',(0.,1.,0.));
#2781=VECTOR('',#2780,1.);
#2782=CARTESIAN_POINT('',(3.86487862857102,4.,11.79));
#2783=LINE('',#2782,#2781);
#2784=EDGE_CURVE('E1193',#2756,#2685,#2783,.T.);
#2785=ORIENTED_EDGE('',*,*,#2784,.T.);
#2786=ORIENTED_EDGE('',*,*,#2686,.T.);
#2787=EDGE_LOOP('',(#2778,#2779,#2785,#2786));
#2788=FACE_BOUND('',#2787,.T.);
#2789=ADVANCED_FACE('F2021',(#2788),#2772,.T.);
#2790=CARTESIAN_POINT('',(3.63043222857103,4.23444661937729,11.79));
#2791=DIRECTION('',(0.,0.,1.));
#2792=DIRECTION('',(1.,0.,0.));
#2793=AXIS2_PLACEMENT_3D('',#2790,#2791,#2792);
#2794=CYLINDRICAL_SURFACE('',#2793,1.0159344);
#2795=ORIENTED_EDGE('',*,*,#98,.T.);
#2796=ORIENTED_EDGE('',*,*,#2659,.F.);
#2797=CARTESIAN_POINT('',(3.63043222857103,4.23444661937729,11.79));
#2798=DIRECTION('',(0.,0.,1.));
#2799=DIRECTION('',(1.,0.,0.));
#2800=AXIS2_PLACEMENT_3D('',#2797,#2798,#2799);
#2801=CIRCLE('',#2800,1.0159344);
#2802=EDGE_CURVE('E1183',#2500,#2652,#2801,.T.);
#2803=ORIENTED_EDGE('',*,*,#2802,.F.);
#2804=ORIENTED_EDGE('',*,*,#2501,.T.);
#2805=EDGE_LOOP('',(#2795,#2796,#2803,#2804));
#2806=FACE_BOUND('',#2805,.T.);
#2807=ADVANCED_FACE('F2024',(#2806),#2794,.F.);
#2808=CARTESIAN_POINT('',(-5.9,4.,11.79));
#2809=DIRECTION('',(0.,0.,1.));
#2810=DIRECTION('',(1.,0.,0.));
#2811=AXIS2_PLACEMENT_3D('',#2808,#2809,#2810);
#2812=PLANE('',#2811);
#2813=ORIENTED_EDGE('',*,*,#2695,.F.);
#2814=ORIENTED_EDGE('',*,*,#2784,.F.);
#2815=ORIENTED_EDGE('',*,*,#2757,.F.);
#2816=ORIENTED_EDGE('',*,*,#2726,.F.);
#2817=EDGE_LOOP('',(#2813,#2814,#2815,#2816));
#2818=FACE_BOUND('',#2817,.T.);
#2819=ORIENTED_EDGE('',*,*,#2509,.T.);
#2820=ORIENTED_EDGE('',*,*,#2802,.T.);
#2821=ORIENTED_EDGE('',*,*,#2653,.T.);
#2822=ORIENTED_EDGE('',*,*,#2629,.T.);
#2823=ORIENTED_EDGE('',*,*,#2605,.T.);
#2824=ORIENTED_EDGE('',*,*,#2581,.T.);
#2825=ORIENTED_EDGE('',*,*,#2557,.F.);
#2826=ORIENTED_EDGE('',*,*,#2533,.T.);
#2827=EDGE_LOOP('',(#2819,#2820,#2821,#2822,#2823,#2824,#2825,#2826));
#2828=FACE_BOUND('',#2827,.T.);
#2829=ADVANCED_FACE('F2041',(#2818,#2828),#2812,.T.);
#2830=ORIENTED_EDGE('',*,*,#2777,.T.);
#2831=ORIENTED_EDGE('',*,*,#2678,.T.);
#2832=ORIENTED_EDGE('',*,*,#2717,.T.);
#2833=ORIENTED_EDGE('',*,*,#2748,.T.);
#2834=EDGE_LOOP('',(#2830,#2831,#2832,#2833));
#2835=FACE_BOUND('',#2834,.T.);
#2836=ADVANCED_FACE('F1762',(#2835),#23,.T.);
#2837=CARTESIAN_POINT('',(6.20934262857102,4.,11.79));
#2838=DIRECTION('',(0.,0.,1.));
#2839=DIRECTION('',(1.,0.,0.));
#2840=AXIS2_PLACEMENT_3D('',#2837,#2838,#2839);
#2841=CYLINDRICAL_SURFACE('',#2840,0.4688928);
#2842=CARTESIAN_POINT('',(6.20934262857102,4.,11.79));
#2843=DIRECTION('',(0.,0.,1.));
#2844=DIRECTION('',(1.,0.,0.));
#2845=AXIS2_PLACEMENT_3D('',#2842,#2843,#2844);
#2846=CIRCLE('',#2845,0.4688928);
#2847=CARTESIAN_POINT('',(6.67823542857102,4.,11.79));
#2848=VERTEX_POINT('',#2847);
#2849=EDGE_CURVE('E1099',#2848,#2848,#2846,.T.);
#2850=ORIENTED_EDGE('',*,*,#2849,.T.);
#2851=EDGE_LOOP('',(#2850));
#2852=FACE_BOUND('',#2851,.T.);
#2853=CARTESIAN_POINT('',(6.20934262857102,4.,11.8));
#2854=DIRECTION('',(0.,0.,1.));
#2855=DIRECTION('',(1.,0.,0.));
#2856=AXIS2_PLACEMENT_3D('',#2853,#2854,#2855);
#2857=CIRCLE('',#2856,0.4688928);
#2858=CARTESIAN_POINT('',(6.67823542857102,4.,11.8));
#2859=VERTEX_POINT('',#2858);
#2860=EDGE_CURVE('E1098',#2859,#2859,#2857,.T.);
#2861=ORIENTED_EDGE('',*,*,#2860,.F.);
#2862=EDGE_LOOP('',(#2861));
#2863=FACE_BOUND('',#2862,.T.);
#2864=ADVANCED_FACE('F2005',(#2852,#2863),#2841,.T.);
#2865=CARTESIAN_POINT('',(6.20934262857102,4.,11.79));
#2866=DIRECTION('',(0.,0.,1.));
#2867=DIRECTION('',(1.,0.,0.));
#2868=AXIS2_PLACEMENT_3D('',#2865,#2866,#2867);
#2869=CYLINDRICAL_SURFACE('',#2868,1.25038079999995);
#2870=CARTESIAN_POINT('',(6.20934262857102,4.,11.79));
#2871=DIRECTION('',(0.,0.,1.));
#2872=DIRECTION('',(1.,0.,0.));
#2873=AXIS2_PLACEMENT_3D('',#2870,#2871,#2872);
#2874=CIRCLE('',#2873,1.25038079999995);
#2875=CARTESIAN_POINT('',(7.45972342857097,4.,11.79));
#2876=VERTEX_POINT('',#2875);
#2877=EDGE_CURVE('E1080',#2876,#2876,#2874,.T.);
#2878=ORIENTED_EDGE('',*,*,#2877,.F.);
#2879=EDGE_LOOP('',(#2878));
#2880=FACE_BOUND('',#2879,.T.);
#2881=ORIENTED_EDGE('',*,*,#31,.T.);
#2882=EDGE_LOOP('',(#2881));
#2883=FACE_BOUND('',#2882,.T.);
#2884=ADVANCED_FACE('F2008',(#2880,#2883),#2869,.F.);
#2885=CARTESIAN_POINT('',(-5.9,4.,11.79));
#2886=DIRECTION('',(0.,0.,1.));
#2887=DIRECTION('',(1.,0.,0.));
#2888=AXIS2_PLACEMENT_3D('',#2885,#2886,#2887);
#2889=PLANE('',#2888);
#2890=ORIENTED_EDGE('',*,*,#2849,.F.);
#2891=EDGE_LOOP('',(#2890));
#2892=FACE_BOUND('',#2891,.T.);
#2893=ORIENTED_EDGE('',*,*,#2877,.T.);
#2894=EDGE_LOOP('',(#2893));
#2895=FACE_BOUND('',#2894,.T.);
#2896=ADVANCED_FACE('F1760',(#2892,#2895),#2889,.T.);
#2897=ORIENTED_EDGE('',*,*,#2860,.T.);
#2898=EDGE_LOOP('',(#2897));
#2899=FACE_BOUND('',#2898,.T.);
#2900=ADVANCED_FACE('F1749',(#2899),#23,.T.);
#2901=CARTESIAN_POINT('',(-5.73923675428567,2.99460471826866,11.79));
#2902=DIRECTION('',(1.,0.,0.));
#2903=DIRECTION('',(0.,0.,-1.));
#2904=AXIS2_PLACEMENT_3D('',#2901,#2902,#2903);
#2905=PLANE('',#2904);
#2906=ORIENTED_EDGE('',*,*,#487,.F.);
#2907=DIRECTION('',(0.,0.,1.));
#2908=VECTOR('',#2907,1.);
#2909=CARTESIAN_POINT('',(-5.73923675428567,2.99460471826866,11.79));
#2910=LINE('',#2909,#2908);
#2911=CARTESIAN_POINT('',(-5.73923675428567,2.99460471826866,11.79));
#2912=VERTEX_POINT('',#2911);
#2913=EDGE_CURVE('E1060',#2912,#476,#2910,.T.);
#2914=ORIENTED_EDGE('',*,*,#2913,.F.);
#2915=DIRECTION('',(0.,1.,0.));
#2916=VECTOR('',#2915,1.);
#2917=CARTESIAN_POINT('',(-5.73923675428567,2.99460471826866,11.79));
#2918=LINE('',#2917,#2916);
#2919=CARTESIAN_POINT('',(-5.73923675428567,3.29465412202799,11.79));
#2920=VERTEX_POINT('',#2919);
#2921=EDGE_CURVE('E1067',#2912,#2920,#2918,.T.);
#2922=ORIENTED_EDGE('',*,*,#2921,.T.);
#2923=DIRECTION('',(0.,0.,1.));
#2924=VECTOR('',#2923,1.);
#2925=CARTESIAN_POINT('',(-5.73923675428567,3.29465412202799,11.79));
#2926=LINE('',#2925,#2924);
#2927=EDGE_CURVE('E1050',#2920,#486,#2926,.T.);
#2928=ORIENTED_EDGE('',*,*,#2927,.T.);
#2929=EDGE_LOOP('',(#2906,#2914,#2922,#2928));
#2930=FACE_BOUND('',#2929,.T.);
#2931=ADVANCED_FACE('F1759',(#2930),#2905,.T.);
#2932=CARTESIAN_POINT('',(-5.9,4.,11.79));
#2933=DIRECTION('',(0.,0.,1.));
#2934=DIRECTION('',(1.,0.,0.));
#2935=AXIS2_PLACEMENT_3D('',#2932,#2933,#2934);
#2936=CYLINDRICAL_SURFACE('',#2935,0.723434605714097);
#2937=ORIENTED_EDGE('',*,*,#496,.F.);
#2938=ORIENTED_EDGE('',*,*,#2927,.F.);
#2939=CARTESIAN_POINT('',(-5.9,4.,11.79));
#2940=DIRECTION('',(0.,0.,1.));
#2941=DIRECTION('',(1.,0.,0.));
#2942=AXIS2_PLACEMENT_3D('',#2939,#2940,#2941);
#2943=CIRCLE('',#2942,0.723434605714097);
#2944=CARTESIAN_POINT('',(-5.1765653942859,4.,11.79));
#2945=VERTEX_POINT('',#2944);
#2946=EDGE_CURVE('E1091',#2920,#2945,#2943,.T.);
#2947=ORIENTED_EDGE('',*,*,#2946,.T.);
#2948=DIRECTION('',(0.,0.,1.));
#2949=VECTOR('',#2948,1.);
#2950=CARTESIAN_POINT('',(-5.1765653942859,4.,11.79));
#2951=LINE('',#2950,#2949);
#2952=EDGE_CURVE('E1052',#2945,#495,#2951,.T.);
#2953=ORIENTED_EDGE('',*,*,#2952,.T.);
#2954=EDGE_LOOP('',(#2937,#2938,#2947,#2953));
#2955=FACE_BOUND('',#2954,.T.);
#2956=ADVANCED_FACE('F1981',(#2955),#2936,.T.);
#2957=CARTESIAN_POINT('',(-5.1765653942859,4.16076324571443,11.79));
#2958=DIRECTION('',(-1.,0.,0.));
#2959=DIRECTION('',(0.,0.,1.));
#2960=AXIS2_PLACEMENT_3D('',#2957,#2958,#2959);
#2961=PLANE('',#2960);
#2962=ORIENTED_EDGE('',*,*,#504,.T.);
#2963=ORIENTED_EDGE('',*,*,#2952,.F.);
#2964=DIRECTION('',(0.,-1.,0.));
#2965=VECTOR('',#2964,1.);
#2966=CARTESIAN_POINT('',(-5.1765653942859,4.16076324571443,11.79));
#2967=LINE('',#2966,#2965);
#2968=CARTESIAN_POINT('',(-5.1765653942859,4.16076324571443,11.79));
#2969=VERTEX_POINT('',#2968);
#2970=EDGE_CURVE('E1088',#2969,#2945,#2967,.T.);
#2971=ORIENTED_EDGE('',*,*,#2970,.F.);
#2972=DIRECTION('',(0.,0.,1.));
#2973=VECTOR('',#2972,1.);
#2974=CARTESIAN_POINT('',(-5.1765653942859,4.16076324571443,11.79));
#2975=LINE('',#2974,#2973);
#2976=EDGE_CURVE('E1054',#2969,#503,#2975,.T.);
#2977=ORIENTED_EDGE('',*,*,#2976,.T.);
#2978=EDGE_LOOP('',(#2962,#2963,#2971,#2977));
#2979=FACE_BOUND('',#2978,.T.);
#2980=ADVANCED_FACE('F1983',(#2979),#2961,.F.);
#2981=CARTESIAN_POINT('',(-5.1765653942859,4.16076324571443,11.79));
#2982=DIRECTION('',(0.,-1.,0.));
#2983=DIRECTION('',(0.,0.,-1.));
#2984=AXIS2_PLACEMENT_3D('',#2981,#2982,#2983);
#2985=PLANE('',#2984);
#2986=ORIENTED_EDGE('',*,*,#512,.F.);
#2987=ORIENTED_EDGE('',*,*,#2976,.F.);
#2988=DIRECTION('',(1.,0.,0.));
#2989=VECTOR('',#2988,1.);
#2990=CARTESIAN_POINT('',(-5.1765653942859,4.16076324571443,11.79));
#2991=LINE('',#2990,#2989);
#2992=CARTESIAN_POINT('',(-4.88183277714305,4.16076324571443,11.79));
#2993=VERTEX_POINT('',#2992);
#2994=EDGE_CURVE('E1086',#2969,#2993,#2991,.T.);
#2995=ORIENTED_EDGE('',*,*,#2994,.T.);
#2996=DIRECTION('',(0.,0.,1.));
#2997=VECTOR('',#2996,1.);
#2998=CARTESIAN_POINT('',(-4.88183277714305,4.16076324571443,11.79));
#2999=LINE('',#2998,#2997);
#3000=EDGE_CURVE('E1056',#2993,#511,#2999,.T.);
#3001=ORIENTED_EDGE('',*,*,#3000,.T.);
#3002=EDGE_LOOP('',(#2986,#2987,#2995,#3001));
#3003=FACE_BOUND('',#3002,.T.);
#3004=ADVANCED_FACE('F1987',(#3003),#2985,.T.);
#3005=CARTESIAN_POINT('',(-4.88183277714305,4.,11.79));
#3006=DIRECTION('',(1.,0.,0.));
#3007=DIRECTION('',(0.,0.,-1.));
#3008=AXIS2_PLACEMENT_3D('',#3005,#3006,#3007);
#3009=PLANE('',#3008);
#3010=ORIENTED_EDGE('',*,*,#518,.T.);
#3011=ORIENTED_EDGE('',*,*,#3000,.F.);
#3012=DIRECTION('',(0.,1.,0.));
#3013=VECTOR('',#3012,1.);
#3014=CARTESIAN_POINT('',(-4.88183277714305,4.,11.79));
#3015=LINE('',#3014,#3013);
#3016=CARTESIAN_POINT('',(-4.88183277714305,4.,11.79));
#3017=VERTEX_POINT('',#3016);
#3018=EDGE_CURVE('E1083',#3017,#2993,#3015,.T.);
#3019=ORIENTED_EDGE('',*,*,#3018,.F.);
#3020=DIRECTION('',(0.,0.,1.));
#3021=VECTOR('',#3020,1.);
#3022=CARTESIAN_POINT('',(-4.88183277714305,4.,11.79));
#3023=LINE('',#3022,#3021);
#3024=EDGE_CURVE('E1058',#3017,#478,#3023,.T.);
#3025=ORIENTED_EDGE('',*,*,#3024,.T.);
#3026=EDGE_LOOP('',(#3010,#3011,#3019,#3025));
#3027=FACE_BOUND('',#3026,.T.);
#3028=ADVANCED_FACE('F1990',(#3027),#3009,.F.);
#3029=CARTESIAN_POINT('',(-5.9,4.,11.79));
#3030=DIRECTION('',(0.,0.,1.));
#3031=DIRECTION('',(1.,0.,0.));
#3032=AXIS2_PLACEMENT_3D('',#3029,#3030,#3031);
#3033=CYLINDRICAL_SURFACE('',#3032,1.01816722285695);
#3034=ORIENTED_EDGE('',*,*,#479,.T.);
#3035=ORIENTED_EDGE('',*,*,#3024,.F.);
#3036=CARTESIAN_POINT('',(-5.9,4.,11.79));
#3037=DIRECTION('',(0.,0.,1.));
#3038=DIRECTION('',(1.,0.,0.));
#3039=AXIS2_PLACEMENT_3D('',#3036,#3037,#3038);
#3040=CIRCLE('',#3039,1.01816722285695);
#3041=EDGE_CURVE('E1062',#2912,#3017,#3040,.T.);
#3042=ORIENTED_EDGE('',*,*,#3041,.F.);
#3043=ORIENTED_EDGE('',*,*,#2913,.T.);
#3044=EDGE_LOOP('',(#3034,#3035,#3042,#3043));
#3045=FACE_BOUND('',#3044,.T.);
#3046=ADVANCED_FACE('F1970',(#3045),#3033,.F.);
#3047=CARTESIAN_POINT('',(-5.9,4.,11.79));
#3048=DIRECTION('',(0.,0.,1.));
#3049=DIRECTION('',(1.,0.,0.));
#3050=AXIS2_PLACEMENT_3D('',#3047,#3048,#3049);
#3051=PLANE('',#3050);
#3052=ORIENTED_EDGE('',*,*,#2921,.F.);
#3053=ORIENTED_EDGE('',*,*,#3041,.T.);
#3054=ORIENTED_EDGE('',*,*,#3018,.T.);
#3055=ORIENTED_EDGE('',*,*,#2994,.F.);
#3056=ORIENTED_EDGE('',*,*,#2970,.T.);
#3057=ORIENTED_EDGE('',*,*,#2946,.F.);
#3058=EDGE_LOOP('',(#3052,#3053,#3054,#3055,#3056,#3057));
#3059=FACE_BOUND('',#3058,.T.);
#3060=ADVANCED_FACE('F1976',(#3059),#3051,.T.);
#3061=CARTESIAN_POINT('',(-14.,5.5,-1.44337567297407));
#3062=DIRECTION('',(-0.500000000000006,0.,0.866025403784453));
#3063=DIRECTION('',(0.866025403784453,0.,0.500000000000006));
#3064=AXIS2_PLACEMENT_3D('',#3061,#3062,#3063);
#3065=PLANE('',#3064);
#3066=DIRECTION('',(0.,1.,0.));
#3067=VECTOR('',#3066,1.);
#3068=CARTESIAN_POINT('',(-12.75,5.5,-0.721687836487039));
#3069=LINE('',#3068,#3067);
#3070=CARTESIAN_POINT('',(-12.75,5.5,-0.721687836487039));
#3071=VERTEX_POINT('',#3070);
#3072=CARTESIAN_POINT('',(-12.75,7.,-0.721687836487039));
#3073=VERTEX_POINT('',#3072);
#3074=EDGE_CURVE('E1033',#3071,#3073,#3069,.T.);
#3075=ORIENTED_EDGE('',*,*,#3074,.T.);
#3076=DIRECTION('',(0.866025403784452,0.,0.500000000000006));
#3077=VECTOR('',#3076,1.);
#3078=CARTESIAN_POINT('',(-14.,7.,-1.44337567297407));
#3079=LINE('',#3078,#3077);
#3080=CARTESIAN_POINT('',(-14.,7.,-1.44337567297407));
#3081=VERTEX_POINT('',#3080);
#3082=EDGE_CURVE('E986',#3081,#3073,#3079,.T.);
#3083=ORIENTED_EDGE('',*,*,#3082,.F.);
#3084=DIRECTION('',(0.,1.,0.));
#3085=VECTOR('',#3084,1.);
#3086=CARTESIAN_POINT('',(-14.,5.5,-1.44337567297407));
#3087=LINE('',#3086,#3085);
#3088=CARTESIAN_POINT('',(-14.,5.5,-1.44337567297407));
#3089=VERTEX_POINT('',#3088);
#3090=EDGE_CURVE('E1008',#3089,#3081,#3087,.T.);
#3091=ORIENTED_EDGE('',*,*,#3090,.F.);
#3092=DIRECTION('',(0.866025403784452,0.,0.500000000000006));
#3093=VECTOR('',#3092,1.);
#3094=CARTESIAN_POINT('',(-14.,5.5,-1.44337567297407));
#3095=LINE('',#3094,#3093);
#3096=EDGE_CURVE('E990',#3089,#3071,#3095,.T.);
#3097=ORIENTED_EDGE('',*,*,#3096,.T.);
#3098=EDGE_LOOP('',(#3075,#3083,#3091,#3097));
#3099=FACE_BOUND('',#3098,.T.);
#3100=ADVANCED_FACE('F2004',(#3099),#3065,.T.);
#3101=CARTESIAN_POINT('',(-12.75,5.5,0.721687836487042));
#3102=DIRECTION('',(1.00000000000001,0.,0.));
#3103=DIRECTION('',(0.,0.,-1.00000000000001));
#3104=AXIS2_PLACEMENT_3D('',#3101,#3102,#3103);
#3105=PLANE('',#3104);
#3106=DIRECTION('',(0.,1.,0.));
#3107=VECTOR('',#3106,1.);
#3108=CARTESIAN_POINT('',(-12.75,5.5,0.721687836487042));
#3109=LINE('',#3108,#3107);
#3110=CARTESIAN_POINT('',(-12.75,5.5,0.721687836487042));
#3111=VERTEX_POINT('',#3110);
#3112=CARTESIAN_POINT('',(-12.75,7.,0.721687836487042));
#3113=VERTEX_POINT('',#3112);
#3114=EDGE_CURVE('E1031',#3111,#3113,#3109,.T.);
#3115=ORIENTED_EDGE('',*,*,#3114,.T.);
#3116=DIRECTION('',(0.,0.,-1.00000000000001));
#3117=VECTOR('',#3116,1.);
#3118=CARTESIAN_POINT('',(-12.75,7.,0.721687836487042));
#3119=LINE('',#3118,#3117);
#3120=EDGE_CURVE('E1000',#3113,#3073,#3119,.T.);
#3121=ORIENTED_EDGE('',*,*,#3120,.T.);
#3122=ORIENTED_EDGE('',*,*,#3074,.F.);
#3123=DIRECTION('',(0.,0.,-1.00000000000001));
#3124=VECTOR('',#3123,1.);
#3125=CARTESIAN_POINT('',(-12.75,5.5,0.721687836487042));
#3126=LINE('',#3125,#3124);
#3127=EDGE_CURVE('E1018',#3111,#3071,#3126,.T.);
#3128=ORIENTED_EDGE('',*,*,#3127,.F.);
#3129=EDGE_LOOP('',(#3115,#3121,#3122,#3128));
#3130=FACE_BOUND('',#3129,.T.);
#3131=ADVANCED_FACE('F2873',(#3130),#3105,.F.);
#3132=CARTESIAN_POINT('',(-14.,5.5,1.44337567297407));
#3133=DIRECTION('',(0.500000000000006,0.,0.866025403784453));
#3134=DIRECTION('',(0.866025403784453,0.,-0.500000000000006));
#3135=AXIS2_PLACEMENT_3D('',#3132,#3133,#3134);
#3136=PLANE('',#3135);
#3137=DIRECTION('',(0.,1.,0.));
#3138=VECTOR('',#3137,1.);
#3139=CARTESIAN_POINT('',(-14.,5.5,1.44337567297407));
#3140=LINE('',#3139,#3138);
#3141=CARTESIAN_POINT('',(-14.,5.5,1.44337567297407));
#3142=VERTEX_POINT('',#3141);
#3143=CARTESIAN_POINT('',(-14.,7.,1.44337567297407));
#3144=VERTEX_POINT('',#3143);
#3145=EDGE_CURVE('E1029',#3142,#3144,#3140,.T.);
#3146=ORIENTED_EDGE('',*,*,#3145,.T.);
#3147=DIRECTION('',(0.866025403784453,0.,-0.500000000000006));
#3148=VECTOR('',#3147,1.);
#3149=CARTESIAN_POINT('',(-14.,7.,1.44337567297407));
#3150=LINE('',#3149,#3148);
#3151=EDGE_CURVE('E997',#3144,#3113,#3150,.T.);
#3152=ORIENTED_EDGE('',*,*,#3151,.T.);
#3153=ORIENTED_EDGE('',*,*,#3114,.F.);
#3154=DIRECTION('',(0.866025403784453,0.,-0.500000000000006));
#3155=VECTOR('',#3154,1.);
#3156=CARTESIAN_POINT('',(-14.,5.5,1.44337567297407));
#3157=LINE('',#3156,#3155);
#3158=EDGE_CURVE('E1015',#3142,#3111,#3157,.T.);
#3159=ORIENTED_EDGE('',*,*,#3158,.F.);
#3160=EDGE_LOOP('',(#3146,#3152,#3153,#3159));
#3161=FACE_BOUND('',#3160,.T.);
#3162=ADVANCED_FACE('F2876',(#3161),#3136,.F.);
#3163=CARTESIAN_POINT('',(-14.,5.5,1.44337567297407));
#3164=DIRECTION('',(0.500000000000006,0.,-0.866025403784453));
#3165=DIRECTION('',(-0.866025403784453,0.,-0.500000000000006));
#3166=AXIS2_PLACEMENT_3D('',#3163,#3164,#3165);
#3167=PLANE('',#3166);
#3168=DIRECTION('',(0.,1.,0.));
#3169=VECTOR('',#3168,1.);
#3170=CARTESIAN_POINT('',(-15.25,5.5,0.721687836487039));
#3171=LINE('',#3170,#3169);
#3172=CARTESIAN_POINT('',(-15.25,5.5,0.721687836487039));
#3173=VERTEX_POINT('',#3172);
#3174=CARTESIAN_POINT('',(-15.25,7.,0.721687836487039));
#3175=VERTEX_POINT('',#3174);
#3176=EDGE_CURVE('E1027',#3173,#3175,#3171,.T.);
#3177=ORIENTED_EDGE('',*,*,#3176,.T.);
#3178=DIRECTION('',(-0.866025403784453,0.,-0.500000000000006));
#3179=VECTOR('',#3178,1.);
#3180=CARTESIAN_POINT('',(-14.,7.,1.44337567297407));
#3181=LINE('',#3180,#3179);
#3182=EDGE_CURVE('E994',#3144,#3175,#3181,.T.);
#3183=ORIENTED_EDGE('',*,*,#3182,.F.);
#3184=ORIENTED_EDGE('',*,*,#3145,.F.);
#3185=DIRECTION('',(-0.866025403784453,0.,-0.500000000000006));
#3186=VECTOR('',#3185,1.);
#3187=CARTESIAN_POINT('',(-14.,5.5,1.44337567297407));
#3188=LINE('',#3187,#3186);
#3189=EDGE_CURVE('E1012',#3142,#3173,#3188,.T.);
#3190=ORIENTED_EDGE('',*,*,#3189,.T.);
#3191=EDGE_LOOP('',(#3177,#3183,#3184,#3190));
#3192=FACE_BOUND('',#3191,.T.);
#3193=ADVANCED_FACE('F2880',(#3192),#3167,.T.);
#3194=CARTESIAN_POINT('',(-15.25,5.5,-0.72168783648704));
#3195=DIRECTION('',(-1.00000000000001,0.,0.));
#3196=DIRECTION('',(0.,0.,1.00000000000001));
#3197=AXIS2_PLACEMENT_3D('',#3194,#3195,#3196);
#3198=PLANE('',#3197);
#3199=DIRECTION('',(0.,1.,0.));
#3200=VECTOR('',#3199,1.);
#3201=CARTESIAN_POINT('',(-15.25,5.5,-0.72168783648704));
#3202=LINE('',#3201,#3200);
#3203=CARTESIAN_POINT('',(-15.25,5.5,-0.72168783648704));
#3204=VERTEX_POINT('',#3203);
#3205=CARTESIAN_POINT('',(-15.25,7.,-0.72168783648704));
#3206=VERTEX_POINT('',#3205);
#3207=EDGE_CURVE('E1025',#3204,#3206,#3202,.T.);
#3208=ORIENTED_EDGE('',*,*,#3207,.T.);
#3209=DIRECTION('',(0.,0.,1.00000000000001));
#3210=VECTOR('',#3209,1.);
#3211=CARTESIAN_POINT('',(-15.25,7.,-0.72168783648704));
#3212=LINE('',#3211,#3210);
#3213=EDGE_CURVE('E991',#3206,#3175,#3212,.T.);
#3214=ORIENTED_EDGE('',*,*,#3213,.T.);
#3215=ORIENTED_EDGE('',*,*,#3176,.F.);
#3216=DIRECTION('',(0.,0.,1.00000000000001));
#3217=VECTOR('',#3216,1.);
#3218=CARTESIAN_POINT('',(-15.25,5.5,-0.72168783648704));
#3219=LINE('',#3218,#3217);
#3220=EDGE_CURVE('E1009',#3204,#3173,#3219,.T.);
#3221=ORIENTED_EDGE('',*,*,#3220,.F.);
#3222=EDGE_LOOP('',(#3208,#3214,#3215,#3221));
#3223=FACE_BOUND('',#3222,.T.);
#3224=ADVANCED_FACE('F2884',(#3223),#3198,.F.);
#3225=CARTESIAN_POINT('',(-14.,5.5,-1.44337567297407));
#3226=DIRECTION('',(-0.500000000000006,0.,-0.866025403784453));
#3227=DIRECTION('',(-0.866025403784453,0.,0.500000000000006));
#3228=AXIS2_PLACEMENT_3D('',#3225,#3226,#3227);
#3229=PLANE('',#3228);
#3230=DIRECTION('',(-0.866025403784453,0.,0.500000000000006));
#3231=VECTOR('',#3230,1.);
#3232=CARTESIAN_POINT('',(-14.,5.5,-1.44337567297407));
#3233=LINE('',#3232,#3231);
#3234=EDGE_CURVE('E1005',#3089,#3204,#3233,.T.);
#3235=ORIENTED_EDGE('',*,*,#3234,.F.);
#3236=ORIENTED_EDGE('',*,*,#3090,.T.);
#3237=DIRECTION('',(-0.866025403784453,0.,0.500000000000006));
#3238=VECTOR('',#3237,1.);
#3239=CARTESIAN_POINT('',(-14.,7.,-1.44337567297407));
#3240=LINE('',#3239,#3238);
#3241=EDGE_CURVE('E987',#3081,#3206,#3240,.T.);
#3242=ORIENTED_EDGE('',*,*,#3241,.T.);
#3243=ORIENTED_EDGE('',*,*,#3207,.F.);
#3244=EDGE_LOOP('',(#3235,#3236,#3242,#3243));
#3245=FACE_BOUND('',#3244,.T.);
#3246=ADVANCED_FACE('F2864',(#3245),#3229,.F.);
#3247=CARTESIAN_POINT('',(-12.75,5.5,-0.721687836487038));
#3248=DIRECTION('',(0.,1.,0.));
#3249=DIRECTION('',(1.00000000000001,0.,0.));
#3250=AXIS2_PLACEMENT_3D('',#3247,#3248,#3249);
#3251=PLANE('',#3250);
#3252=ORIENTED_EDGE('',*,*,#3096,.F.);
#3253=ORIENTED_EDGE('',*,*,#3234,.T.);
#3254=ORIENTED_EDGE('',*,*,#3220,.T.);
#3255=ORIENTED_EDGE('',*,*,#3189,.F.);
#3256=ORIENTED_EDGE('',*,*,#3158,.T.);
#3257=ORIENTED_EDGE('',*,*,#3127,.T.);
#3258=EDGE_LOOP('',(#3252,#3253,#3254,#3255,#3256,#3257));
#3259=FACE_BOUND('',#3258,.T.);
#3260=ADVANCED_FACE('F2862',(#3259),#3251,.T.);
#3261=CARTESIAN_POINT('',(-14.,7.,0.));
#3262=DIRECTION('',(0.,1.,0.));
#3263=DIRECTION('',(1.00000000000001,0.,0.));
#3264=AXIS2_PLACEMENT_3D('',#3261,#3262,#3263);
#3265=PLANE('',#3264);
#3266=CARTESIAN_POINT('',(-14.,7.,0.));
#3267=DIRECTION('',(0.,1.,0.));
#3268=DIRECTION('',(1.00000000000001,0.,0.));
#3269=AXIS2_PLACEMENT_3D('',#3266,#3267,#3268);
#3270=CIRCLE('',#3269,2.75);
#3271=CARTESIAN_POINT('',(-11.25,7.,0.));
#3272=VERTEX_POINT('',#3271);
#3273=EDGE_CURVE('E1035',#3272,#3272,#3270,.T.);
#3274=ORIENTED_EDGE('',*,*,#3273,.T.);
#3275=EDGE_LOOP('',(#3274));
#3276=FACE_BOUND('',#3275,.T.);
#3277=ORIENTED_EDGE('',*,*,#3241,.F.);
#3278=ORIENTED_EDGE('',*,*,#3082,.T.);
#3279=ORIENTED_EDGE('',*,*,#3120,.F.);
#3280=ORIENTED_EDGE('',*,*,#3151,.F.);
#3281=ORIENTED_EDGE('',*,*,#3182,.T.);
#3282=ORIENTED_EDGE('',*,*,#3213,.F.);
#3283=EDGE_LOOP('',(#3277,#3278,#3279,#3280,#3281,#3282));
#3284=FACE_BOUND('',#3283,.T.);
#3285=ADVANCED_FACE('F2858',(#3276,#3284),#3265,.T.);
#3286=CARTESIAN_POINT('',(-14.,14.,0.));
#3287=DIRECTION('',(0.,1.,0.));
#3288=DIRECTION('',(1.00000000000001,0.,0.));
#3289=AXIS2_PLACEMENT_3D('',#3286,#3287,#3288);
#3290=CYLINDRICAL_SURFACE('',#3289,2.75);
#3291=CARTESIAN_POINT('',(-14.,4.,0.));
#3292=DIRECTION('',(0.,1.,0.));
#3293=DIRECTION('',(0.,0.,1.));
#3294=AXIS2_PLACEMENT_3D('',#3291,#3292,#3293);
#3295=CIRCLE('',#3294,2.75);
#3296=CARTESIAN_POINT('',(-14.,4.,2.75));
#3297=VERTEX_POINT('',#3296);
#3298=EDGE_CURVE('E983',#3297,#3297,#3295,.F.);
#3299=ORIENTED_EDGE('',*,*,#3298,.F.);
#3300=EDGE_LOOP('',(#3299));
#3301=FACE_BOUND('',#3300,.T.);
#3302=ORIENTED_EDGE('',*,*,#3273,.F.);
#3303=EDGE_LOOP('',(#3302));
#3304=FACE_BOUND('',#3303,.T.);
#3305=ADVANCED_FACE('F2861',(#3301,#3304),#3290,.T.);
#3306=CARTESIAN_POINT('',(14.,5.5,1.44337567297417));
#3307=DIRECTION('',(0.500000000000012,0.,-0.866025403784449));
#3308=DIRECTION('',(-0.866025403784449,0.,-0.500000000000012));
#3309=AXIS2_PLACEMENT_3D('',#3306,#3307,#3308);
#3310=PLANE('',#3309);
#3311=DIRECTION('',(0.,1.,0.));
#3312=VECTOR('',#3311,1.);
#3313=CARTESIAN_POINT('',(12.75,5.5,0.721687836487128));
#3314=LINE('',#3313,#3312);
#3315=CARTESIAN_POINT('',(12.75,5.5,0.721687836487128));
#3316=VERTEX_POINT('',#3315);
#3317=CARTESIAN_POINT('',(12.75,7.,0.721687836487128));
#3318=VERTEX_POINT('',#3317);
#3319=EDGE_CURVE('E965',#3316,#3318,#3314,.T.);
#3320=ORIENTED_EDGE('',*,*,#3319,.T.);
#3321=DIRECTION('',(-0.866025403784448,0.,-0.500000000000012));
#3322=VECTOR('',#3321,1.);
#3323=CARTESIAN_POINT('',(14.,7.,1.44337567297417));
#3324=LINE('',#3323,#3322);
#3325=CARTESIAN_POINT('',(14.,7.,1.44337567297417));
#3326=VERTEX_POINT('',#3325);
#3327=EDGE_CURVE('E918',#3326,#3318,#3324,.T.);
#3328=ORIENTED_EDGE('',*,*,#3327,.F.);
#3329=DIRECTION('',(0.,1.,0.));
#3330=VECTOR('',#3329,1.);
#3331=CARTESIAN_POINT('',(14.,5.5,1.44337567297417));
#3332=LINE('',#3331,#3330);
#3333=CARTESIAN_POINT('',(14.,5.5,1.44337567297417));
#3334=VERTEX_POINT('',#3333);
#3335=EDGE_CURVE('E940',#3334,#3326,#3332,.T.);
#3336=ORIENTED_EDGE('',*,*,#3335,.F.);
#3337=DIRECTION('',(-0.866025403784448,0.,-0.500000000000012));
#3338=VECTOR('',#3337,1.);
#3339=CARTESIAN_POINT('',(14.,5.5,1.44337567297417));
#3340=LINE('',#3339,#3338);
#3341=EDGE_CURVE('E922',#3334,#3316,#3340,.T.);
#3342=ORIENTED_EDGE('',*,*,#3341,.T.);
#3343=EDGE_LOOP('',(#3320,#3328,#3336,#3342));
#3344=FACE_BOUND('',#3343,.T.);
#3345=ADVANCED_FACE('F2867',(#3344),#3310,.T.);
#3346=CARTESIAN_POINT('',(12.75,5.5,-0.721687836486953));
#3347=DIRECTION('',(-1.00000000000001,0.,0.));
#3348=DIRECTION('',(0.,0.,1.00000000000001));
#3349=AXIS2_PLACEMENT_3D('',#3346,#3347,#3348);
#3350=PLANE('',#3349);
#3351=DIRECTION('',(0.,1.,0.));
#3352=VECTOR('',#3351,1.);
#3353=CARTESIAN_POINT('',(12.75,5.5,-0.721687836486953));
#3354=LINE('',#3353,#3352);
#3355=CARTESIAN_POINT('',(12.75,5.5,-0.721687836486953));
#3356=VERTEX_POINT('',#3355);
#3357=CARTESIAN_POINT('',(12.75,7.,-0.721687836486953));
#3358=VERTEX_POINT('',#3357);
#3359=EDGE_CURVE('E963',#3356,#3358,#3354,.T.);
#3360=ORIENTED_EDGE('',*,*,#3359,.T.);
#3361=DIRECTION('',(0.,0.,1.00000000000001));
#3362=VECTOR('',#3361,1.);
#3363=CARTESIAN_POINT('',(12.75,7.,-0.721687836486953));
#3364=LINE('',#3363,#3362);
#3365=EDGE_CURVE('E932',#3358,#3318,#3364,.T.);
#3366=ORIENTED_EDGE('',*,*,#3365,.T.);
#3367=ORIENTED_EDGE('',*,*,#3319,.F.);
#3368=DIRECTION('',(0.,0.,1.00000000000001));
#3369=VECTOR('',#3368,1.);
#3370=CARTESIAN_POINT('',(12.75,5.5,-0.721687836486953));
#3371=LINE('',#3370,#3369);
#3372=EDGE_CURVE('E950',#3356,#3316,#3371,.T.);
#3373=ORIENTED_EDGE('',*,*,#3372,.F.);
#3374=EDGE_LOOP('',(#3360,#3366,#3367,#3373));
#3375=FACE_BOUND('',#3374,.T.);
#3376=ADVANCED_FACE('F2924',(#3375),#3350,.F.);
#3377=CARTESIAN_POINT('',(14.,5.5,-1.44337567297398));
#3378=DIRECTION('',(-0.5,0.,-0.866025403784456));
#3379=DIRECTION('',(-0.866025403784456,0.,0.5));
#3380=AXIS2_PLACEMENT_3D('',#3377,#3378,#3379);
#3381=PLANE('',#3380);
#3382=DIRECTION('',(0.,1.,0.));
#3383=VECTOR('',#3382,1.);
#3384=CARTESIAN_POINT('',(14.,5.5,-1.44337567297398));
#3385=LINE('',#3384,#3383);
#3386=CARTESIAN_POINT('',(14.,5.5,-1.44337567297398));
#3387=VERTEX_POINT('',#3386);
#3388=CARTESIAN_POINT('',(14.,7.,-1.44337567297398));
#3389=VERTEX_POINT('',#3388);
#3390=EDGE_CURVE('E961',#3387,#3389,#3385,.T.);
#3391=ORIENTED_EDGE('',*,*,#3390,.T.);
#3392=DIRECTION('',(-0.866025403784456,0.,0.5));
#3393=VECTOR('',#3392,1.);
#3394=CARTESIAN_POINT('',(14.,7.,-1.44337567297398));
#3395=LINE('',#3394,#3393);
#3396=EDGE_CURVE('E929',#3389,#3358,#3395,.T.);
#3397=ORIENTED_EDGE('',*,*,#3396,.T.);
#3398=ORIENTED_EDGE('',*,*,#3359,.F.);
#3399=DIRECTION('',(-0.866025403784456,0.,0.5));
#3400=VECTOR('',#3399,1.);
#3401=CARTESIAN_POINT('',(14.,5.5,-1.44337567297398));
#3402=LINE('',#3401,#3400);
#3403=EDGE_CURVE('E947',#3387,#3356,#3402,.T.);
#3404=ORIENTED_EDGE('',*,*,#3403,.F.);
#3405=EDGE_LOOP('',(#3391,#3397,#3398,#3404));
#3406=FACE_BOUND('',#3405,.T.);
#3407=ADVANCED_FACE('F2927',(#3406),#3381,.F.);
#3408=CARTESIAN_POINT('',(14.,5.5,-1.44337567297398));
#3409=DIRECTION('',(-0.500000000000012,0.,0.866025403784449));
#3410=DIRECTION('',(0.866025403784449,0.,0.500000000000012));
#3411=AXIS2_PLACEMENT_3D('',#3408,#3409,#3410);
#3412=PLANE('',#3411);
#3413=DIRECTION('',(0.,1.,0.));
#3414=VECTOR('',#3413,1.);
#3415=CARTESIAN_POINT('',(15.25,5.5,-0.721687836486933));
#3416=LINE('',#3415,#3414);
#3417=CARTESIAN_POINT('',(15.25,5.5,-0.721687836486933));
#3418=VERTEX_POINT('',#3417);
#3419=CARTESIAN_POINT('',(15.25,7.,-0.721687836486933));
#3420=VERTEX_POINT('',#3419);
#3421=EDGE_CURVE('E959',#3418,#3420,#3416,.T.);
#3422=ORIENTED_EDGE('',*,*,#3421,.T.);
#3423=DIRECTION('',(0.866025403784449,0.,0.500000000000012));
#3424=VECTOR('',#3423,1.);
#3425=CARTESIAN_POINT('',(14.,7.,-1.44337567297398));
#3426=LINE('',#3425,#3424);
#3427=EDGE_CURVE('E926',#3389,#3420,#3426,.T.);
#3428=ORIENTED_EDGE('',*,*,#3427,.F.);
#3429=ORIENTED_EDGE('',*,*,#3390,.F.);
#3430=DIRECTION('',(0.866025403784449,0.,0.500000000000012));
#3431=VECTOR('',#3430,1.);
#3432=CARTESIAN_POINT('',(14.,5.5,-1.44337567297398));
#3433=LINE('',#3432,#3431);
#3434=EDGE_CURVE('E944',#3387,#3418,#3433,.T.);
#3435=ORIENTED_EDGE('',*,*,#3434,.T.);
#3436=EDGE_LOOP('',(#3422,#3428,#3429,#3435));
#3437=FACE_BOUND('',#3436,.T.);
#3438=ADVANCED_FACE('F2931',(#3437),#3412,.T.);
#3439=CARTESIAN_POINT('',(15.25,5.5,0.721687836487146));
#3440=DIRECTION('',(1.00000000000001,0.,0.));
#3441=DIRECTION('',(0.,0.,-1.00000000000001));
#3442=AXIS2_PLACEMENT_3D('',#3439,#3440,#3441);
#3443=PLANE('',#3442);
#3444=DIRECTION('',(0.,1.,0.));
#3445=VECTOR('',#3444,1.);
#3446=CARTESIAN_POINT('',(15.25,5.5,0.721687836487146));
#3447=LINE('',#3446,#3445);
#3448=CARTESIAN_POINT('',(15.25,5.5,0.721687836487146));
#3449=VERTEX_POINT('',#3448);
#3450=CARTESIAN_POINT('',(15.25,7.,0.721687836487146));
#3451=VERTEX_POINT('',#3450);
#3452=EDGE_CURVE('E957',#3449,#3451,#3447,.T.);
#3453=ORIENTED_EDGE('',*,*,#3452,.T.);
#3454=DIRECTION('',(0.,0.,-1.00000000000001));
#3455=VECTOR('',#3454,1.);
#3456=CARTESIAN_POINT('',(15.25,7.,0.721687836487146));
#3457=LINE('',#3456,#3455);
#3458=EDGE_CURVE('E923',#3451,#3420,#3457,.T.);
#3459=ORIENTED_EDGE('',*,*,#3458,.T.);
#3460=ORIENTED_EDGE('',*,*,#3421,.F.);
#3461=DIRECTION('',(0.,0.,-1.00000000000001));
#3462=VECTOR('',#3461,1.);
#3463=CARTESIAN_POINT('',(15.25,5.5,0.721687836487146));
#3464=LINE('',#3463,#3462);
#3465=EDGE_CURVE('E941',#3449,#3418,#3464,.T.);
#3466=ORIENTED_EDGE('',*,*,#3465,.F.);
#3467=EDGE_LOOP('',(#3453,#3459,#3460,#3466));
#3468=FACE_BOUND('',#3467,.T.);
#3469=ADVANCED_FACE('F2935',(#3468),#3443,.F.);
#3470=CARTESIAN_POINT('',(14.,5.5,1.44337567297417));
#3471=DIRECTION('',(0.5,0.,0.866025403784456));
#3472=DIRECTION('',(0.866025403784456,0.,-0.5));
#3473=AXIS2_PLACEMENT_3D('',#3470,#3471,#3472);
#3474=PLANE('',#3473);
#3475=DIRECTION('',(0.866025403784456,0.,-0.5));
#3476=VECTOR('',#3475,1.);
#3477=CARTESIAN_POINT('',(14.,5.5,1.44337567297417));
#3478=LINE('',#3477,#3476);
#3479=EDGE_CURVE('E937',#3334,#3449,#3478,.T.);
#3480=ORIENTED_EDGE('',*,*,#3479,.F.);
#3481=ORIENTED_EDGE('',*,*,#3335,.T.);
#3482=DIRECTION('',(0.866025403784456,0.,-0.5));
#3483=VECTOR('',#3482,1.);
#3484=CARTESIAN_POINT('',(14.,7.,1.44337567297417));
#3485=LINE('',#3484,#3483);
#3486=EDGE_CURVE('E919',#3326,#3451,#3485,.T.);
#3487=ORIENTED_EDGE('',*,*,#3486,.T.);
#3488=ORIENTED_EDGE('',*,*,#3452,.F.);
#3489=EDGE_LOOP('',(#3480,#3481,#3487,#3488));
#3490=FACE_BOUND('',#3489,.T.);
#3491=ADVANCED_FACE('F2916',(#3490),#3474,.F.);
#3492=CARTESIAN_POINT('',(12.75,5.5,0.721687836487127));
#3493=DIRECTION('',(0.,1.,0.));
#3494=DIRECTION('',(-1.00000000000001,0.,0.));
#3495=AXIS2_PLACEMENT_3D('',#3492,#3493,#3494);
#3496=PLANE('',#3495);
#3497=ORIENTED_EDGE('',*,*,#3341,.F.);
#3498=ORIENTED_EDGE('',*,*,#3479,.T.);
#3499=ORIENTED_EDGE('',*,*,#3465,.T.);
#3500=ORIENTED_EDGE('',*,*,#3434,.F.);
#3501=ORIENTED_EDGE('',*,*,#3403,.T.);
#3502=ORIENTED_EDGE('',*,*,#3372,.T.);
#3503=EDGE_LOOP('',(#3497,#3498,#3499,#3500,#3501,#3502));
#3504=FACE_BOUND('',#3503,.T.);
#3505=ADVANCED_FACE('F2914',(#3504),#3496,.T.);
#3506=CARTESIAN_POINT('',(14.,7.,0.));
#3507=DIRECTION('',(0.,1.,0.));
#3508=DIRECTION('',(-1.00000000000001,0.,0.));
#3509=AXIS2_PLACEMENT_3D('',#3506,#3507,#3508);
#3510=PLANE('',#3509);
#3511=CARTESIAN_POINT('',(14.,7.,0.));
#3512=DIRECTION('',(0.,1.,0.));
#3513=DIRECTION('',(-1.00000000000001,0.,0.));
#3514=AXIS2_PLACEMENT_3D('',#3511,#3512,#3513);
#3515=CIRCLE('',#3514,2.75);
#3516=CARTESIAN_POINT('',(11.25,7.,0.));
#3517=VERTEX_POINT('',#3516);
#3518=EDGE_CURVE('E967',#3517,#3517,#3515,.T.);
#3519=ORIENTED_EDGE('',*,*,#3518,.T.);
#3520=EDGE_LOOP('',(#3519));
#3521=FACE_BOUND('',#3520,.T.);
#3522=ORIENTED_EDGE('',*,*,#3486,.F.);
#3523=ORIENTED_EDGE('',*,*,#3327,.T.);
#3524=ORIENTED_EDGE('',*,*,#3365,.F.);
#3525=ORIENTED_EDGE('',*,*,#3396,.F.);
#3526=ORIENTED_EDGE('',*,*,#3427,.T.);
#3527=ORIENTED_EDGE('',*,*,#3458,.F.);
#3528=EDGE_LOOP('',(#3522,#3523,#3524,#3525,#3526,#3527));
#3529=FACE_BOUND('',#3528,.T.);
#3530=ADVANCED_FACE('F2910',(#3521,#3529),#3510,.T.);
#3531=CARTESIAN_POINT('',(14.,14.,0.));
#3532=DIRECTION('',(0.,1.,0.));
#3533=DIRECTION('',(-1.00000000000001,0.,0.));
#3534=AXIS2_PLACEMENT_3D('',#3531,#3532,#3533);
#3535=CYLINDRICAL_SURFACE('',#3534,2.75);
#3536=CARTESIAN_POINT('',(14.,4.,0.));
#3537=DIRECTION('',(0.,1.,0.));
#3538=DIRECTION('',(0.,0.,1.));
#3539=AXIS2_PLACEMENT_3D('',#3536,#3537,#3538);
#3540=CIRCLE('',#3539,2.75);
#3541=CARTESIAN_POINT('',(14.,4.,2.7500000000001));
#3542=VERTEX_POINT('',#3541);
#3543=EDGE_CURVE('E910',#3542,#3542,#3540,.F.);
#3544=ORIENTED_EDGE('',*,*,#3543,.F.);
#3545=EDGE_LOOP('',(#3544));
#3546=FACE_BOUND('',#3545,.T.);
#3547=ORIENTED_EDGE('',*,*,#3518,.F.);
#3548=EDGE_LOOP('',(#3547));
#3549=FACE_BOUND('',#3548,.T.);
#3550=ADVANCED_FACE('F2913',(#3546,#3549),#3535,.T.);
#3551=CARTESIAN_POINT('',(0.,0.,0.));
#3552=DIRECTION('',(0.,-1.,0.));
#3553=DIRECTION('',(1.,0.,0.));
#3554=AXIS2_PLACEMENT_3D('',#3551,#3552,#3553);
#3555=CYLINDRICAL_SURFACE('',#3554,9.);
#3556=CARTESIAN_POINT('',(0.,19.2,0.));
#3557=DIRECTION('',(0.,1.,0.));
#3558=DIRECTION('',(0.,0.,1.));
#3559=AXIS2_PLACEMENT_3D('',#3556,#3557,#3558);
#3560=CIRCLE('',#3559,9.);
#3561=CARTESIAN_POINT('',(0.,19.2,9.));
#3562=VERTEX_POINT('',#3561);
#3563=EDGE_CURVE('E907',#3562,#3562,#3560,.F.);
#3564=ORIENTED_EDGE('',*,*,#3563,.F.);
#3565=EDGE_LOOP('',(#3564));
#3566=FACE_BOUND('',#3565,.T.);
#3567=CARTESIAN_POINT('',(0.,28.,0.));
#3568=DIRECTION('',(0.,-1.,0.));
#3569=DIRECTION('',(0.,0.,-1.));
#3570=AXIS2_PLACEMENT_3D('',#3567,#3568,#3569);
#3571=CIRCLE('',#3570,9.);
#3572=CARTESIAN_POINT('',(0.,28.,-9.));
#3573=VERTEX_POINT('',#3572);
#3574=EDGE_CURVE('E3130',#3573,#3573,#3571,.T.);
#3575=ORIENTED_EDGE('',*,*,#3574,.T.);
#3576=EDGE_LOOP('',(#3575));
#3577=FACE_BOUND('',#3576,.T.);
#3578=ADVANCED_FACE('F2919',(#3566,#3577),#3555,.T.);
#3579=CARTESIAN_POINT('',(0.,19.2,0.));
#3580=DIRECTION('',(0.,1.,0.));
#3581=DIRECTION('',(0.,0.,1.));
#3582=AXIS2_PLACEMENT_3D('',#3579,#3580,#3581);
#3583=PLANE('',#3582);
#3584=CARTESIAN_POINT('',(0.,19.2,0.));
#3585=DIRECTION('',(0.,1.,0.));
#3586=DIRECTION('',(0.,0.,1.));
#3587=AXIS2_PLACEMENT_3D('',#3584,#3585,#3586);
#3588=CIRCLE('',#3587,9.5);
#3589=CARTESIAN_POINT('',(0.,19.2,9.5));
#3590=VERTEX_POINT('',#3589);
#3591=EDGE_CURVE('E852',#3590,#3590,#3588,.T.);
#3592=ORIENTED_EDGE('',*,*,#3591,.T.);
#3593=EDGE_LOOP('',(#3592));
#3594=FACE_BOUND('',#3593,.T.);
#3595=ORIENTED_EDGE('',*,*,#3563,.T.);
#3596=EDGE_LOOP('',(#3595));
#3597=FACE_BOUND('',#3596,.T.);
#3598=ADVANCED_FACE('F3060',(#3594,#3597),#3583,.T.);
#3599=CARTESIAN_POINT('',(0.,19.2,0.));
#3600=DIRECTION('',(0.,-1.,0.));
#3601=DIRECTION('',(0.,0.,-1.));
#3602=AXIS2_PLACEMENT_3D('',#3599,#3600,#3601);
#3603=CYLINDRICAL_SURFACE('',#3602,9.5);
#3604=CARTESIAN_POINT('',(0.,8.,0.));
#3605=DIRECTION('',(0.,1.,0.));
#3606=DIRECTION('',(0.,0.,1.));
#3607=AXIS2_PLACEMENT_3D('',#3604,#3605,#3606);
#3608=CIRCLE('',#3607,9.5);
#3609=CARTESIAN_POINT('',(0.,8.,9.5));
#3610=VERTEX_POINT('',#3609);
#3611=EDGE_CURVE('E914',#3610,#3610,#3608,.T.);
#3612=ORIENTED_EDGE('',*,*,#3611,.T.);
#3613=EDGE_LOOP('',(#3612));
#3614=FACE_BOUND('',#3613,.T.);
#3615=ORIENTED_EDGE('',*,*,#3591,.F.);
#3616=EDGE_LOOP('',(#3615));
#3617=FACE_BOUND('',#3616,.T.);
#3618=ADVANCED_FACE('F3025',(#3614,#3617),#3603,.T.);
#3619=CARTESIAN_POINT('',(0.,8.,0.));
#3620=DIRECTION('',(0.,1.,0.));
#3621=DIRECTION('',(0.,0.,1.));
#3622=AXIS2_PLACEMENT_3D('',#3619,#3620,#3621);
#3623=PLANE('',#3622);
#3624=CARTESIAN_POINT('',(0.,8.,0.));
#3625=DIRECTION('',(0.,1.,0.));
#3626=DIRECTION('',(0.,0.,1.));
#3627=AXIS2_PLACEMENT_3D('',#3624,#3625,#3626);
#3628=CIRCLE('',#3627,17.5);
#3629=CARTESIAN_POINT('',(13.1909059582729,8.,11.5));
#3630=VERTEX_POINT('',#3629);
#3631=CARTESIAN_POINT('',(13.1909059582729,8.,-11.5));
#3632=VERTEX_POINT('',#3631);
#3633=EDGE_CURVE('E788',#3630,#3632,#3628,.T.);
#3634=ORIENTED_EDGE('',*,*,#3633,.T.);
#3635=DIRECTION('',(-1.,0.,0.));
#3636=VECTOR('',#3635,1.);
#3637=CARTESIAN_POINT('',(-13.4164078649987,8.,-11.5));
#3638=LINE('',#3637,#3636);
#3639=CARTESIAN_POINT('',(-13.1909059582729,8.,-11.5));
#3640=VERTEX_POINT('',#3639);
#3641=EDGE_CURVE('E791',#3632,#3640,#3638,.T.);
#3642=ORIENTED_EDGE('',*,*,#3641,.T.);
#3643=CARTESIAN_POINT('',(0.,8.,0.));
#3644=DIRECTION('',(0.,1.,0.));
#3645=DIRECTION('',(0.,0.,1.));
#3646=AXIS2_PLACEMENT_3D('',#3643,#3644,#3645);
#3647=CIRCLE('',#3646,17.5);
#3648=CARTESIAN_POINT('',(-13.1909059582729,8.,11.5));
#3649=VERTEX_POINT('',#3648);
#3650=EDGE_CURVE('E784',#3640,#3649,#3647,.T.);
#3651=ORIENTED_EDGE('',*,*,#3650,.T.);
#3652=DIRECTION('',(1.,0.,0.));
#3653=VECTOR('',#3652,1.);
#3654=CARTESIAN_POINT('',(13.4164078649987,8.,11.5));
#3655=LINE('',#3654,#3653);
#3656=EDGE_CURVE('E786',#3649,#3630,#3655,.T.);
#3657=ORIENTED_EDGE('',*,*,#3656,.T.);
#3658=EDGE_LOOP('',(#3634,#3642,#3651,#3657));
#3659=FACE_BOUND('',#3658,.T.);
#3660=CARTESIAN_POINT('',(-14.,8.,0.));
#3661=DIRECTION('',(0.,1.,0.));
#3662=DIRECTION('',(0.,0.,1.));
#3663=AXIS2_PLACEMENT_3D('',#3660,#3661,#3662);
#3664=CIRCLE('',#3663,3.2);
#3665=CARTESIAN_POINT('',(-14.,8.,3.2));
#3666=VERTEX_POINT('',#3665);
#3667=EDGE_CURVE('E889',#3666,#3666,#3664,.F.);
#3668=ORIENTED_EDGE('',*,*,#3667,.T.);
#3669=EDGE_LOOP('',(#3668));
#3670=FACE_BOUND('',#3669,.T.);
#3671=CARTESIAN_POINT('',(14.,8.,0.));
#3672=DIRECTION('',(0.,1.,0.));
#3673=DIRECTION('',(0.,0.,1.));
#3674=AXIS2_PLACEMENT_3D('',#3671,#3672,#3673);
#3675=CIRCLE('',#3674,3.2);
#3676=CARTESIAN_POINT('',(14.,8.,3.2));
#3677=VERTEX_POINT('',#3676);
#3678=EDGE_CURVE('E893',#3677,#3677,#3675,.F.);
#3679=ORIENTED_EDGE('',*,*,#3678,.T.);
#3680=EDGE_LOOP('',(#3679));
#3681=FACE_BOUND('',#3680,.T.);
#3682=ORIENTED_EDGE('',*,*,#3611,.F.);
#3683=EDGE_LOOP('',(#3682));
#3684=FACE_BOUND('',#3683,.T.);
#3685=ADVANCED_FACE('F3014',(#3659,#3670,#3681,#3684),#3623,.T.);
#3686=CARTESIAN_POINT('',(-24.5803666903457,28.,12.));
#3687=DIRECTION('',(0.,0.,-1.));
#3688=DIRECTION('',(-1.,0.,0.));
#3689=AXIS2_PLACEMENT_3D('',#3686,#3687,#3688);
#3690=PLANE('',#3689);
#3691=DIRECTION('',(0.,-1.,0.));
#3692=VECTOR('',#3691,1.);
#3693=CARTESIAN_POINT('',(-13.4164078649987,0.,12.));
#3694=LINE('',#3693,#3692);
#3695=CARTESIAN_POINT('',(-13.4164078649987,7.5,12.));
#3696=VERTEX_POINT('',#3695);
#3697=CARTESIAN_POINT('',(-13.4164078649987,0.5,12.));
#3698=VERTEX_POINT('',#3697);
#3699=EDGE_CURVE('E725',#3696,#3698,#3694,.T.);
#3700=ORIENTED_EDGE('',*,*,#3699,.T.);
#3701=DIRECTION('',(1.,0.,0.));
#3702=VECTOR('',#3701,1.);
#3703=CARTESIAN_POINT('',(13.4164078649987,0.5,12.));
#3704=LINE('',#3703,#3702);
#3705=CARTESIAN_POINT('',(13.4164078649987,0.5,12.));
#3706=VERTEX_POINT('',#3705);
#3707=EDGE_CURVE('E776',#3698,#3706,#3704,.T.);
#3708=ORIENTED_EDGE('',*,*,#3707,.T.);
#3709=DIRECTION('',(0.,-1.,0.));
#3710=VECTOR('',#3709,1.);
#3711=CARTESIAN_POINT('',(13.4164078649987,0.,12.));
#3712=LINE('',#3711,#3710);
#3713=CARTESIAN_POINT('',(13.4164078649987,7.5,12.));
#3714=VERTEX_POINT('',#3713);
#3715=EDGE_CURVE('E728',#3706,#3714,#3712,.F.);
#3716=ORIENTED_EDGE('',*,*,#3715,.T.);
#3717=DIRECTION('',(-1.,0.,0.));
#3718=VECTOR('',#3717,1.);
#3719=CARTESIAN_POINT('',(-13.4164078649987,7.5,12.));
#3720=LINE('',#3719,#3718);
#3721=EDGE_CURVE('E774',#3714,#3696,#3720,.T.);
#3722=ORIENTED_EDGE('',*,*,#3721,.T.);
#3723=EDGE_LOOP('',(#3700,#3708,#3716,#3722));
#3724=FACE_BOUND('',#3723,.T.);
#3725=CARTESIAN_POINT('',(6.,4.,12.));
#3726=DIRECTION('',(0.,0.,-1.));
#3727=DIRECTION('',(-1.,0.,0.));
#3728=AXIS2_PLACEMENT_3D('',#3725,#3726,#3727);
#3729=CIRCLE('',#3728,2.5);
#3730=CARTESIAN_POINT('',(6.,6.5,12.));
#3731=VERTEX_POINT('',#3730);
#3732=CARTESIAN_POINT('',(6.,1.5,12.));
#3733=VERTEX_POINT('',#3732);
#3734=EDGE_CURVE('E2988',#3731,#3733,#3729,.T.);
#3735=ORIENTED_EDGE('',*,*,#3734,.T.);
#3736=DIRECTION('',(-1.,0.,0.));
#3737=VECTOR('',#3736,1.);
#3738=CARTESIAN_POINT('',(6.,1.5,12.));
#3739=LINE('',#3738,#3737);
#3740=CARTESIAN_POINT('',(-6.,1.5,12.));
#3741=VERTEX_POINT('',#3740);
#3742=EDGE_CURVE('E712',#3733,#3741,#3739,.T.);
#3743=ORIENTED_EDGE('',*,*,#3742,.T.);
#3744=CARTESIAN_POINT('',(-6.,4.,12.));
#3745=DIRECTION('',(0.,0.,-1.));
#3746=DIRECTION('',(-1.,0.,0.));
#3747=AXIS2_PLACEMENT_3D('',#3744,#3745,#3746);
#3748=CIRCLE('',#3747,2.5);
#3749=CARTESIAN_POINT('',(-6.,6.5,12.));
#3750=VERTEX_POINT('',#3749);
#3751=EDGE_CURVE('E2998',#3741,#3750,#3748,.T.);
#3752=ORIENTED_EDGE('',*,*,#3751,.T.);
#3753=DIRECTION('',(1.,0.,0.));
#3754=VECTOR('',#3753,1.);
#3755=CARTESIAN_POINT('',(6.,6.5,12.));
#3756=LINE('',#3755,#3754);
#3757=EDGE_CURVE('E708',#3750,#3731,#3756,.T.);
#3758=ORIENTED_EDGE('',*,*,#3757,.T.);
#3759=EDGE_LOOP('',(#3735,#3743,#3752,#3758));
#3760=FACE_BOUND('',#3759,.T.);
#3761=ADVANCED_FACE('F3011',(#3724,#3760),#3690,.F.);
#3762=CARTESIAN_POINT('',(0.,0.,0.));
#3763=DIRECTION('',(0.,-1.,0.));
#3764=DIRECTION('',(1.,0.,0.));
#3765=AXIS2_PLACEMENT_3D('',#3762,#3763,#3764);
#3766=CYLINDRICAL_SURFACE('',#3765,18.);
#3767=DIRECTION('',(0.,-1.,0.));
#3768=VECTOR('',#3767,1.);
#3769=CARTESIAN_POINT('',(-13.4164078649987,0.,-12.));
#3770=LINE('',#3769,#3768);
#3771=CARTESIAN_POINT('',(-13.4164078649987,0.5,-12.));
#3772=VERTEX_POINT('',#3771);
#3773=CARTESIAN_POINT('',(-13.4164078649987,7.5,-12.));
#3774=VERTEX_POINT('',#3773);
#3775=EDGE_CURVE('E717',#3772,#3774,#3770,.F.);
#3776=ORIENTED_EDGE('',*,*,#3775,.F.);
#3777=CARTESIAN_POINT('',(0.,0.5,0.));
#3778=DIRECTION('',(0.,-1.,0.));
#3779=DIRECTION('',(1.,0.,0.));
#3780=AXIS2_PLACEMENT_3D('',#3777,#3778,#3779);
#3781=CIRCLE('',#3780,18.);
#3782=EDGE_CURVE('E772',#3772,#3698,#3781,.F.);
#3783=ORIENTED_EDGE('',*,*,#3782,.T.);
#3784=ORIENTED_EDGE('',*,*,#3699,.F.);
#3785=CARTESIAN_POINT('',(0.,7.5,0.));
#3786=DIRECTION('',(0.,1.,0.));
#3787=DIRECTION('',(-1.,0.,0.));
#3788=AXIS2_PLACEMENT_3D('',#3785,#3786,#3787);
#3789=CIRCLE('',#3788,18.);
#3790=EDGE_CURVE('E770',#3696,#3774,#3789,.F.);
#3791=ORIENTED_EDGE('',*,*,#3790,.T.);
#3792=EDGE_LOOP('',(#3776,#3783,#3784,#3791));
#3793=FACE_BOUND('',#3792,.T.);
#3794=ADVANCED_FACE('F3013',(#3793),#3766,.T.);
#3795=ORIENTED_EDGE('',*,*,#3715,.F.);
#3796=CARTESIAN_POINT('',(0.,0.5,0.));
#3797=DIRECTION('',(0.,-1.,0.));
#3798=DIRECTION('',(1.,0.,0.));
#3799=AXIS2_PLACEMENT_3D('',#3796,#3797,#3798);
#3800=CIRCLE('',#3799,18.);
#3801=CARTESIAN_POINT('',(13.4164078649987,0.5,-12.));
#3802=VERTEX_POINT('',#3801);
#3803=EDGE_CURVE('E781',#3706,#3802,#3800,.F.);
#3804=ORIENTED_EDGE('',*,*,#3803,.T.);
#3805=DIRECTION('',(0.,-1.,0.));
#3806=VECTOR('',#3805,1.);
#3807=CARTESIAN_POINT('',(13.4164078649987,0.,-12.));
#3808=LINE('',#3807,#3806);
#3809=CARTESIAN_POINT('',(13.4164078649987,7.5,-12.));
#3810=VERTEX_POINT('',#3809);
#3811=EDGE_CURVE('E713',#3810,#3802,#3808,.T.);
#3812=ORIENTED_EDGE('',*,*,#3811,.F.);
#3813=CARTESIAN_POINT('',(0.,7.5,0.));
#3814=DIRECTION('',(0.,1.,0.));
#3815=DIRECTION('',(-1.,0.,0.));
#3816=AXIS2_PLACEMENT_3D('',#3813,#3814,#3815);
#3817=CIRCLE('',#3816,18.);
#3818=EDGE_CURVE('E778',#3810,#3714,#3817,.F.);
#3819=ORIENTED_EDGE('',*,*,#3818,.T.);
#3820=EDGE_LOOP('',(#3795,#3804,#3812,#3819));
#3821=FACE_BOUND('',#3820,.T.);
#3822=ADVANCED_FACE('F3022',(#3821),#3766,.T.);
#3823=CARTESIAN_POINT('',(18.,0.,0.));
#3824=DIRECTION('',(0.,-1.,0.));
#3825=DIRECTION('',(1.,0.,0.));
#3826=AXIS2_PLACEMENT_3D('',#3823,#3824,#3825);
#3827=PLANE('',#3826);
#3828=CARTESIAN_POINT('',(14.,0.,0.));
#3829=DIRECTION('',(0.,-1.,0.));
#3830=DIRECTION('',(1.,0.,0.));
#3831=AXIS2_PLACEMENT_3D('',#3828,#3829,#3830);
#3832=CIRCLE('',#3831,1.95000000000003);
#3833=CARTESIAN_POINT('',(15.95,0.,0.));
#3834=VERTEX_POINT('',#3833);
#3835=EDGE_CURVE('E900',#3834,#3834,#3832,.F.);
#3836=ORIENTED_EDGE('',*,*,#3835,.T.);
#3837=EDGE_LOOP('',(#3836));
#3838=FACE_BOUND('',#3837,.T.);
#3839=CARTESIAN_POINT('',(-14.,0.,0.));
#3840=DIRECTION('',(0.,-1.,0.));
#3841=DIRECTION('',(1.,0.,0.));
#3842=AXIS2_PLACEMENT_3D('',#3839,#3840,#3841);
#3843=CIRCLE('',#3842,1.95);
#3844=CARTESIAN_POINT('',(-12.05,0.,0.));
#3845=VERTEX_POINT('',#3844);
#3846=EDGE_CURVE('E897',#3845,#3845,#3843,.F.);
#3847=ORIENTED_EDGE('',*,*,#3846,.T.);
#3848=EDGE_LOOP('',(#3847));
#3849=FACE_BOUND('',#3848,.T.);
#3850=CARTESIAN_POINT('',(0.,0.,0.));
#3851=DIRECTION('',(0.,-1.,0.));
#3852=DIRECTION('',(1.,0.,0.));
#3853=AXIS2_PLACEMENT_3D('',#3850,#3851,#3852);
#3854=CIRCLE('',#3853,17.5);
#3855=CARTESIAN_POINT('',(-13.1909059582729,0.,11.5));
#3856=VERTEX_POINT('',#3855);
#3857=CARTESIAN_POINT('',(-13.1909059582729,0.,-11.5));
#3858=VERTEX_POINT('',#3857);
#3859=EDGE_CURVE('E765',#3856,#3858,#3854,.T.);
#3860=ORIENTED_EDGE('',*,*,#3859,.T.);
#3861=DIRECTION('',(1.,0.,0.));
#3862=VECTOR('',#3861,1.);
#3863=CARTESIAN_POINT('',(13.4164078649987,0.,-11.5));
#3864=LINE('',#3863,#3862);
#3865=CARTESIAN_POINT('',(13.1909059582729,0.,-11.5));
#3866=VERTEX_POINT('',#3865);
#3867=EDGE_CURVE('E767',#3858,#3866,#3864,.T.);
#3868=ORIENTED_EDGE('',*,*,#3867,.T.);
#3869=CARTESIAN_POINT('',(0.,0.,0.));
#3870=DIRECTION('',(0.,-1.,0.));
#3871=DIRECTION('',(1.,0.,0.));
#3872=AXIS2_PLACEMENT_3D('',#3869,#3870,#3871);
#3873=CIRCLE('',#3872,17.5);
#3874=CARTESIAN_POINT('',(13.1909059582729,0.,11.5));
#3875=VERTEX_POINT('',#3874);
#3876=EDGE_CURVE('E761',#3866,#3875,#3873,.T.);
#3877=ORIENTED_EDGE('',*,*,#3876,.T.);
#3878=DIRECTION('',(-1.,0.,0.));
#3879=VECTOR('',#3878,1.);
#3880=CARTESIAN_POINT('',(-13.4164078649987,0.,11.5));
#3881=LINE('',#3880,#3879);
#3882=EDGE_CURVE('E763',#3875,#3856,#3881,.T.);
#3883=ORIENTED_EDGE('',*,*,#3882,.T.);
#3884=EDGE_LOOP('',(#3860,#3868,#3877,#3883));
#3885=FACE_BOUND('',#3884,.T.);
#3886=CARTESIAN_POINT('',(0.,0.,0.));
#3887=DIRECTION('',(0.,-1.,0.));
#3888=DIRECTION('',(1.,0.,0.));
#3889=AXIS2_PLACEMENT_3D('',#3886,#3887,#3888);
#3890=CIRCLE('',#3889,9.15);
#3891=CARTESIAN_POINT('',(9.15,0.,0.));
#3892=VERTEX_POINT('',#3891);
#3893=EDGE_CURVE('E746',#3892,#3892,#3890,.F.);
#3894=ORIENTED_EDGE('',*,*,#3893,.T.);
#3895=EDGE_LOOP('',(#3894));
#3896=FACE_BOUND('',#3895,.T.);
#3897=ADVANCED_FACE('F3051',(#3838,#3849,#3885,#3896),#3827,.T.);
#3898=CARTESIAN_POINT('',(0.,0.,0.));
#3899=DIRECTION('',(0.,-1.,0.));
#3900=DIRECTION('',(1.,0.,0.));
#3901=AXIS2_PLACEMENT_3D('',#3898,#3899,#3900);
#3902=CYLINDRICAL_SURFACE('',#3901,8.75);
#3903=CARTESIAN_POINT('',(0.,-0.4,0.));
#3904=DIRECTION('',(0.,-1.,0.));
#3905=DIRECTION('',(1.,0.,0.));
#3906=AXIS2_PLACEMENT_3D('',#3903,#3904,#3905);
#3907=CIRCLE('',#3906,8.75);
#3908=CARTESIAN_POINT('',(8.75,-0.4,0.));
#3909=VERTEX_POINT('',#3908);
#3910=EDGE_CURVE('E743',#3909,#3909,#3907,.T.);
#3911=ORIENTED_EDGE('',*,*,#3910,.T.);
#3912=EDGE_LOOP('',(#3911));
#3913=FACE_BOUND('',#3912,.T.);
#3914=CARTESIAN_POINT('',(0.,-1.7,0.));
#3915=DIRECTION('',(0.,-1.,0.));
#3916=DIRECTION('',(1.,0.,0.));
#3917=AXIS2_PLACEMENT_3D('',#3914,#3915,#3916);
#3918=CIRCLE('',#3917,8.75);
#3919=CARTESIAN_POINT('',(8.75,-1.7,0.));
#3920=VERTEX_POINT('',#3919);
#3921=EDGE_CURVE('E740',#3920,#3920,#3918,.F.);
#3922=ORIENTED_EDGE('',*,*,#3921,.T.);
#3923=EDGE_LOOP('',(#3922));
#3924=FACE_BOUND('',#3923,.T.);
#3925=ADVANCED_FACE('F3047',(#3913,#3924),#3902,.T.);
#3926=CARTESIAN_POINT('',(8.75,-2.,0.));
#3927=DIRECTION('',(0.,-1.,0.));
#3928=DIRECTION('',(1.,0.,0.));
#3929=AXIS2_PLACEMENT_3D('',#3926,#3927,#3928);
#3930=PLANE('',#3929);
#3931=CARTESIAN_POINT('',(0.,-2.,0.));
#3932=DIRECTION('',(0.,-1.,0.));
#3933=DIRECTION('',(1.,0.,0.));
#3934=AXIS2_PLACEMENT_3D('',#3931,#3932,#3933);
#3935=CIRCLE('',#3934,8.);
#3936=CARTESIAN_POINT('',(8.,-2.,0.));
#3937=VERTEX_POINT('',#3936);
#3938=EDGE_CURVE('E752',#3937,#3937,#3935,.F.);
#3939=ORIENTED_EDGE('',*,*,#3938,.T.);
#3940=EDGE_LOOP('',(#3939));
#3941=FACE_BOUND('',#3940,.T.);
#3942=CARTESIAN_POINT('',(0.,-2.,0.));
#3943=DIRECTION('',(0.,-1.,0.));
#3944=DIRECTION('',(1.,0.,0.));
#3945=AXIS2_PLACEMENT_3D('',#3942,#3943,#3944);
#3946=CIRCLE('',#3945,8.45);
#3947=CARTESIAN_POINT('',(8.45,-2.,0.));
#3948=VERTEX_POINT('',#3947);
#3949=EDGE_CURVE('E737',#3948,#3948,#3946,.T.);
#3950=ORIENTED_EDGE('',*,*,#3949,.T.);
#3951=EDGE_LOOP('',(#3950));
#3952=FACE_BOUND('',#3951,.T.);
#3953=ADVANCED_FACE('F3044',(#3941,#3952),#3930,.T.);
#3954=CARTESIAN_POINT('',(-24.5803666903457,28.,-12.));
#3955=DIRECTION('',(0.,0.,1.));
#3956=DIRECTION('',(1.,0.,0.));
#3957=AXIS2_PLACEMENT_3D('',#3954,#3955,#3956);
#3958=PLANE('',#3957);
#3959=ORIENTED_EDGE('',*,*,#3811,.T.);
#3960=DIRECTION('',(-1.,0.,0.));
#3961=VECTOR('',#3960,1.);
#3962=CARTESIAN_POINT('',(-13.4164078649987,0.5,-12.));
#3963=LINE('',#3962,#3961);
#3964=EDGE_CURVE('E758',#3802,#3772,#3963,.T.);
#3965=ORIENTED_EDGE('',*,*,#3964,.T.);
#3966=ORIENTED_EDGE('',*,*,#3775,.T.);
#3967=DIRECTION('',(1.,0.,0.));
#3968=VECTOR('',#3967,1.);
#3969=CARTESIAN_POINT('',(13.4164078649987,7.5,-12.));
#3970=LINE('',#3969,#3968);
#3971=EDGE_CURVE('E755',#3774,#3810,#3970,.T.);
#3972=ORIENTED_EDGE('',*,*,#3971,.T.);
#3973=EDGE_LOOP('',(#3959,#3965,#3966,#3972));
#3974=FACE_BOUND('',#3973,.T.);
#3975=ADVANCED_FACE('F3030',(#3974),#3958,.F.);
#3976=CARTESIAN_POINT('',(0.,-2.,0.));
#3977=DIRECTION('',(0.,1.,0.));
#3978=DIRECTION('',(-1.,0.,0.));
#3979=AXIS2_PLACEMENT_3D('',#3976,#3977,#3978);
#3980=CONICAL_SURFACE('',#3979,8.45,0.785398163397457);
#3981=ORIENTED_EDGE('',*,*,#3921,.F.);
#3982=EDGE_LOOP('',(#3981));
#3983=FACE_BOUND('',#3982,.T.);
#3984=ORIENTED_EDGE('',*,*,#3949,.F.);
#3985=EDGE_LOOP('',(#3984));
#3986=FACE_BOUND('',#3985,.T.);
#3987=ADVANCED_FACE('F3065',(#3983,#3986),#3980,.T.);
#3988=CARTESIAN_POINT('',(0.,-0.4,0.));
#3989=DIRECTION('',(0.,-1.,0.));
#3990=DIRECTION('',(1.,0.,0.));
#3991=AXIS2_PLACEMENT_3D('',#3988,#3989,#3990);
#3992=TOROIDAL_SURFACE('',#3991,9.15,0.4);
#3993=ORIENTED_EDGE('',*,*,#3893,.F.);
#3994=EDGE_LOOP('',(#3993));
#3995=FACE_BOUND('',#3994,.T.);
#3996=ORIENTED_EDGE('',*,*,#3910,.F.);
#3997=EDGE_LOOP('',(#3996));
#3998=FACE_BOUND('',#3997,.T.);
#3999=ADVANCED_FACE('F3068',(#3995,#3998),#3992,.F.);
#4000=CARTESIAN_POINT('',(0.,0.5,0.));
#4001=DIRECTION('',(0.,-1.,0.));
#4002=DIRECTION('',(1.,0.,0.));
#4003=AXIS2_PLACEMENT_3D('',#4000,#4001,#4002);
#4004=CYLINDRICAL_SURFACE('',#4003,7.5);
#4005=CARTESIAN_POINT('',(0.,0.,0.));
#4006=DIRECTION('',(0.,-1.,0.));
#4007=DIRECTION('',(0.,0.,-1.));
#4008=AXIS2_PLACEMENT_3D('',#4005,#4006,#4007);
#4009=CIRCLE('',#4008,7.5);
#4010=CARTESIAN_POINT('',(0.,0.,-7.5));
#4011=VERTEX_POINT('',#4010);
#4012=EDGE_CURVE('E911',#4011,#4011,#4009,.F.);
#4013=ORIENTED_EDGE('',*,*,#4012,.T.);
#4014=EDGE_LOOP('',(#4013));
#4015=FACE_BOUND('',#4014,.T.);
#4016=CARTESIAN_POINT('',(0.,-1.5,0.));
#4017=DIRECTION('',(0.,-1.,0.));
#4018=DIRECTION('',(1.,0.,0.));
#4019=AXIS2_PLACEMENT_3D('',#4016,#4017,#4018);
#4020=CIRCLE('',#4019,7.5);
#4021=CARTESIAN_POINT('',(7.5,-1.5,0.));
#4022=VERTEX_POINT('',#4021);
#4023=EDGE_CURVE('E749',#4022,#4022,#4020,.T.);
#4024=ORIENTED_EDGE('',*,*,#4023,.T.);
#4025=EDGE_LOOP('',(#4024));
#4026=FACE_BOUND('',#4025,.T.);
#4027=ADVANCED_FACE('F3071',(#4015,#4026),#4004,.F.);
#4028=CARTESIAN_POINT('',(0.,-1.5,0.));
#4029=DIRECTION('',(0.,-1.,0.));
#4030=DIRECTION('',(1.,0.,0.));
#4031=AXIS2_PLACEMENT_3D('',#4028,#4029,#4030);
#4032=CONICAL_SURFACE('',#4031,7.5,0.785398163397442);
#4033=ORIENTED_EDGE('',*,*,#3938,.F.);
#4034=EDGE_LOOP('',(#4033));
#4035=FACE_BOUND('',#4034,.T.);
#4036=ORIENTED_EDGE('',*,*,#4023,.F.);
#4037=EDGE_LOOP('',(#4036));
#4038=FACE_BOUND('',#4037,.T.);
#4039=ADVANCED_FACE('F3073',(#4035,#4038),#4032,.F.);
#4040=CARTESIAN_POINT('',(-14.,3.5,0.));
#4041=DIRECTION('',(0.,1.,0.));
#4042=DIRECTION('',(0.,0.,1.));
#4043=AXIS2_PLACEMENT_3D('',#4040,#4041,#4042);
#4044=CYLINDRICAL_SURFACE('',#4043,3.);
#4045=CARTESIAN_POINT('',(-14.,7.8,0.));
#4046=DIRECTION('',(0.,1.,0.));
#4047=DIRECTION('',(0.,0.,1.));
#4048=AXIS2_PLACEMENT_3D('',#4045,#4046,#4047);
#4049=CIRCLE('',#4048,3.);
#4050=CARTESIAN_POINT('',(-14.,7.8,3.));
#4051=VERTEX_POINT('',#4050);
#4052=EDGE_CURVE('E903',#4051,#4051,#4049,.T.);
#4053=ORIENTED_EDGE('',*,*,#4052,.T.);
#4054=EDGE_LOOP('',(#4053));
#4055=FACE_BOUND('',#4054,.T.);
#4056=CARTESIAN_POINT('',(-14.,4.,0.));
#4057=DIRECTION('',(0.,1.,0.));
#4058=DIRECTION('',(0.,0.,1.));
#4059=AXIS2_PLACEMENT_3D('',#4056,#4057,#4058);
#4060=CIRCLE('',#4059,3.);
#4061=CARTESIAN_POINT('',(-14.,4.,3.));
#4062=VERTEX_POINT('',#4061);
#4063=EDGE_CURVE('E2985',#4062,#4062,#4060,.T.);
#4064=ORIENTED_EDGE('',*,*,#4063,.F.);
#4065=EDGE_LOOP('',(#4064));
#4066=FACE_BOUND('',#4065,.T.);
#4067=ADVANCED_FACE('F2980',(#4055,#4066),#4044,.F.);
#4068=CARTESIAN_POINT('',(14.,3.5,0.));
#4069=DIRECTION('',(0.,1.,0.));
#4070=DIRECTION('',(0.,0.,1.));
#4071=AXIS2_PLACEMENT_3D('',#4068,#4069,#4070);
#4072=CYLINDRICAL_SURFACE('',#4071,3.);
#4073=CARTESIAN_POINT('',(14.,7.8,0.));
#4074=DIRECTION('',(0.,1.,0.));
#4075=DIRECTION('',(0.,0.,1.));
#4076=AXIS2_PLACEMENT_3D('',#4073,#4074,#4075);
#4077=CIRCLE('',#4076,3.);
#4078=CARTESIAN_POINT('',(14.,7.8,3.));
#4079=VERTEX_POINT('',#4078);
#4080=EDGE_CURVE('E795',#4079,#4079,#4077,.T.);
#4081=ORIENTED_EDGE('',*,*,#4080,.T.);
#4082=EDGE_LOOP('',(#4081));
#4083=FACE_BOUND('',#4082,.T.);
#4084=CARTESIAN_POINT('',(14.,4.,0.));
#4085=DIRECTION('',(0.,1.,0.));
#4086=DIRECTION('',(0.,0.,1.));
#4087=AXIS2_PLACEMENT_3D('',#4084,#4085,#4086);
#4088=CIRCLE('',#4087,3.);
#4089=CARTESIAN_POINT('',(14.,4.,3.));
#4090=VERTEX_POINT('',#4089);
#4091=EDGE_CURVE('E838',#4090,#4090,#4088,.T.);
#4092=ORIENTED_EDGE('',*,*,#4091,.F.);
#4093=EDGE_LOOP('',(#4092));
#4094=FACE_BOUND('',#4093,.T.);
#4095=ADVANCED_FACE('F2977',(#4083,#4094),#4072,.F.);
#4096=CARTESIAN_POINT('',(6.,4.,11.7));
#4097=DIRECTION('',(0.,0.,1.));
#4098=DIRECTION('',(1.,0.,0.));
#4099=AXIS2_PLACEMENT_3D('',#4096,#4097,#4098);
#4100=CYLINDRICAL_SURFACE('',#4099,2.5);
#4101=ORIENTED_EDGE('',*,*,#3734,.F.);
#4102=DIRECTION('',(0.,0.,1.));
#4103=VECTOR('',#4102,1.);
#4104=CARTESIAN_POINT('',(6.,6.5,11.7));
#4105=LINE('',#4104,#4103);
#4106=CARTESIAN_POINT('',(6.,6.5,11.7));
#4107=VERTEX_POINT('',#4106);
#4108=EDGE_CURVE('E707',#4107,#3731,#4105,.T.);
#4109=ORIENTED_EDGE('',*,*,#4108,.F.);
#4110=CARTESIAN_POINT('',(6.,4.,11.7));
#4111=DIRECTION('',(0.,0.,-1.));
#4112=DIRECTION('',(-1.,0.,0.));
#4113=AXIS2_PLACEMENT_3D('',#4110,#4111,#4112);
#4114=CIRCLE('',#4113,2.5);
#4115=CARTESIAN_POINT('',(6.,1.5,11.7));
#4116=VERTEX_POINT('',#4115);
#4117=EDGE_CURVE('E694',#4107,#4116,#4114,.T.);
#4118=ORIENTED_EDGE('',*,*,#4117,.T.);
#4119=DIRECTION('',(0.,0.,1.));
#4120=VECTOR('',#4119,1.);
#4121=CARTESIAN_POINT('',(6.,1.5,11.7));
#4122=LINE('',#4121,#4120);
#4123=EDGE_CURVE('E704',#4116,#3733,#4122,.T.);
#4124=ORIENTED_EDGE('',*,*,#4123,.T.);
#4125=EDGE_LOOP('',(#4101,#4109,#4118,#4124));
#4126=FACE_BOUND('',#4125,.T.);
#4127=ADVANCED_FACE('F703',(#4126),#4100,.F.);
#4128=CARTESIAN_POINT('',(6.,1.5,11.7));
#4129=DIRECTION('',(0.,1.,0.));
#4130=DIRECTION('',(-1.,0.,0.));
#4131=AXIS2_PLACEMENT_3D('',#4128,#4129,#4130);
#4132=PLANE('',#4131);
#4133=ORIENTED_EDGE('',*,*,#3742,.F.);
#4134=ORIENTED_EDGE('',*,*,#4123,.F.);
#4135=DIRECTION('',(-1.,0.,0.));
#4136=VECTOR('',#4135,1.);
#4137=CARTESIAN_POINT('',(6.,1.5,11.7));
#4138=LINE('',#4137,#4136);
#4139=CARTESIAN_POINT('',(-6.,1.5,11.7));
#4140=VERTEX_POINT('',#4139);
#4141=EDGE_CURVE('E690',#4116,#4140,#4138,.T.);
#4142=ORIENTED_EDGE('',*,*,#4141,.T.);
#4143=DIRECTION('',(0.,0.,1.));
#4144=VECTOR('',#4143,1.);
#4145=CARTESIAN_POINT('',(-6.,1.5,11.7));
#4146=LINE('',#4145,#4144);
#4147=EDGE_CURVE('E714',#4140,#3741,#4146,.T.);
#4148=ORIENTED_EDGE('',*,*,#4147,.T.);
#4149=EDGE_LOOP('',(#4133,#4134,#4142,#4148));
#4150=FACE_BOUND('',#4149,.T.);
#4151=ADVANCED_FACE('F710',(#4150),#4132,.T.);
#4152=CARTESIAN_POINT('',(-6.,4.,11.7));
#4153=DIRECTION('',(0.,0.,1.));
#4154=DIRECTION('',(1.,0.,0.));
#4155=AXIS2_PLACEMENT_3D('',#4152,#4153,#4154);
#4156=CYLINDRICAL_SURFACE('',#4155,2.5);
#4157=ORIENTED_EDGE('',*,*,#3751,.F.);
#4158=ORIENTED_EDGE('',*,*,#4147,.F.);
#4159=CARTESIAN_POINT('',(-6.,4.,11.7));
#4160=DIRECTION('',(0.,0.,-1.));
#4161=DIRECTION('',(-1.,0.,0.));
#4162=AXIS2_PLACEMENT_3D('',#4159,#4160,#4161);
#4163=CIRCLE('',#4162,2.5);
#4164=CARTESIAN_POINT('',(-6.,6.5,11.7));
#4165=VERTEX_POINT('',#4164);
#4166=EDGE_CURVE('E695',#4140,#4165,#4163,.T.);
#4167=ORIENTED_EDGE('',*,*,#4166,.T.);
#4168=DIRECTION('',(0.,0.,1.));
#4169=VECTOR('',#4168,1.);
#4170=CARTESIAN_POINT('',(-6.,6.5,11.7));
#4171=LINE('',#4170,#4169);
#4172=EDGE_CURVE('E719',#4165,#3750,#4171,.T.);
#4173=ORIENTED_EDGE('',*,*,#4172,.T.);
#4174=EDGE_LOOP('',(#4157,#4158,#4167,#4173));
#4175=FACE_BOUND('',#4174,.T.);
#4176=ADVANCED_FACE('F3007',(#4175),#4156,.F.);
#4177=CARTESIAN_POINT('',(6.,6.5,11.7));
#4178=DIRECTION('',(0.,-1.,0.));
#4179=DIRECTION('',(0.,0.,-1.));
#4180=AXIS2_PLACEMENT_3D('',#4177,#4178,#4179);
#4181=PLANE('',#4180);
#4182=ORIENTED_EDGE('',*,*,#3757,.F.);
#4183=ORIENTED_EDGE('',*,*,#4172,.F.);
#4184=DIRECTION('',(1.,0.,0.));
#4185=VECTOR('',#4184,1.);
#4186=CARTESIAN_POINT('',(6.,6.5,11.7));
#4187=LINE('',#4186,#4185);
#4188=EDGE_CURVE('E2994',#4165,#4107,#4187,.T.);
#4189=ORIENTED_EDGE('',*,*,#4188,.T.);
#4190=ORIENTED_EDGE('',*,*,#4108,.T.);
#4191=EDGE_LOOP('',(#4182,#4183,#4189,#4190));
#4192=FACE_BOUND('',#4191,.T.);
#4193=ADVANCED_FACE('F3009',(#4192),#4181,.T.);
#4194=CARTESIAN_POINT('',(6.,4.,11.7));
#4195=DIRECTION('',(0.,0.,-1.));
#4196=DIRECTION('',(-1.,0.,0.));
#4197=AXIS2_PLACEMENT_3D('',#4194,#4195,#4196);
#4198=PLANE('',#4197);
#4199=ORIENTED_EDGE('',*,*,#544,.F.);
#4200=ORIENTED_EDGE('',*,*,#573,.F.);
#4201=ORIENTED_EDGE('',*,*,#598,.F.);
#4202=ORIENTED_EDGE('',*,*,#615,.F.);
#4203=EDGE_LOOP('',(#4199,#4200,#4201,#4202));
#4204=FACE_BOUND('',#4203,.T.);
#4205=ORIENTED_EDGE('',*,*,#4117,.F.);
#4206=ORIENTED_EDGE('',*,*,#4188,.F.);
#4207=ORIENTED_EDGE('',*,*,#4166,.F.);
#4208=ORIENTED_EDGE('',*,*,#4141,.F.);
#4209=EDGE_LOOP('',(#4205,#4206,#4207,#4208));
#4210=FACE_BOUND('',#4209,.T.);
#4211=ADVANCED_FACE('F692',(#4204,#4210),#4198,.F.);
#4212=CARTESIAN_POINT('',(-14.,4.,0.));
#4213=DIRECTION('',(0.,1.,0.));
#4214=DIRECTION('',(0.,0.,1.));
#4215=AXIS2_PLACEMENT_3D('',#4212,#4213,#4214);
#4216=PLANE('',#4215);
#4217=ORIENTED_EDGE('',*,*,#3298,.T.);
#4218=EDGE_LOOP('',(#4217));
#4219=FACE_BOUND('',#4218,.T.);
#4220=ORIENTED_EDGE('',*,*,#4063,.T.);
#4221=EDGE_LOOP('',(#4220));
#4222=FACE_BOUND('',#4221,.T.);
#4223=ADVANCED_FACE('F3104',(#4219,#4222),#4216,.T.);
#4224=CARTESIAN_POINT('',(14.,4.,0.));
#4225=DIRECTION('',(0.,1.,0.));
#4226=DIRECTION('',(0.,0.,1.));
#4227=AXIS2_PLACEMENT_3D('',#4224,#4225,#4226);
#4228=PLANE('',#4227);
#4229=ORIENTED_EDGE('',*,*,#3543,.T.);
#4230=EDGE_LOOP('',(#4229));
#4231=FACE_BOUND('',#4230,.T.);
#4232=ORIENTED_EDGE('',*,*,#4091,.T.);
#4233=EDGE_LOOP('',(#4232));
#4234=FACE_BOUND('',#4233,.T.);
#4235=ADVANCED_FACE('F3108',(#4231,#4234),#4228,.T.);
#4236=CARTESIAN_POINT('',(-24.5803666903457,0.5,12.));
#4237=DIRECTION('',(0.,-0.707106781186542,0.707106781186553));
#4238=DIRECTION('',(-1.,0.,0.));
#4239=AXIS2_PLACEMENT_3D('',#4236,#4237,#4238);
#4240=PLANE('',#4239);
#4241=CARTESIAN_POINT('',(-13.4164078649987,0.5,12.));
#4242=CARTESIAN_POINT('',(-13.3791133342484,0.416601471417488,11.9166014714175));
#4243=CARTESIAN_POINT('',(-13.341674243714,0.333235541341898,11.8332355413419));
#4244=CARTESIAN_POINT('',(-13.2665069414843,0.166568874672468,11.6665688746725));
#4245=CARTESIAN_POINT('',(-13.2287787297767,0.0832681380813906,11.5832681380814));
#4246=CARTESIAN_POINT('',(-13.1909059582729,0.,11.5));
#4247=B_SPLINE_CURVE_WITH_KNOTS('',3,(#4241,#4242,#4243,#4244,#4245,#4246),.UNSPECIFIED.,.F.,
.F.,(4,2,4),(0.,0.371096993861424,0.74219400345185),.UNSPECIFIED.);
#4248=EDGE_CURVE('E839',#3856,#3698,#4247,.F.);
#4249=ORIENTED_EDGE('',*,*,#4248,.F.);
#4250=ORIENTED_EDGE('',*,*,#3882,.F.);
#4251=CARTESIAN_POINT('',(13.4164078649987,0.5,12.));
#4252=CARTESIAN_POINT('',(13.3791133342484,0.416601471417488,11.9166014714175));
#4253=CARTESIAN_POINT('',(13.341674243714,0.333235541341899,11.8332355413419));
#4254=CARTESIAN_POINT('',(13.2665069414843,0.166568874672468,11.6665688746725));
#4255=CARTESIAN_POINT('',(13.2287787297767,0.0832681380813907,11.5832681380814));
#4256=CARTESIAN_POINT('',(13.1909059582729,0.,11.5));
#4257=B_SPLINE_CURVE_WITH_KNOTS('',3,(#4251,#4252,#4253,#4254,#4255,#4256),.UNSPECIFIED.,.F.,
.F.,(4,2,4),(0.,0.371096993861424,0.742194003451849),.UNSPECIFIED.);
#4258=EDGE_CURVE('E831',#3706,#3875,#4257,.T.);
#4259=ORIENTED_EDGE('',*,*,#4258,.F.);
#4260=ORIENTED_EDGE('',*,*,#3707,.F.);
#4261=EDGE_LOOP('',(#4249,#4250,#4259,#4260));
#4262=FACE_BOUND('',#4261,.T.);
#4263=ADVANCED_FACE('F825',(#4262),#4240,.T.);
#4264=CARTESIAN_POINT('',(0.,0.,0.));
#4265=DIRECTION('',(0.,1.,0.));
#4266=DIRECTION('',(-1.,0.,0.));
#4267=AXIS2_PLACEMENT_3D('',#4264,#4265,#4266);
#4268=CONICAL_SURFACE('',#4267,17.5,0.785398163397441);
#4269=ORIENTED_EDGE('',*,*,#4258,.T.);
#4270=ORIENTED_EDGE('',*,*,#3876,.F.);
#4271=CARTESIAN_POINT('',(13.1909059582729,0.,-11.5));
#4272=CARTESIAN_POINT('',(13.2287787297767,0.0832681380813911,-11.5832681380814));
#4273=CARTESIAN_POINT('',(13.2665069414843,0.166568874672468,-11.6665688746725));
#4274=CARTESIAN_POINT('',(13.341674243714,0.333235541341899,-11.8332355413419));
#4275=CARTESIAN_POINT('',(13.3791133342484,0.416601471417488,-11.9166014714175));
#4276=CARTESIAN_POINT('',(13.4164078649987,0.5,-12.));
#4277=B_SPLINE_CURVE_WITH_KNOTS('',3,(#4271,#4272,#4273,#4274,#4275,#4276),.UNSPECIFIED.,.F.,
.F.,(4,2,4),(0.,0.371097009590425,0.742194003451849),.UNSPECIFIED.);
#4278=EDGE_CURVE('E804',#3802,#3866,#4277,.F.);
#4279=ORIENTED_EDGE('',*,*,#4278,.F.);
#4280=ORIENTED_EDGE('',*,*,#3803,.F.);
#4281=EDGE_LOOP('',(#4269,#4270,#4279,#4280));
#4282=FACE_BOUND('',#4281,.T.);
#4283=ADVANCED_FACE('F820',(#4282),#4268,.T.);
#4284=CARTESIAN_POINT('',(0.,0.,0.));
#4285=DIRECTION('',(0.,1.,0.));
#4286=DIRECTION('',(-1.,0.,0.));
#4287=AXIS2_PLACEMENT_3D('',#4284,#4285,#4286);
#4288=CONICAL_SURFACE('',#4287,17.5,0.785398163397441);
#4289=ORIENTED_EDGE('',*,*,#4248,.T.);
#4290=ORIENTED_EDGE('',*,*,#3782,.F.);
#4291=CARTESIAN_POINT('',(-13.4164078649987,0.5,-12.));
#4292=CARTESIAN_POINT('',(-13.3791133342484,0.416601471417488,-11.9166014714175));
#4293=CARTESIAN_POINT('',(-13.341674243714,0.333235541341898,-11.8332355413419));
#4294=CARTESIAN_POINT('',(-13.2665069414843,0.166568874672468,-11.6665688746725));
#4295=CARTESIAN_POINT('',(-13.2287787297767,0.0832681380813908,-11.5832681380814));
#4296=CARTESIAN_POINT('',(-13.1909059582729,0.,-11.5));
#4297=B_SPLINE_CURVE_WITH_KNOTS('',3,(#4291,#4292,#4293,#4294,#4295,#4296),.UNSPECIFIED.,.F.,
.F.,(4,2,4),(0.,0.371096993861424,0.742194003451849),.UNSPECIFIED.);
#4298=EDGE_CURVE('E796',#3858,#3772,#4297,.F.);
#4299=ORIENTED_EDGE('',*,*,#4298,.F.);
#4300=ORIENTED_EDGE('',*,*,#3859,.F.);
#4301=EDGE_LOOP('',(#4289,#4290,#4299,#4300));
#4302=FACE_BOUND('',#4301,.T.);
#4303=ADVANCED_FACE('F812',(#4302),#4288,.T.);
#4304=CARTESIAN_POINT('',(-24.5803666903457,0.5,-12.));
#4305=DIRECTION('',(0.,-0.707106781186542,-0.707106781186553));
#4306=DIRECTION('',(1.,0.,0.));
#4307=AXIS2_PLACEMENT_3D('',#4304,#4305,#4306);
#4308=PLANE('',#4307);
#4309=ORIENTED_EDGE('',*,*,#4278,.T.);
#4310=ORIENTED_EDGE('',*,*,#3867,.F.);
#4311=ORIENTED_EDGE('',*,*,#4298,.T.);
#4312=ORIENTED_EDGE('',*,*,#3964,.F.);
#4313=EDGE_LOOP('',(#4309,#4310,#4311,#4312));
#4314=FACE_BOUND('',#4313,.T.);
#4315=ADVANCED_FACE('F815',(#4314),#4308,.T.);
#4316=CARTESIAN_POINT('',(0.,8.,11.5));
#4317=DIRECTION('',(0.,0.707106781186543,0.707106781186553));
#4318=DIRECTION('',(-1.,0.,0.));
#4319=AXIS2_PLACEMENT_3D('',#4316,#4317,#4318);
#4320=PLANE('',#4319);
#4321=CARTESIAN_POINT('',(-13.4164078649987,7.5,12.));
#4322=CARTESIAN_POINT('',(-13.3791133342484,7.58339852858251,11.9166014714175));
#4323=CARTESIAN_POINT('',(-13.341674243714,7.6667644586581,11.8332355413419));
#4324=CARTESIAN_POINT('',(-13.2665069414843,7.83343112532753,11.6665688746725));
#4325=CARTESIAN_POINT('',(-13.2287787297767,7.91673186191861,11.5832681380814));
#4326=CARTESIAN_POINT('',(-13.1909059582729,8.,11.5));
#4327=B_SPLINE_CURVE_WITH_KNOTS('',3,(#4321,#4322,#4323,#4324,#4325,#4326),.UNSPECIFIED.,.F.,
.F.,(4,2,4),(0.,0.371096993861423,0.742194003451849),.UNSPECIFIED.);
#4328=EDGE_CURVE('E882',#3696,#3649,#4327,.T.);
#4329=ORIENTED_EDGE('',*,*,#4328,.F.);
#4330=ORIENTED_EDGE('',*,*,#3721,.F.);
#4331=CARTESIAN_POINT('',(13.4164078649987,7.5,12.));
#4332=CARTESIAN_POINT('',(13.3791133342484,7.58339852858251,11.9166014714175));
#4333=CARTESIAN_POINT('',(13.341674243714,7.6667644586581,11.8332355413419));
#4334=CARTESIAN_POINT('',(13.2665069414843,7.83343112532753,11.6665688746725));
#4335=CARTESIAN_POINT('',(13.2287787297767,7.91673186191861,11.5832681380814));
#4336=CARTESIAN_POINT('',(13.1909059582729,8.,11.5));
#4337=B_SPLINE_CURVE_WITH_KNOTS('',3,(#4331,#4332,#4333,#4334,#4335,#4336),.UNSPECIFIED.,.F.,
.F.,(4,2,4),(0.,0.371096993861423,0.742194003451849),.UNSPECIFIED.);
#4338=EDGE_CURVE('E805',#3630,#3714,#4337,.F.);
#4339=ORIENTED_EDGE('',*,*,#4338,.F.);
#4340=ORIENTED_EDGE('',*,*,#3656,.F.);
#4341=EDGE_LOOP('',(#4329,#4330,#4339,#4340));
#4342=FACE_BOUND('',#4341,.T.);
#4343=ADVANCED_FACE('F818',(#4342),#4320,.T.);
#4344=CARTESIAN_POINT('',(0.,8.,0.));
#4345=DIRECTION('',(0.,-1.,0.));
#4346=DIRECTION('',(1.,0.,0.));
#4347=AXIS2_PLACEMENT_3D('',#4344,#4345,#4346);
#4348=CONICAL_SURFACE('',#4347,17.5,0.785398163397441);
#4349=ORIENTED_EDGE('',*,*,#4338,.T.);
#4350=ORIENTED_EDGE('',*,*,#3818,.F.);
#4351=CARTESIAN_POINT('',(13.4164078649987,7.5,-12.));
#4352=CARTESIAN_POINT('',(13.3791133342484,7.58339852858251,-11.9166014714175));
#4353=CARTESIAN_POINT('',(13.341674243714,7.6667644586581,-11.8332355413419));
#4354=CARTESIAN_POINT('',(13.2665069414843,7.83343112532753,-11.6665688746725));
#4355=CARTESIAN_POINT('',(13.2287787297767,7.91673186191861,-11.5832681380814));
#4356=CARTESIAN_POINT('',(13.1909059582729,8.,-11.5));
#4357=B_SPLINE_CURVE_WITH_KNOTS('',3,(#4351,#4352,#4353,#4354,#4355,#4356),.UNSPECIFIED.,.F.,
.F.,(4,2,4),(0.,0.371096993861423,0.742194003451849),.UNSPECIFIED.);
#4358=EDGE_CURVE('E851',#3632,#3810,#4357,.F.);
#4359=ORIENTED_EDGE('',*,*,#4358,.F.);
#4360=ORIENTED_EDGE('',*,*,#3633,.F.);
#4361=EDGE_LOOP('',(#4349,#4350,#4359,#4360));
#4362=FACE_BOUND('',#4361,.T.);
#4363=ADVANCED_FACE('F866',(#4362),#4348,.T.);
#4364=CARTESIAN_POINT('',(0.,8.,0.));
#4365=DIRECTION('',(0.,-1.,0.));
#4366=DIRECTION('',(1.,0.,0.));
#4367=AXIS2_PLACEMENT_3D('',#4364,#4365,#4366);
#4368=CONICAL_SURFACE('',#4367,17.5,0.785398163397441);
#4369=ORIENTED_EDGE('',*,*,#4328,.T.);
#4370=ORIENTED_EDGE('',*,*,#3650,.F.);
#4371=CARTESIAN_POINT('',(-13.1909059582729,8.,-11.5));
#4372=CARTESIAN_POINT('',(-13.2287787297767,7.91673186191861,-11.5832681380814));
#4373=CARTESIAN_POINT('',(-13.2665069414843,7.83343112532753,-11.6665688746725));
#4374=CARTESIAN_POINT('',(-13.341674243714,7.6667644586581,-11.8332355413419));
#4375=CARTESIAN_POINT('',(-13.3791133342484,7.58339852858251,-11.9166014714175));
#4376=CARTESIAN_POINT('',(-13.4164078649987,7.5,-12.));
#4377=B_SPLINE_CURVE_WITH_KNOTS('',3,(#4371,#4372,#4373,#4374,#4375,#4376),.UNSPECIFIED.,.F.,
.F.,(4,2,4),(0.,0.371097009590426,0.742194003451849),.UNSPECIFIED.);
#4378=EDGE_CURVE('E844',#3774,#3640,#4377,.F.);
#4379=ORIENTED_EDGE('',*,*,#4378,.F.);
#4380=ORIENTED_EDGE('',*,*,#3790,.F.);
#4381=EDGE_LOOP('',(#4369,#4370,#4379,#4380));
#4382=FACE_BOUND('',#4381,.T.);
#4383=ADVANCED_FACE('F859',(#4382),#4368,.T.);
#4384=CARTESIAN_POINT('',(0.,8.,-11.5));
#4385=DIRECTION('',(0.,0.707106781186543,-0.707106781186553));
#4386=DIRECTION('',(1.,0.,0.));
#4387=AXIS2_PLACEMENT_3D('',#4384,#4385,#4386);
#4388=PLANE('',#4387);
#4389=ORIENTED_EDGE('',*,*,#4358,.T.);
#4390=ORIENTED_EDGE('',*,*,#3971,.F.);
#4391=ORIENTED_EDGE('',*,*,#4378,.T.);
#4392=ORIENTED_EDGE('',*,*,#3641,.F.);
#4393=EDGE_LOOP('',(#4389,#4390,#4391,#4392));
#4394=FACE_BOUND('',#4393,.T.);
#4395=ADVANCED_FACE('F861',(#4394),#4388,.T.);
#4396=CARTESIAN_POINT('',(14.,7.8,0.));
#4397=DIRECTION('',(0.,1.,0.));
#4398=DIRECTION('',(0.,0.,1.));
#4399=AXIS2_PLACEMENT_3D('',#4396,#4397,#4398);
#4400=CONICAL_SURFACE('',#4399,3.,0.785398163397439);
#4401=ORIENTED_EDGE('',*,*,#3678,.F.);
#4402=EDGE_LOOP('',(#4401));
#4403=FACE_BOUND('',#4402,.T.);
#4404=ORIENTED_EDGE('',*,*,#4080,.F.);
#4405=EDGE_LOOP('',(#4404));
#4406=FACE_BOUND('',#4405,.T.);
#4407=ADVANCED_FACE('F864',(#4403,#4406),#4400,.F.);
#4408=CARTESIAN_POINT('',(14.,0.200000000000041,0.));
#4409=DIRECTION('',(0.,-1.,0.));
#4410=DIRECTION('',(0.,0.,-1.));
#4411=AXIS2_PLACEMENT_3D('',#4408,#4409,#4410);
#4412=CONICAL_SURFACE('',#4411,1.75,0.785398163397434);
#4413=ORIENTED_EDGE('',*,*,#3835,.F.);
#4414=EDGE_LOOP('',(#4413));
#4415=FACE_BOUND('',#4414,.T.);
#4416=CARTESIAN_POINT('',(14.,0.200000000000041,0.));
#4417=DIRECTION('',(0.,-1.,0.));
#4418=DIRECTION('',(0.,0.,-1.));
#4419=AXIS2_PLACEMENT_3D('',#4416,#4417,#4418);
#4420=CIRCLE('',#4419,1.75);
#4421=CARTESIAN_POINT('',(14.,0.200000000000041,-1.75));
#4422=VERTEX_POINT('',#4421);
#4423=EDGE_CURVE('E980',#4422,#4422,#4420,.F.);
#4424=ORIENTED_EDGE('',*,*,#4423,.T.);
#4425=EDGE_LOOP('',(#4424));
#4426=FACE_BOUND('',#4425,.T.);
#4427=ADVANCED_FACE('F2964',(#4415,#4426),#4412,.F.);
#4428=CARTESIAN_POINT('',(-14.,0.200000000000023,0.));
#4429=DIRECTION('',(0.,-1.,0.));
#4430=DIRECTION('',(0.,0.,-1.));
#4431=AXIS2_PLACEMENT_3D('',#4428,#4429,#4430);
#4432=CONICAL_SURFACE('',#4431,1.75,0.785398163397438);
#4433=ORIENTED_EDGE('',*,*,#3846,.F.);
#4434=EDGE_LOOP('',(#4433));
#4435=FACE_BOUND('',#4434,.T.);
#4436=CARTESIAN_POINT('',(-14.,0.200000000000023,0.));
#4437=DIRECTION('',(0.,-1.,0.));
#4438=DIRECTION('',(0.,0.,-1.));
#4439=AXIS2_PLACEMENT_3D('',#4436,#4437,#4438);
#4440=CIRCLE('',#4439,1.75);
#4441=CARTESIAN_POINT('',(-14.,0.200000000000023,-1.75));
#4442=VERTEX_POINT('',#4441);
#4443=EDGE_CURVE('E1047',#4442,#4442,#4440,.F.);
#4444=ORIENTED_EDGE('',*,*,#4443,.T.);
#4445=EDGE_LOOP('',(#4444));
#4446=FACE_BOUND('',#4445,.T.);
#4447=ADVANCED_FACE('F2960',(#4435,#4446),#4432,.F.);
#4448=CARTESIAN_POINT('',(-14.,7.8,0.));
#4449=DIRECTION('',(0.,1.,0.));
#4450=DIRECTION('',(0.,0.,1.));
#4451=AXIS2_PLACEMENT_3D('',#4448,#4449,#4450);
#4452=CONICAL_SURFACE('',#4451,3.,0.785398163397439);
#4453=ORIENTED_EDGE('',*,*,#3667,.F.);
#4454=EDGE_LOOP('',(#4453));
#4455=FACE_BOUND('',#4454,.T.);
#4456=ORIENTED_EDGE('',*,*,#4052,.F.);
#4457=EDGE_LOOP('',(#4456));
#4458=FACE_BOUND('',#4457,.T.);
#4459=ADVANCED_FACE('F2956',(#4455,#4458),#4452,.F.);
#4460=CARTESIAN_POINT('',(0.,28.,0.));
#4461=DIRECTION('',(0.,1.,0.));
#4462=DIRECTION('',(-1.,0.,0.));
#4463=AXIS2_PLACEMENT_3D('',#4460,#4461,#4462);
#4464=PLANE('',#4463);
#4465=ORIENTED_EDGE('',*,*,#3574,.F.);
#4466=EDGE_LOOP('',(#4465));
#4467=FACE_BOUND('',#4466,.T.);
#4468=CARTESIAN_POINT('',(0.,28.,0.));
#4469=DIRECTION('',(0.,-1.,0.));
#4470=DIRECTION('',(0.,0.,-1.));
#4471=AXIS2_PLACEMENT_3D('',#4468,#4469,#4470);
#4472=CIRCLE('',#4471,6.1);
#4473=CARTESIAN_POINT('',(0.,28.,-6.1));
#4474=VERTEX_POINT('',#4473);
#4475=EDGE_CURVE('E915',#4474,#4474,#4472,.T.);
#4476=ORIENTED_EDGE('',*,*,#4475,.T.);
#4477=EDGE_LOOP('',(#4476));
#4478=FACE_BOUND('',#4477,.T.);
#4479=ADVANCED_FACE('F2959',(#4467,#4478),#4464,.T.);
#4480=CARTESIAN_POINT('',(9.5,0.,0.));
#4481=DIRECTION('',(0.,-1.,0.));
#4482=DIRECTION('',(0.,0.,-1.));
#4483=AXIS2_PLACEMENT_3D('',#4480,#4481,#4482);
#4484=PLANE('',#4483);
#4485=CARTESIAN_POINT('',(0.,0.,0.));
#4486=DIRECTION('',(0.,-1.,0.));
#4487=DIRECTION('',(0.,0.,-1.));
#4488=AXIS2_PLACEMENT_3D('',#4485,#4486,#4487);
#4489=CIRCLE('',#4488,5.25);
#4490=CARTESIAN_POINT('',(0.,0.,-5.25));
#4491=VERTEX_POINT('',#4490);
#4492=EDGE_CURVE('E3127',#4491,#4491,#4489,.T.);
#4493=ORIENTED_EDGE('',*,*,#4492,.F.);
#4494=EDGE_LOOP('',(#4493));
#4495=FACE_BOUND('',#4494,.T.);
#4496=ORIENTED_EDGE('',*,*,#4012,.F.);
#4497=EDGE_LOOP('',(#4496));
#4498=FACE_BOUND('',#4497,.T.);
#4499=ADVANCED_FACE('F3042',(#4495,#4498),#4484,.T.);
#4500=CARTESIAN_POINT('',(0.,0.,0.));
#4501=DIRECTION('',(0.,-1.,0.));
#4502=DIRECTION('',(0.,0.,-1.));
#4503=AXIS2_PLACEMENT_3D('',#4500,#4501,#4502);
#4504=CYLINDRICAL_SURFACE('',#4503,6.1);
#4505=CARTESIAN_POINT('',(0.,8.5,0.));
#4506=DIRECTION('',(0.,-1.,0.));
#4507=DIRECTION('',(0.,0.,-1.));
#4508=AXIS2_PLACEMENT_3D('',#4505,#4506,#4507);
#4509=CIRCLE('',#4508,6.1);
#4510=CARTESIAN_POINT('',(0.,8.5,-6.1));
#4511=VERTEX_POINT('',#4510);
#4512=EDGE_CURVE('E734',#4511,#4511,#4509,.T.);
#4513=ORIENTED_EDGE('',*,*,#4512,.T.);
#4514=EDGE_LOOP('',(#4513));
#4515=FACE_BOUND('',#4514,.T.);
#4516=ORIENTED_EDGE('',*,*,#4475,.F.);
#4517=EDGE_LOOP('',(#4516));
#4518=FACE_BOUND('',#4517,.T.);
#4519=ADVANCED_FACE('F3038',(#4515,#4518),#4504,.F.);
#4520=CARTESIAN_POINT('',(6.1,8.5,0.));
#4521=DIRECTION('',(0.,-1.,0.));
#4522=DIRECTION('',(0.,0.,-1.));
#4523=AXIS2_PLACEMENT_3D('',#4520,#4521,#4522);
#4524=PLANE('',#4523);
#4525=ORIENTED_EDGE('',*,*,#4512,.F.);
#4526=EDGE_LOOP('',(#4525));
#4527=FACE_BOUND('',#4526,.T.);
#4528=CARTESIAN_POINT('',(0.,8.5,0.));
#4529=DIRECTION('',(0.,-1.,0.));
#4530=DIRECTION('',(0.,0.,-1.));
#4531=AXIS2_PLACEMENT_3D('',#4528,#4529,#4530);
#4532=CIRCLE('',#4531,5.25);
#4533=CARTESIAN_POINT('',(0.,8.5,-5.25));
#4534=VERTEX_POINT('',#4533);
#4535=EDGE_CURVE('E731',#4534,#4534,#4532,.T.);
#4536=ORIENTED_EDGE('',*,*,#4535,.T.);
#4537=EDGE_LOOP('',(#4536));
#4538=FACE_BOUND('',#4537,.T.);
#4539=ADVANCED_FACE('F3034',(#4527,#4538),#4524,.F.);
#4540=CARTESIAN_POINT('',(0.,0.,0.));
#4541=DIRECTION('',(0.,-1.,0.));
#4542=DIRECTION('',(0.,0.,-1.));
#4543=AXIS2_PLACEMENT_3D('',#4540,#4541,#4542);
#4544=CYLINDRICAL_SURFACE('',#4543,5.25);
#4545=ORIENTED_EDGE('',*,*,#4535,.F.);
#4546=EDGE_LOOP('',(#4545));
#4547=FACE_BOUND('',#4546,.T.);
#4548=ORIENTED_EDGE('',*,*,#4492,.T.);
#4549=EDGE_LOOP('',(#4548));
#4550=FACE_BOUND('',#4549,.T.);
#4551=ADVANCED_FACE('F2951',(#4547,#4550),#4544,.F.);
#4552=CARTESIAN_POINT('',(14.,-4.,0.));
#4553=DIRECTION('',(0.,-1.,0.));
#4554=DIRECTION('',(1.00000000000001,0.,0.));
#4555=AXIS2_PLACEMENT_3D('',#4552,#4553,#4554);
#4556=PLANE('',#4555);
#4557=CARTESIAN_POINT('',(14.,-4.,0.));
#4558=DIRECTION('',(0.,-1.,0.));
#4559=DIRECTION('',(1.00000000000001,0.,0.));
#4560=AXIS2_PLACEMENT_3D('',#4557,#4558,#4559);
#4561=CIRCLE('',#4560,1.);
#4562=CARTESIAN_POINT('',(15.,-4.,1.04502754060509E-13));
#4563=VERTEX_POINT('',#4562);
#4564=EDGE_CURVE('E970',#4563,#4563,#4561,.T.);
#4565=ORIENTED_EDGE('',*,*,#4564,.T.);
#4566=EDGE_LOOP('',(#4565));
#4567=FACE_BOUND('',#4566,.T.);
#4568=ADVANCED_FACE('F2908',(#4567),#4556,.T.);
#4569=CARTESIAN_POINT('',(14.,-4.,0.));
#4570=DIRECTION('',(0.,1.,0.));
#4571=DIRECTION('',(0.,0.,-1.00000000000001));
#4572=AXIS2_PLACEMENT_3D('',#4569,#4570,#4571);
#4573=CONICAL_SURFACE('',#4572,1.,0.785398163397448);
#4574=CARTESIAN_POINT('',(14.,-3.5,0.));
#4575=DIRECTION('',(0.,-1.,0.));
#4576=DIRECTION('',(0.,0.,1.00000000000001));
#4577=AXIS2_PLACEMENT_3D('',#4574,#4575,#4576);
#4578=CIRCLE('',#4577,1.5);
#4579=CARTESIAN_POINT('',(14.,-3.5,1.50000000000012));
#4580=VERTEX_POINT('',#4579);
#4581=EDGE_CURVE('E973',#4580,#4580,#4578,.F.);
#4582=ORIENTED_EDGE('',*,*,#4581,.F.);
#4583=EDGE_LOOP('',(#4582));
#4584=FACE_BOUND('',#4583,.T.);
#4585=ORIENTED_EDGE('',*,*,#4564,.F.);
#4586=EDGE_LOOP('',(#4585));
#4587=FACE_BOUND('',#4586,.T.);
#4588=ADVANCED_FACE('F2904',(#4584,#4587),#4573,.T.);
#4589=CARTESIAN_POINT('',(14.,14.,0.));
#4590=DIRECTION('',(0.,1.,0.));
#4591=DIRECTION('',(-1.00000000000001,0.,0.));
#4592=AXIS2_PLACEMENT_3D('',#4589,#4590,#4591);
#4593=CYLINDRICAL_SURFACE('',#4592,1.5);
#4594=CARTESIAN_POINT('',(14.,0.200000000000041,0.));
#4595=DIRECTION('',(0.,-1.,0.));
#4596=DIRECTION('',(0.,0.,-1.));
#4597=AXIS2_PLACEMENT_3D('',#4594,#4595,#4596);
#4598=CIRCLE('',#4597,1.5);
#4599=CARTESIAN_POINT('',(14.,0.200000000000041,-1.4999999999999));
#4600=VERTEX_POINT('',#4599);
#4601=EDGE_CURVE('E977',#4600,#4600,#4598,.F.);
#4602=ORIENTED_EDGE('',*,*,#4601,.F.);
#4603=EDGE_LOOP('',(#4602));
#4604=FACE_BOUND('',#4603,.T.);
#4605=ORIENTED_EDGE('',*,*,#4581,.T.);
#4606=EDGE_LOOP('',(#4605));
#4607=FACE_BOUND('',#4606,.T.);
#4608=ADVANCED_FACE('F2907',(#4604,#4607),#4593,.T.);
#4609=CARTESIAN_POINT('',(14.,0.200000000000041,0.));
#4610=DIRECTION('',(0.,-1.,0.));
#4611=DIRECTION('',(0.,0.,-1.));
#4612=AXIS2_PLACEMENT_3D('',#4609,#4610,#4611);
#4613=PLANE('',#4612);
#4614=ORIENTED_EDGE('',*,*,#4601,.T.);
#4615=EDGE_LOOP('',(#4614));
#4616=FACE_BOUND('',#4615,.T.);
#4617=ORIENTED_EDGE('',*,*,#4423,.F.);
#4618=EDGE_LOOP('',(#4617));
#4619=FACE_BOUND('',#4618,.T.);
#4620=ADVANCED_FACE('F2899',(#4616,#4619),#4613,.T.);
#4621=CARTESIAN_POINT('',(-14.,-4.,0.));
#4622=DIRECTION('',(0.,-1.,0.));
#4623=DIRECTION('',(-1.00000000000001,0.,0.));
#4624=AXIS2_PLACEMENT_3D('',#4621,#4622,#4623);
#4625=PLANE('',#4624);
#4626=CARTESIAN_POINT('',(-14.,-4.,0.));
#4627=DIRECTION('',(0.,-1.,0.));
#4628=DIRECTION('',(-1.00000000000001,0.,0.));
#4629=AXIS2_PLACEMENT_3D('',#4626,#4627,#4628);
#4630=CIRCLE('',#4629,1.);
#4631=CARTESIAN_POINT('',(-15.,-4.,0.));
#4632=VERTEX_POINT('',#4631);
#4633=EDGE_CURVE('E1038',#4632,#4632,#4630,.T.);
#4634=ORIENTED_EDGE('',*,*,#4633,.T.);
#4635=EDGE_LOOP('',(#4634));
#4636=FACE_BOUND('',#4635,.T.);
#4637=ADVANCED_FACE('F2856',(#4636),#4625,.T.);
#4638=CARTESIAN_POINT('',(-14.,-4.,0.));
#4639=DIRECTION('',(0.,1.,0.));
#4640=DIRECTION('',(0.,0.,1.00000000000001));
#4641=AXIS2_PLACEMENT_3D('',#4638,#4639,#4640);
#4642=CONICAL_SURFACE('',#4641,1.,0.785398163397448);
#4643=CARTESIAN_POINT('',(-14.,-3.5,0.));
#4644=DIRECTION('',(0.,-1.,0.));
#4645=DIRECTION('',(0.,0.,-1.00000000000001));
#4646=AXIS2_PLACEMENT_3D('',#4643,#4644,#4645);
#4647=CIRCLE('',#4646,1.5);
#4648=CARTESIAN_POINT('',(-14.,-3.5,-1.50000000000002));
#4649=VERTEX_POINT('',#4648);
#4650=EDGE_CURVE('E1041',#4649,#4649,#4647,.F.);
#4651=ORIENTED_EDGE('',*,*,#4650,.F.);
#4652=EDGE_LOOP('',(#4651));
#4653=FACE_BOUND('',#4652,.T.);
#4654=ORIENTED_EDGE('',*,*,#4633,.F.);
#4655=EDGE_LOOP('',(#4654));
#4656=FACE_BOUND('',#4655,.T.);
#4657=ADVANCED_FACE('F2852',(#4653,#4656),#4642,.T.);
#4658=CARTESIAN_POINT('',(-14.,14.,0.));
#4659=DIRECTION('',(0.,1.,0.));
#4660=DIRECTION('',(1.00000000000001,0.,0.));
#4661=AXIS2_PLACEMENT_3D('',#4658,#4659,#4660);
#4662=CYLINDRICAL_SURFACE('',#4661,1.5);
#4663=CARTESIAN_POINT('',(-14.,0.200000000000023,0.));
#4664=DIRECTION('',(0.,-1.,0.));
#4665=DIRECTION('',(0.,0.,-1.));
#4666=AXIS2_PLACEMENT_3D('',#4663,#4664,#4665);
#4667=CIRCLE('',#4666,1.5);
#4668=CARTESIAN_POINT('',(-14.,0.200000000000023,-1.5));
#4669=VERTEX_POINT('',#4668);
#4670=EDGE_CURVE('E1044',#4669,#4669,#4667,.F.);
#4671=ORIENTED_EDGE('',*,*,#4670,.F.);
#4672=EDGE_LOOP('',(#4671));
#4673=FACE_BOUND('',#4672,.T.);
#4674=ORIENTED_EDGE('',*,*,#4650,.T.);
#4675=EDGE_LOOP('',(#4674));
#4676=FACE_BOUND('',#4675,.T.);
#4677=ADVANCED_FACE('F2855',(#4673,#4676),#4662,.T.);
#4678=CARTESIAN_POINT('',(-14.,0.200000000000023,0.));
#4679=DIRECTION('',(0.,-1.,0.));
#4680=DIRECTION('',(0.,0.,-1.));
#4681=AXIS2_PLACEMENT_3D('',#4678,#4679,#4680);
#4682=PLANE('',#4681);
#4683=ORIENTED_EDGE('',*,*,#4670,.T.);
#4684=EDGE_LOOP('',(#4683));
#4685=FACE_BOUND('',#4684,.T.);
#4686=ORIENTED_EDGE('',*,*,#4443,.F.);
#4687=EDGE_LOOP('',(#4686));
#4688=FACE_BOUND('',#4687,.T.);
#4689=ADVANCED_FACE('F2871',(#4685,#4688),#4682,.T.);
#4690=CLOSED_SHELL('',(#522,#554,#578,#603,#620,#660,#691,#724,#766,#797,#828,#870,#901,#943,
#976,#1016,#1047,#1089,#1120,#1153,#1195,#1226,#1258,#1283,#1307,#1331,#1355,#1380,#1404,#1429,
#1453,#1477,#1501,#1526,#1550,#1575,#1600,#1625,#1649,#1674,#1698,#1722,#1746,#1770,#1794,#1816,
#1840,#1864,#1888,#1906,#1930,#1998,#2004,#2011,#2017,#2023,#2029,#2036,#2043,#2074,#2098,#2122,
#2139,#2151,#2183,#2207,#2231,#2255,#2280,#2304,#2328,#2352,#2377,#2401,#2425,#2449,#2467,#2488,
#2519,#2543,#2567,#2591,#2615,#2639,#2663,#2705,#2736,#2767,#2789,#2807,#2829,#2836,#2864,#2884,
#2896,#2900,#2931,#2956,#2980,#3004,#3028,#3046,#3060,#3100,#3131,#3162,#3193,#3224,#3246,#3260,
#3285,#3305,#3345,#3376,#3407,#3438,#3469,#3491,#3505,#3530,#3550,#3578,#3598,#3618,#3685,#3761,
#3794,#3822,#3897,#3925,#3953,#3975,#3987,#3999,#4027,#4039,#4067,#4095,#4127,#4151,#4176,#4193,
#4211,#4223,#4235,#4263,#4283,#4303,#4315,#4343,#4363,#4383,#4395,#4407,#4427,#4447,#4459,#4479,
#4499,#4519,#4539,#4551,#4568,#4588,#4608,#4620,#4637,#4657,#4677,#4689));
#4691=MANIFOLD_SOLID_BREP('B1',#4690);
#4692=ADVANCED_BREP_SHAPE_REPRESENTATION('',(#18,#4691),#14);
#4693=SHAPE_DEFINITION_REPRESENTATION(#9,#4692);
ENDSEC;
END-ISO-10303-21;
